VERSION 5.8 ;
BUSBITCHARS "[]" ;
DIVIDERCHAR "/" ;
UNITS
    DATABASE MICRONS 1000 ;
END UNITS

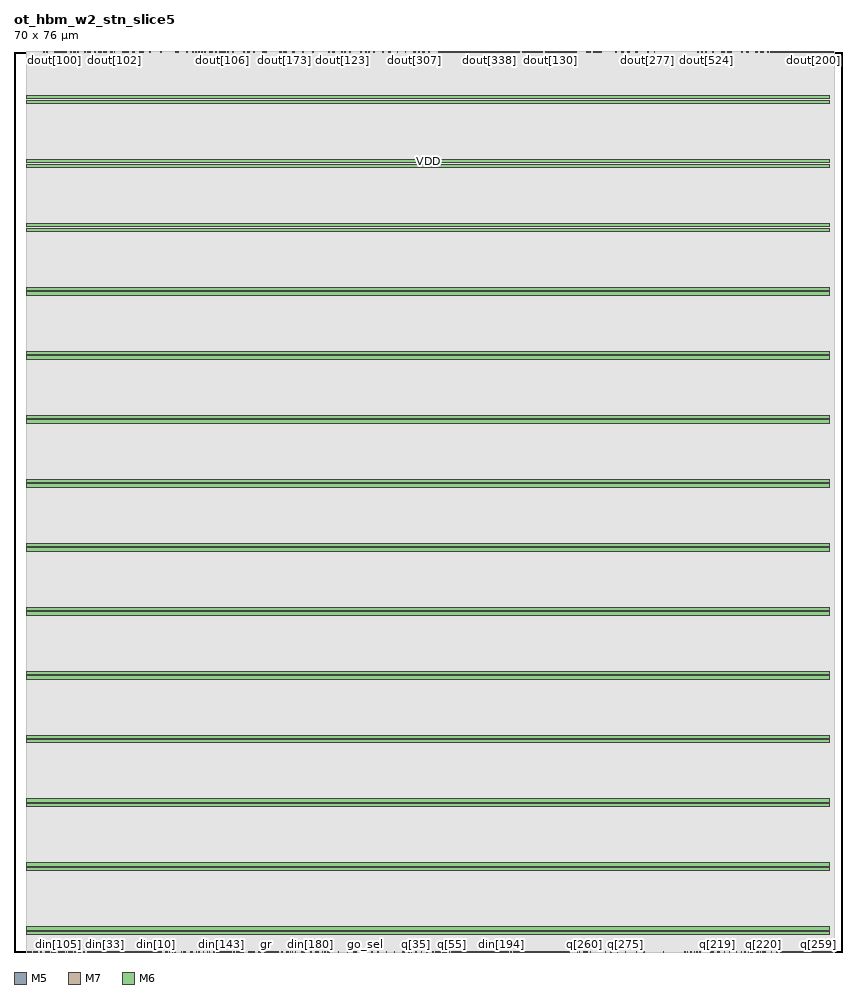
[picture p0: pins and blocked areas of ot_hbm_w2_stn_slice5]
MACRO ot_hbm_w2_stn_slice5
  FOREIGN ot_hbm_w2_stn_slice5 0 0 ;
  CLASS BLOCK ;
  SIZE 70 BY 76 ;
  PIN clk
    DIRECTION INPUT ;
    USE SIGNAL ;
    PORT
      LAYER M5 ;
        RECT  1.488 0 1.512 0.084 ;
    END
  END clk
  PIN din[0]
    DIRECTION INPUT ;
    USE SIGNAL ;
    PORT
      LAYER M7 ;
        RECT  11.52 0 11.552 0.069 ;
    END
  END din[0]
  PIN din[100]
    DIRECTION INPUT ;
    USE SIGNAL ;
    PORT
      LAYER M5 ;
        RECT  4.224 0 4.248 0.084 ;
    END
  END din[100]
  PIN din[101]
    DIRECTION INPUT ;
    USE SIGNAL ;
    PORT
      LAYER M5 ;
        RECT  4.272 0 4.296 0.084 ;
    END
  END din[101]
  PIN din[102]
    DIRECTION INPUT ;
    USE SIGNAL ;
    PORT
      LAYER M5 ;
        RECT  4.656 0 4.68 0.084 ;
    END
  END din[102]
  PIN din[103]
    DIRECTION INPUT ;
    USE SIGNAL ;
    PORT
      LAYER M5 ;
        RECT  4.704 0 4.728 0.084 ;
    END
  END din[103]
  PIN din[104]
    DIRECTION INPUT ;
    USE SIGNAL ;
    PORT
      LAYER M7 ;
        RECT  6.784 0 6.816 0.069 ;
    END
  END din[104]
  PIN din[105]
    DIRECTION INPUT ;
    USE SIGNAL ;
    PORT
      LAYER M5 ;
        RECT  3.744 0 3.768 0.084 ;
    END
  END din[105]
  PIN din[106]
    DIRECTION INPUT ;
    USE SIGNAL ;
    PORT
      LAYER M7 ;
        RECT  11.456 0 11.488 0.069 ;
    END
  END din[106]
  PIN din[107]
    DIRECTION INPUT ;
    USE SIGNAL ;
    PORT
      LAYER M7 ;
        RECT  7.808 0 7.84 0.069 ;
    END
  END din[107]
  PIN din[108]
    DIRECTION INPUT ;
    USE SIGNAL ;
    PORT
      LAYER M7 ;
        RECT  8.704 0 8.736 0.069 ;
    END
  END din[108]
  PIN din[109]
    DIRECTION INPUT ;
    USE SIGNAL ;
    PORT
      LAYER M7 ;
        RECT  9.28 0 9.312 0.069 ;
    END
  END din[109]
  PIN din[10]
    DIRECTION INPUT ;
    USE SIGNAL ;
    PORT
      LAYER M5 ;
        RECT  12 0 12.024 0.084 ;
    END
  END din[10]
  PIN din[110]
    DIRECTION INPUT ;
    USE SIGNAL ;
    PORT
      LAYER M7 ;
        RECT  6.272 0 6.304 0.069 ;
    END
  END din[110]
  PIN din[111]
    DIRECTION INPUT ;
    USE SIGNAL ;
    PORT
      LAYER M7 ;
        RECT  7.744 0 7.776 0.069 ;
    END
  END din[111]
  PIN din[112]
    DIRECTION INPUT ;
    USE SIGNAL ;
    PORT
      LAYER M7 ;
        RECT  9.728 0 9.76 0.069 ;
    END
  END din[112]
  PIN din[113]
    DIRECTION INPUT ;
    USE SIGNAL ;
    PORT
      LAYER M5 ;
        RECT  11.232 0 11.256 0.084 ;
    END
  END din[113]
  PIN din[114]
    DIRECTION INPUT ;
    USE SIGNAL ;
    PORT
      LAYER M7 ;
        RECT  10.944 0 10.976 0.069 ;
    END
  END din[114]
  PIN din[115]
    DIRECTION INPUT ;
    USE SIGNAL ;
    PORT
      LAYER M7 ;
        RECT  11.136 0 11.168 0.069 ;
    END
  END din[115]
  PIN din[116]
    DIRECTION INPUT ;
    USE SIGNAL ;
    PORT
      LAYER M5 ;
        RECT  11.568 0 11.592 0.084 ;
    END
  END din[116]
  PIN din[117]
    DIRECTION INPUT ;
    USE SIGNAL ;
    PORT
      LAYER M5 ;
        RECT  5.088 0 5.112 0.084 ;
    END
  END din[117]
  PIN din[118]
    DIRECTION INPUT ;
    USE SIGNAL ;
    PORT
      LAYER M5 ;
        RECT  13.104 0 13.128 0.084 ;
    END
  END din[118]
  PIN din[119]
    DIRECTION INPUT ;
    USE SIGNAL ;
    PORT
      LAYER M5 ;
        RECT  14.16 0 14.184 0.084 ;
    END
  END din[119]
  PIN din[11]
    DIRECTION INPUT ;
    USE SIGNAL ;
    PORT
      LAYER M7 ;
        RECT  9.536 0 9.568 0.069 ;
    END
  END din[11]
  PIN din[120]
    DIRECTION INPUT ;
    USE SIGNAL ;
    PORT
      LAYER M5 ;
        RECT  2.976 0 3 0.084 ;
    END
  END din[120]
  PIN din[121]
    DIRECTION INPUT ;
    USE SIGNAL ;
    PORT
      LAYER M5 ;
        RECT  14.976 0 15 0.084 ;
    END
  END din[121]
  PIN din[122]
    DIRECTION INPUT ;
    USE SIGNAL ;
    PORT
      LAYER M5 ;
        RECT  14.88 0 14.904 0.084 ;
    END
  END din[122]
  PIN din[123]
    DIRECTION INPUT ;
    USE SIGNAL ;
    PORT
      LAYER M5 ;
        RECT  14.928 0 14.952 0.084 ;
    END
  END din[123]
  PIN din[124]
    DIRECTION INPUT ;
    USE SIGNAL ;
    PORT
      LAYER M5 ;
        RECT  12.864 0 12.888 0.084 ;
    END
  END din[124]
  PIN din[125]
    DIRECTION INPUT ;
    USE SIGNAL ;
    PORT
      LAYER M5 ;
        RECT  14.352 0 14.376 0.084 ;
    END
  END din[125]
  PIN din[126]
    DIRECTION INPUT ;
    USE SIGNAL ;
    PORT
      LAYER M7 ;
        RECT  6.4 0 6.432 0.069 ;
    END
  END din[126]
  PIN din[127]
    DIRECTION INPUT ;
    USE SIGNAL ;
    PORT
      LAYER M5 ;
        RECT  4.8 0 4.824 0.084 ;
    END
  END din[127]
  PIN din[128]
    DIRECTION INPUT ;
    USE SIGNAL ;
    PORT
      LAYER M5 ;
        RECT  17.328 0 17.352 0.084 ;
    END
  END din[128]
  PIN din[129]
    DIRECTION INPUT ;
    USE SIGNAL ;
    PORT
      LAYER M7 ;
        RECT  21.696 0 21.728 0.069 ;
    END
  END din[129]
  PIN din[12]
    DIRECTION INPUT ;
    USE SIGNAL ;
    PORT
      LAYER M7 ;
        RECT  9.856 0 9.888 0.069 ;
    END
  END din[12]
  PIN din[130]
    DIRECTION INPUT ;
    USE SIGNAL ;
    PORT
      LAYER M7 ;
        RECT  17.856 0 17.888 0.069 ;
    END
  END din[130]
  PIN din[131]
    DIRECTION INPUT ;
    USE SIGNAL ;
    PORT
      LAYER M7 ;
        RECT  21.632 0 21.664 0.069 ;
    END
  END din[131]
  PIN din[132]
    DIRECTION INPUT ;
    USE SIGNAL ;
    PORT
      LAYER M7 ;
        RECT  19.072 0 19.104 0.069 ;
    END
  END din[132]
  PIN din[133]
    DIRECTION INPUT ;
    USE SIGNAL ;
    PORT
      LAYER M7 ;
        RECT  18.88 0 18.912 0.069 ;
    END
  END din[133]
  PIN din[134]
    DIRECTION INPUT ;
    USE SIGNAL ;
    PORT
      LAYER M7 ;
        RECT  19.264 0 19.296 0.069 ;
    END
  END din[134]
  PIN din[135]
    DIRECTION INPUT ;
    USE SIGNAL ;
    PORT
      LAYER M7 ;
        RECT  17.792 0 17.824 0.069 ;
    END
  END din[135]
  PIN din[136]
    DIRECTION INPUT ;
    USE SIGNAL ;
    PORT
      LAYER M7 ;
        RECT  18.304 0 18.336 0.069 ;
    END
  END din[136]
  PIN din[137]
    DIRECTION INPUT ;
    USE SIGNAL ;
    PORT
      LAYER M7 ;
        RECT  17.28 0 17.312 0.069 ;
    END
  END din[137]
  PIN din[138]
    DIRECTION INPUT ;
    USE SIGNAL ;
    PORT
      LAYER M7 ;
        RECT  17.408 0 17.44 0.069 ;
    END
  END din[138]
  PIN din[139]
    DIRECTION INPUT ;
    USE SIGNAL ;
    PORT
      LAYER M7 ;
        RECT  18.112 0 18.144 0.069 ;
    END
  END din[139]
  PIN din[13]
    DIRECTION INPUT ;
    USE SIGNAL ;
    PORT
      LAYER M5 ;
        RECT  11.904 0 11.928 0.084 ;
    END
  END din[13]
  PIN din[140]
    DIRECTION INPUT ;
    USE SIGNAL ;
    PORT
      LAYER M7 ;
        RECT  18.24 0 18.272 0.069 ;
    END
  END din[140]
  PIN din[141]
    DIRECTION INPUT ;
    USE SIGNAL ;
    PORT
      LAYER M7 ;
        RECT  17.728 0 17.76 0.069 ;
    END
  END din[141]
  PIN din[142]
    DIRECTION INPUT ;
    USE SIGNAL ;
    PORT
      LAYER M7 ;
        RECT  17.472 0 17.504 0.069 ;
    END
  END din[142]
  PIN din[143]
    DIRECTION INPUT ;
    USE SIGNAL ;
    PORT
      LAYER M5 ;
        RECT  17.472 0 17.496 0.084 ;
    END
  END din[143]
  PIN din[144]
    DIRECTION INPUT ;
    USE SIGNAL ;
    PORT
      LAYER M5 ;
        RECT  17.664 0 17.688 0.084 ;
    END
  END din[144]
  PIN din[145]
    DIRECTION INPUT ;
    USE SIGNAL ;
    PORT
      LAYER M5 ;
        RECT  17.376 0 17.4 0.084 ;
    END
  END din[145]
  PIN din[146]
    DIRECTION INPUT ;
    USE SIGNAL ;
    PORT
      LAYER M5 ;
        RECT  17.568 0 17.592 0.084 ;
    END
  END din[146]
  PIN din[147]
    DIRECTION INPUT ;
    USE SIGNAL ;
    PORT
      LAYER M5 ;
        RECT  17.52 0 17.544 0.084 ;
    END
  END din[147]
  PIN din[148]
    DIRECTION INPUT ;
    USE SIGNAL ;
    PORT
      LAYER M5 ;
        RECT  17.616 0 17.64 0.084 ;
    END
  END din[148]
  PIN din[149]
    DIRECTION INPUT ;
    USE SIGNAL ;
    PORT
      LAYER M5 ;
        RECT  17.424 0 17.448 0.084 ;
    END
  END din[149]
  PIN din[14]
    DIRECTION INPUT ;
    USE SIGNAL ;
    PORT
      LAYER M5 ;
        RECT  12.288 0 12.312 0.084 ;
    END
  END din[14]
  PIN din[150]
    DIRECTION INPUT ;
    USE SIGNAL ;
    PORT
      LAYER M7 ;
        RECT  17.92 0 17.952 0.069 ;
    END
  END din[150]
  PIN din[151]
    DIRECTION INPUT ;
    USE SIGNAL ;
    PORT
      LAYER M7 ;
        RECT  18.56 0 18.592 0.069 ;
    END
  END din[151]
  PIN din[152]
    DIRECTION INPUT ;
    USE SIGNAL ;
    PORT
      LAYER M7 ;
        RECT  18.176 0 18.208 0.069 ;
    END
  END din[152]
  PIN din[153]
    DIRECTION INPUT ;
    USE SIGNAL ;
    PORT
      LAYER M7 ;
        RECT  19.136 0 19.168 0.069 ;
    END
  END din[153]
  PIN din[154]
    DIRECTION INPUT ;
    USE SIGNAL ;
    PORT
      LAYER M7 ;
        RECT  19.008 0 19.04 0.069 ;
    END
  END din[154]
  PIN din[155]
    DIRECTION INPUT ;
    USE SIGNAL ;
    PORT
      LAYER M7 ;
        RECT  19.2 0 19.232 0.069 ;
    END
  END din[155]
  PIN din[156]
    DIRECTION INPUT ;
    USE SIGNAL ;
    PORT
      LAYER M7 ;
        RECT  17.344 0 17.376 0.069 ;
    END
  END din[156]
  PIN din[157]
    DIRECTION INPUT ;
    USE SIGNAL ;
    PORT
      LAYER M7 ;
        RECT  17.664 0 17.696 0.069 ;
    END
  END din[157]
  PIN din[158]
    DIRECTION INPUT ;
    USE SIGNAL ;
    PORT
      LAYER M7 ;
        RECT  18.048 0 18.08 0.069 ;
    END
  END din[158]
  PIN din[159]
    DIRECTION INPUT ;
    USE SIGNAL ;
    PORT
      LAYER M7 ;
        RECT  17.984 0 18.016 0.069 ;
    END
  END din[159]
  PIN din[15]
    DIRECTION INPUT ;
    USE SIGNAL ;
    PORT
      LAYER M7 ;
        RECT  9.664 0 9.696 0.069 ;
    END
  END din[15]
  PIN din[160]
    DIRECTION INPUT ;
    USE SIGNAL ;
    PORT
      LAYER M7 ;
        RECT  17.6 0 17.632 0.069 ;
    END
  END din[160]
  PIN din[161]
    DIRECTION INPUT ;
    USE SIGNAL ;
    PORT
      LAYER M7 ;
        RECT  21.248 0 21.28 0.069 ;
    END
  END din[161]
  PIN din[162]
    DIRECTION INPUT ;
    USE SIGNAL ;
    PORT
      LAYER M7 ;
        RECT  20.032 0 20.064 0.069 ;
    END
  END din[162]
  PIN din[163]
    DIRECTION INPUT ;
    USE SIGNAL ;
    PORT
      LAYER M7 ;
        RECT  18.624 0 18.656 0.069 ;
    END
  END din[163]
  PIN din[164]
    DIRECTION INPUT ;
    USE SIGNAL ;
    PORT
      LAYER M7 ;
        RECT  21.44 0 21.472 0.069 ;
    END
  END din[164]
  PIN din[165]
    DIRECTION INPUT ;
    USE SIGNAL ;
    PORT
      LAYER M5 ;
        RECT  23.328 0 23.352 0.084 ;
    END
  END din[165]
  PIN din[166]
    DIRECTION INPUT ;
    USE SIGNAL ;
    PORT
      LAYER M5 ;
        RECT  23.136 0 23.16 0.084 ;
    END
  END din[166]
  PIN din[167]
    DIRECTION INPUT ;
    USE SIGNAL ;
    PORT
      LAYER M7 ;
        RECT  21.12 0 21.152 0.069 ;
    END
  END din[167]
  PIN din[168]
    DIRECTION INPUT ;
    USE SIGNAL ;
    PORT
      LAYER M7 ;
        RECT  22.208 0 22.24 0.069 ;
    END
  END din[168]
  PIN din[169]
    DIRECTION INPUT ;
    USE SIGNAL ;
    PORT
      LAYER M7 ;
        RECT  21.888 0 21.92 0.069 ;
    END
  END din[169]
  PIN din[16]
    DIRECTION INPUT ;
    USE SIGNAL ;
    PORT
      LAYER M5 ;
        RECT  11.184 0 11.208 0.084 ;
    END
  END din[16]
  PIN din[170]
    DIRECTION INPUT ;
    USE SIGNAL ;
    PORT
      LAYER M7 ;
        RECT  19.904 0 19.936 0.069 ;
    END
  END din[170]
  PIN din[171]
    DIRECTION INPUT ;
    USE SIGNAL ;
    PORT
      LAYER M7 ;
        RECT  20.8 0 20.832 0.069 ;
    END
  END din[171]
  PIN din[172]
    DIRECTION INPUT ;
    USE SIGNAL ;
    PORT
      LAYER M7 ;
        RECT  21.504 0 21.536 0.069 ;
    END
  END din[172]
  PIN din[173]
    DIRECTION INPUT ;
    USE SIGNAL ;
    PORT
      LAYER M7 ;
        RECT  22.144 0 22.176 0.069 ;
    END
  END din[173]
  PIN din[174]
    DIRECTION INPUT ;
    USE SIGNAL ;
    PORT
      LAYER M7 ;
        RECT  22.336 0 22.368 0.069 ;
    END
  END din[174]
  PIN din[175]
    DIRECTION INPUT ;
    USE SIGNAL ;
    PORT
      LAYER M7 ;
        RECT  20.288 0 20.32 0.069 ;
    END
  END din[175]
  PIN din[176]
    DIRECTION INPUT ;
    USE SIGNAL ;
    PORT
      LAYER M7 ;
        RECT  21.76 0 21.792 0.069 ;
    END
  END din[176]
  PIN din[177]
    DIRECTION INPUT ;
    USE SIGNAL ;
    PORT
      LAYER M5 ;
        RECT  26.448 0 26.472 0.084 ;
    END
  END din[177]
  PIN din[178]
    DIRECTION INPUT ;
    USE SIGNAL ;
    PORT
      LAYER M7 ;
        RECT  20.672 0 20.704 0.069 ;
    END
  END din[178]
  PIN din[179]
    DIRECTION INPUT ;
    USE SIGNAL ;
    PORT
      LAYER M7 ;
        RECT  20.224 0 20.256 0.069 ;
    END
  END din[179]
  PIN din[17]
    DIRECTION INPUT ;
    USE SIGNAL ;
    PORT
      LAYER M5 ;
        RECT  12.144 0 12.168 0.084 ;
    END
  END din[17]
  PIN din[180]
    DIRECTION INPUT ;
    USE SIGNAL ;
    PORT
      LAYER M5 ;
        RECT  25.056 0 25.08 0.084 ;
    END
  END din[180]
  PIN din[181]
    DIRECTION INPUT ;
    USE SIGNAL ;
    PORT
      LAYER M5 ;
        RECT  26.256 0 26.28 0.084 ;
    END
  END din[181]
  PIN din[182]
    DIRECTION INPUT ;
    USE SIGNAL ;
    PORT
      LAYER M5 ;
        RECT  25.728 0 25.752 0.084 ;
    END
  END din[182]
  PIN din[183]
    DIRECTION INPUT ;
    USE SIGNAL ;
    PORT
      LAYER M7 ;
        RECT  21.312 0 21.344 0.069 ;
    END
  END din[183]
  PIN din[184]
    DIRECTION INPUT ;
    USE SIGNAL ;
    PORT
      LAYER M5 ;
        RECT  23.76 0 23.784 0.084 ;
    END
  END din[184]
  PIN din[185]
    DIRECTION INPUT ;
    USE SIGNAL ;
    PORT
      LAYER M5 ;
        RECT  25.536 0 25.56 0.084 ;
    END
  END din[185]
  PIN din[186]
    DIRECTION INPUT ;
    USE SIGNAL ;
    PORT
      LAYER M7 ;
        RECT  20.608 0 20.64 0.069 ;
    END
  END din[186]
  PIN din[187]
    DIRECTION INPUT ;
    USE SIGNAL ;
    PORT
      LAYER M5 ;
        RECT  24.288 0 24.312 0.084 ;
    END
  END din[187]
  PIN din[188]
    DIRECTION INPUT ;
    USE SIGNAL ;
    PORT
      LAYER M5 ;
        RECT  25.44 0 25.464 0.084 ;
    END
  END din[188]
  PIN din[189]
    DIRECTION INPUT ;
    USE SIGNAL ;
    PORT
      LAYER M7 ;
        RECT  19.84 0 19.872 0.069 ;
    END
  END din[189]
  PIN din[18]
    DIRECTION INPUT ;
    USE SIGNAL ;
    PORT
      LAYER M5 ;
        RECT  11.472 0 11.496 0.084 ;
    END
  END din[18]
  PIN din[190]
    DIRECTION INPUT ;
    USE SIGNAL ;
    PORT
      LAYER M7 ;
        RECT  20.736 0 20.768 0.069 ;
    END
  END din[190]
  PIN din[191]
    DIRECTION INPUT ;
    USE SIGNAL ;
    PORT
      LAYER M5 ;
        RECT  24.48 0 24.504 0.084 ;
    END
  END din[191]
  PIN din[192]
    DIRECTION INPUT ;
    USE SIGNAL ;
    PORT
      LAYER M5 ;
        RECT  41.184 0 41.208 0.084 ;
    END
  END din[192]
  PIN din[193]
    DIRECTION INPUT ;
    USE SIGNAL ;
    PORT
      LAYER M5 ;
        RECT  41.04 0 41.064 0.084 ;
    END
  END din[193]
  PIN din[194]
    DIRECTION INPUT ;
    USE SIGNAL ;
    PORT
      LAYER M5 ;
        RECT  41.136 0 41.16 0.084 ;
    END
  END din[194]
  PIN din[195]
    DIRECTION INPUT ;
    USE SIGNAL ;
    PORT
      LAYER M5 ;
        RECT  40.512 0 40.536 0.084 ;
    END
  END din[195]
  PIN din[196]
    DIRECTION INPUT ;
    USE SIGNAL ;
    PORT
      LAYER M5 ;
        RECT  39.216 0 39.24 0.084 ;
    END
  END din[196]
  PIN din[197]
    DIRECTION INPUT ;
    USE SIGNAL ;
    PORT
      LAYER M5 ;
        RECT  39.936 0 39.96 0.084 ;
    END
  END din[197]
  PIN din[198]
    DIRECTION INPUT ;
    USE SIGNAL ;
    PORT
      LAYER M5 ;
        RECT  40.08 0 40.104 0.084 ;
    END
  END din[198]
  PIN din[199]
    DIRECTION INPUT ;
    USE SIGNAL ;
    PORT
      LAYER M5 ;
        RECT  39.168 0 39.192 0.084 ;
    END
  END din[199]
  PIN din[19]
    DIRECTION INPUT ;
    USE SIGNAL ;
    PORT
      LAYER M7 ;
        RECT  11.264 0 11.296 0.069 ;
    END
  END din[19]
  PIN din[1]
    DIRECTION INPUT ;
    USE SIGNAL ;
    PORT
      LAYER M5 ;
        RECT  12.432 0 12.456 0.084 ;
    END
  END din[1]
  PIN din[200]
    DIRECTION INPUT ;
    USE SIGNAL ;
    PORT
      LAYER M5 ;
        RECT  40.176 0 40.2 0.084 ;
    END
  END din[200]
  PIN din[201]
    DIRECTION INPUT ;
    USE SIGNAL ;
    PORT
      LAYER M5 ;
        RECT  39.312 0 39.336 0.084 ;
    END
  END din[201]
  PIN din[202]
    DIRECTION INPUT ;
    USE SIGNAL ;
    PORT
      LAYER M5 ;
        RECT  39.552 0 39.576 0.084 ;
    END
  END din[202]
  PIN din[203]
    DIRECTION INPUT ;
    USE SIGNAL ;
    PORT
      LAYER M5 ;
        RECT  41.088 0 41.112 0.084 ;
    END
  END din[203]
  PIN din[204]
    DIRECTION INPUT ;
    USE SIGNAL ;
    PORT
      LAYER M5 ;
        RECT  40.56 0 40.584 0.084 ;
    END
  END din[204]
  PIN din[205]
    DIRECTION INPUT ;
    USE SIGNAL ;
    PORT
      LAYER M5 ;
        RECT  40.704 0 40.728 0.084 ;
    END
  END din[205]
  PIN din[206]
    DIRECTION INPUT ;
    USE SIGNAL ;
    PORT
      LAYER M7 ;
        RECT  45.504 0 45.536 0.069 ;
    END
  END din[206]
  PIN din[207]
    DIRECTION INPUT ;
    USE SIGNAL ;
    PORT
      LAYER M7 ;
        RECT  44.416 0 44.448 0.069 ;
    END
  END din[207]
  PIN din[208]
    DIRECTION INPUT ;
    USE SIGNAL ;
    PORT
      LAYER M5 ;
        RECT  39.024 0 39.048 0.084 ;
    END
  END din[208]
  PIN din[209]
    DIRECTION INPUT ;
    USE SIGNAL ;
    PORT
      LAYER M7 ;
        RECT  45.056 0 45.088 0.069 ;
    END
  END din[209]
  PIN din[20]
    DIRECTION INPUT ;
    USE SIGNAL ;
    PORT
      LAYER M5 ;
        RECT  11.328 0 11.352 0.084 ;
    END
  END din[20]
  PIN din[210]
    DIRECTION INPUT ;
    USE SIGNAL ;
    PORT
      LAYER M7 ;
        RECT  46.464 0 46.496 0.069 ;
    END
  END din[210]
  PIN din[211]
    DIRECTION INPUT ;
    USE SIGNAL ;
    PORT
      LAYER M5 ;
        RECT  40.416 0 40.44 0.084 ;
    END
  END din[211]
  PIN din[212]
    DIRECTION INPUT ;
    USE SIGNAL ;
    PORT
      LAYER M5 ;
        RECT  40.992 0 41.016 0.084 ;
    END
  END din[212]
  PIN din[213]
    DIRECTION INPUT ;
    USE SIGNAL ;
    PORT
      LAYER M7 ;
        RECT  46.72 0 46.752 0.069 ;
    END
  END din[213]
  PIN din[214]
    DIRECTION INPUT ;
    USE SIGNAL ;
    PORT
      LAYER M7 ;
        RECT  46.784 0 46.816 0.069 ;
    END
  END din[214]
  PIN din[215]
    DIRECTION INPUT ;
    USE SIGNAL ;
    PORT
      LAYER M5 ;
        RECT  41.76 0 41.784 0.084 ;
    END
  END din[215]
  PIN din[216]
    DIRECTION INPUT ;
    USE SIGNAL ;
    PORT
      LAYER M7 ;
        RECT  46.528 0 46.56 0.069 ;
    END
  END din[216]
  PIN din[217]
    DIRECTION INPUT ;
    USE SIGNAL ;
    PORT
      LAYER M5 ;
        RECT  41.472 0 41.496 0.084 ;
    END
  END din[217]
  PIN din[218]
    DIRECTION INPUT ;
    USE SIGNAL ;
    PORT
      LAYER M7 ;
        RECT  46.272 0 46.304 0.069 ;
    END
  END din[218]
  PIN din[219]
    DIRECTION INPUT ;
    USE SIGNAL ;
    PORT
      LAYER M7 ;
        RECT  46.144 0 46.176 0.069 ;
    END
  END din[219]
  PIN din[21]
    DIRECTION INPUT ;
    USE SIGNAL ;
    PORT
      LAYER M5 ;
        RECT  11.664 0 11.688 0.084 ;
    END
  END din[21]
  PIN din[220]
    DIRECTION INPUT ;
    USE SIGNAL ;
    PORT
      LAYER M5 ;
        RECT  40.128 0 40.152 0.084 ;
    END
  END din[220]
  PIN din[221]
    DIRECTION INPUT ;
    USE SIGNAL ;
    PORT
      LAYER M7 ;
        RECT  46.912 0 46.944 0.069 ;
    END
  END din[221]
  PIN din[222]
    DIRECTION INPUT ;
    USE SIGNAL ;
    PORT
      LAYER M5 ;
        RECT  43.008 0 43.032 0.084 ;
    END
  END din[222]
  PIN din[223]
    DIRECTION INPUT ;
    USE SIGNAL ;
    PORT
      LAYER M7 ;
        RECT  46.592 0 46.624 0.069 ;
    END
  END din[223]
  PIN din[224]
    DIRECTION INPUT ;
    USE SIGNAL ;
    PORT
      LAYER M7 ;
        RECT  46.656 0 46.688 0.069 ;
    END
  END din[224]
  PIN din[225]
    DIRECTION INPUT ;
    USE SIGNAL ;
    PORT
      LAYER M5 ;
        RECT  43.824 0 43.848 0.084 ;
    END
  END din[225]
  PIN din[226]
    DIRECTION INPUT ;
    USE SIGNAL ;
    PORT
      LAYER M5 ;
        RECT  40.224 0 40.248 0.084 ;
    END
  END din[226]
  PIN din[227]
    DIRECTION INPUT ;
    USE SIGNAL ;
    PORT
      LAYER M5 ;
        RECT  43.92 0 43.944 0.084 ;
    END
  END din[227]
  PIN din[228]
    DIRECTION INPUT ;
    USE SIGNAL ;
    PORT
      LAYER M5 ;
        RECT  39.648 0 39.672 0.084 ;
    END
  END din[228]
  PIN din[229]
    DIRECTION INPUT ;
    USE SIGNAL ;
    PORT
      LAYER M5 ;
        RECT  43.2 0 43.224 0.084 ;
    END
  END din[229]
  PIN din[22]
    DIRECTION INPUT ;
    USE SIGNAL ;
    PORT
      LAYER M7 ;
        RECT  10.304 0 10.336 0.069 ;
    END
  END din[22]
  PIN din[230]
    DIRECTION INPUT ;
    USE SIGNAL ;
    PORT
      LAYER M5 ;
        RECT  42.288 0 42.312 0.084 ;
    END
  END din[230]
  PIN din[231]
    DIRECTION INPUT ;
    USE SIGNAL ;
    PORT
      LAYER M5 ;
        RECT  39.888 0 39.912 0.084 ;
    END
  END din[231]
  PIN din[232]
    DIRECTION INPUT ;
    USE SIGNAL ;
    PORT
      LAYER M5 ;
        RECT  41.232 0 41.256 0.084 ;
    END
  END din[232]
  PIN din[233]
    DIRECTION INPUT ;
    USE SIGNAL ;
    PORT
      LAYER M5 ;
        RECT  43.056 0 43.08 0.084 ;
    END
  END din[233]
  PIN din[234]
    DIRECTION INPUT ;
    USE SIGNAL ;
    PORT
      LAYER M5 ;
        RECT  43.104 0 43.128 0.084 ;
    END
  END din[234]
  PIN din[235]
    DIRECTION INPUT ;
    USE SIGNAL ;
    PORT
      LAYER M5 ;
        RECT  39.84 0 39.864 0.084 ;
    END
  END din[235]
  PIN din[236]
    DIRECTION INPUT ;
    USE SIGNAL ;
    PORT
      LAYER M5 ;
        RECT  39.792 0 39.816 0.084 ;
    END
  END din[236]
  PIN din[237]
    DIRECTION INPUT ;
    USE SIGNAL ;
    PORT
      LAYER M5 ;
        RECT  42.192 0 42.216 0.084 ;
    END
  END din[237]
  PIN din[238]
    DIRECTION INPUT ;
    USE SIGNAL ;
    PORT
      LAYER M5 ;
        RECT  40.32 0 40.344 0.084 ;
    END
  END din[238]
  PIN din[239]
    DIRECTION INPUT ;
    USE SIGNAL ;
    PORT
      LAYER M5 ;
        RECT  39.6 0 39.624 0.084 ;
    END
  END din[239]
  PIN din[23]
    DIRECTION INPUT ;
    USE SIGNAL ;
    PORT
      LAYER M7 ;
        RECT  10.56 0 10.592 0.069 ;
    END
  END din[23]
  PIN din[240]
    DIRECTION INPUT ;
    USE SIGNAL ;
    PORT
      LAYER M5 ;
        RECT  40.8 0 40.824 0.084 ;
    END
  END din[240]
  PIN din[241]
    DIRECTION INPUT ;
    USE SIGNAL ;
    PORT
      LAYER M5 ;
        RECT  41.28 0 41.304 0.084 ;
    END
  END din[241]
  PIN din[242]
    DIRECTION INPUT ;
    USE SIGNAL ;
    PORT
      LAYER M5 ;
        RECT  42.336 0 42.36 0.084 ;
    END
  END din[242]
  PIN din[243]
    DIRECTION INPUT ;
    USE SIGNAL ;
    PORT
      LAYER M5 ;
        RECT  40.272 0 40.296 0.084 ;
    END
  END din[243]
  PIN din[244]
    DIRECTION INPUT ;
    USE SIGNAL ;
    PORT
      LAYER M5 ;
        RECT  41.376 0 41.4 0.084 ;
    END
  END din[244]
  PIN din[245]
    DIRECTION INPUT ;
    USE SIGNAL ;
    PORT
      LAYER M5 ;
        RECT  39.504 0 39.528 0.084 ;
    END
  END din[245]
  PIN din[246]
    DIRECTION INPUT ;
    USE SIGNAL ;
    PORT
      LAYER M5 ;
        RECT  38.832 0 38.856 0.084 ;
    END
  END din[246]
  PIN din[247]
    DIRECTION INPUT ;
    USE SIGNAL ;
    PORT
      LAYER M5 ;
        RECT  39.456 0 39.48 0.084 ;
    END
  END din[247]
  PIN din[248]
    DIRECTION INPUT ;
    USE SIGNAL ;
    PORT
      LAYER M5 ;
        RECT  37.584 0 37.608 0.084 ;
    END
  END din[248]
  PIN din[249]
    DIRECTION INPUT ;
    USE SIGNAL ;
    PORT
      LAYER M5 ;
        RECT  38.688 0 38.712 0.084 ;
    END
  END din[249]
  PIN din[24]
    DIRECTION INPUT ;
    USE SIGNAL ;
    PORT
      LAYER M7 ;
        RECT  10.368 0 10.4 0.069 ;
    END
  END din[24]
  PIN din[250]
    DIRECTION INPUT ;
    USE SIGNAL ;
    PORT
      LAYER M5 ;
        RECT  37.776 0 37.8 0.084 ;
    END
  END din[250]
  PIN din[251]
    DIRECTION INPUT ;
    USE SIGNAL ;
    PORT
      LAYER M5 ;
        RECT  38.784 0 38.808 0.084 ;
    END
  END din[251]
  PIN din[252]
    DIRECTION INPUT ;
    USE SIGNAL ;
    PORT
      LAYER M5 ;
        RECT  37.872 0 37.896 0.084 ;
    END
  END din[252]
  PIN din[253]
    DIRECTION INPUT ;
    USE SIGNAL ;
    PORT
      LAYER M5 ;
        RECT  38.4 0 38.424 0.084 ;
    END
  END din[253]
  PIN din[254]
    DIRECTION INPUT ;
    USE SIGNAL ;
    PORT
      LAYER M5 ;
        RECT  38.064 0 38.088 0.084 ;
    END
  END din[254]
  PIN din[255]
    DIRECTION INPUT ;
    USE SIGNAL ;
    PORT
      LAYER M5 ;
        RECT  38.352 0 38.376 0.084 ;
    END
  END din[255]
  PIN din[256]
    DIRECTION INPUT ;
    USE SIGNAL ;
    PORT
      LAYER M7 ;
        RECT  44.544 0 44.576 0.069 ;
    END
  END din[256]
  PIN din[257]
    DIRECTION INPUT ;
    USE SIGNAL ;
    PORT
      LAYER M5 ;
        RECT  44.208 0 44.232 0.084 ;
    END
  END din[257]
  PIN din[258]
    DIRECTION INPUT ;
    USE SIGNAL ;
    PORT
      LAYER M7 ;
        RECT  44.672 0 44.704 0.069 ;
    END
  END din[258]
  PIN din[259]
    DIRECTION INPUT ;
    USE SIGNAL ;
    PORT
      LAYER M7 ;
        RECT  44.992 0 45.024 0.069 ;
    END
  END din[259]
  PIN din[25]
    DIRECTION INPUT ;
    USE SIGNAL ;
    PORT
      LAYER M7 ;
        RECT  11.392 0 11.424 0.069 ;
    END
  END din[25]
  PIN din[260]
    DIRECTION INPUT ;
    USE SIGNAL ;
    PORT
      LAYER M7 ;
        RECT  44.48 0 44.512 0.069 ;
    END
  END din[260]
  PIN din[261]
    DIRECTION INPUT ;
    USE SIGNAL ;
    PORT
      LAYER M7 ;
        RECT  44.864 0 44.896 0.069 ;
    END
  END din[261]
  PIN din[262]
    DIRECTION INPUT ;
    USE SIGNAL ;
    PORT
      LAYER M5 ;
        RECT  44.784 0 44.808 0.084 ;
    END
  END din[262]
  PIN din[263]
    DIRECTION INPUT ;
    USE SIGNAL ;
    PORT
      LAYER M7 ;
        RECT  45.312 0 45.344 0.069 ;
    END
  END din[263]
  PIN din[264]
    DIRECTION INPUT ;
    USE SIGNAL ;
    PORT
      LAYER M7 ;
        RECT  45.184 0 45.216 0.069 ;
    END
  END din[264]
  PIN din[265]
    DIRECTION INPUT ;
    USE SIGNAL ;
    PORT
      LAYER M5 ;
        RECT  43.632 0 43.656 0.084 ;
    END
  END din[265]
  PIN din[266]
    DIRECTION INPUT ;
    USE SIGNAL ;
    PORT
      LAYER M5 ;
        RECT  44.256 0 44.28 0.084 ;
    END
  END din[266]
  PIN din[267]
    DIRECTION INPUT ;
    USE SIGNAL ;
    PORT
      LAYER M5 ;
        RECT  43.728 0 43.752 0.084 ;
    END
  END din[267]
  PIN din[268]
    DIRECTION INPUT ;
    USE SIGNAL ;
    PORT
      LAYER M7 ;
        RECT  44.8 0 44.832 0.069 ;
    END
  END din[268]
  PIN din[269]
    DIRECTION INPUT ;
    USE SIGNAL ;
    PORT
      LAYER M7 ;
        RECT  45.376 0 45.408 0.069 ;
    END
  END din[269]
  PIN din[26]
    DIRECTION INPUT ;
    USE SIGNAL ;
    PORT
      LAYER M7 ;
        RECT  9.984 0 10.016 0.069 ;
    END
  END din[26]
  PIN din[270]
    DIRECTION INPUT ;
    USE SIGNAL ;
    PORT
      LAYER M5 ;
        RECT  44.016 0 44.04 0.084 ;
    END
  END din[270]
  PIN din[271]
    DIRECTION INPUT ;
    USE SIGNAL ;
    PORT
      LAYER M5 ;
        RECT  43.488 0 43.512 0.084 ;
    END
  END din[271]
  PIN din[272]
    DIRECTION INPUT ;
    USE SIGNAL ;
    PORT
      LAYER M5 ;
        RECT  43.776 0 43.8 0.084 ;
    END
  END din[272]
  PIN din[273]
    DIRECTION INPUT ;
    USE SIGNAL ;
    PORT
      LAYER M5 ;
        RECT  44.352 0 44.376 0.084 ;
    END
  END din[273]
  PIN din[274]
    DIRECTION INPUT ;
    USE SIGNAL ;
    PORT
      LAYER M5 ;
        RECT  43.392 0 43.416 0.084 ;
    END
  END din[274]
  PIN din[275]
    DIRECTION INPUT ;
    USE SIGNAL ;
    PORT
      LAYER M5 ;
        RECT  43.584 0 43.608 0.084 ;
    END
  END din[275]
  PIN din[276]
    DIRECTION INPUT ;
    USE SIGNAL ;
    PORT
      LAYER M5 ;
        RECT  43.248 0 43.272 0.084 ;
    END
  END din[276]
  PIN din[277]
    DIRECTION INPUT ;
    USE SIGNAL ;
    PORT
      LAYER M5 ;
        RECT  43.536 0 43.56 0.084 ;
    END
  END din[277]
  PIN din[278]
    DIRECTION INPUT ;
    USE SIGNAL ;
    PORT
      LAYER M5 ;
        RECT  43.68 0 43.704 0.084 ;
    END
  END din[278]
  PIN din[279]
    DIRECTION INPUT ;
    USE SIGNAL ;
    PORT
      LAYER M5 ;
        RECT  43.44 0 43.464 0.084 ;
    END
  END din[279]
  PIN din[27]
    DIRECTION INPUT ;
    USE SIGNAL ;
    PORT
      LAYER M7 ;
        RECT  10.176 0 10.208 0.069 ;
    END
  END din[27]
  PIN din[28]
    DIRECTION INPUT ;
    USE SIGNAL ;
    PORT
      LAYER M7 ;
        RECT  9.6 0 9.632 0.069 ;
    END
  END din[28]
  PIN din[29]
    DIRECTION INPUT ;
    USE SIGNAL ;
    PORT
      LAYER M7 ;
        RECT  9.216 0 9.248 0.069 ;
    END
  END din[29]
  PIN din[2]
    DIRECTION INPUT ;
    USE SIGNAL ;
    PORT
      LAYER M5 ;
        RECT  11.376 0 11.4 0.084 ;
    END
  END din[2]
  PIN din[30]
    DIRECTION INPUT ;
    USE SIGNAL ;
    PORT
      LAYER M7 ;
        RECT  10.432 0 10.464 0.069 ;
    END
  END din[30]
  PIN din[31]
    DIRECTION INPUT ;
    USE SIGNAL ;
    PORT
      LAYER M7 ;
        RECT  9.472 0 9.504 0.069 ;
    END
  END din[31]
  PIN din[32]
    DIRECTION INPUT ;
    USE SIGNAL ;
    PORT
      LAYER M7 ;
        RECT  10.496 0 10.528 0.069 ;
    END
  END din[32]
  PIN din[33]
    DIRECTION INPUT ;
    USE SIGNAL ;
    PORT
      LAYER M7 ;
        RECT  7.68 0 7.712 0.069 ;
    END
  END din[33]
  PIN din[34]
    DIRECTION INPUT ;
    USE SIGNAL ;
    PORT
      LAYER M7 ;
        RECT  6.912 0 6.944 0.069 ;
    END
  END din[34]
  PIN din[35]
    DIRECTION INPUT ;
    USE SIGNAL ;
    PORT
      LAYER M7 ;
        RECT  8.96 0 8.992 0.069 ;
    END
  END din[35]
  PIN din[36]
    DIRECTION INPUT ;
    USE SIGNAL ;
    PORT
      LAYER M7 ;
        RECT  6.976 0 7.008 0.069 ;
    END
  END din[36]
  PIN din[37]
    DIRECTION INPUT ;
    USE SIGNAL ;
    PORT
      LAYER M7 ;
        RECT  7.424 0 7.456 0.069 ;
    END
  END din[37]
  PIN din[38]
    DIRECTION INPUT ;
    USE SIGNAL ;
    PORT
      LAYER M7 ;
        RECT  7.552 0 7.584 0.069 ;
    END
  END din[38]
  PIN din[39]
    DIRECTION INPUT ;
    USE SIGNAL ;
    PORT
      LAYER M7 ;
        RECT  8.512 0 8.544 0.069 ;
    END
  END din[39]
  PIN din[3]
    DIRECTION INPUT ;
    USE SIGNAL ;
    PORT
      LAYER M5 ;
        RECT  12.192 0 12.216 0.084 ;
    END
  END din[3]
  PIN din[40]
    DIRECTION INPUT ;
    USE SIGNAL ;
    PORT
      LAYER M7 ;
        RECT  9.024 0 9.056 0.069 ;
    END
  END din[40]
  PIN din[41]
    DIRECTION INPUT ;
    USE SIGNAL ;
    PORT
      LAYER M7 ;
        RECT  7.36 0 7.392 0.069 ;
    END
  END din[41]
  PIN din[42]
    DIRECTION INPUT ;
    USE SIGNAL ;
    PORT
      LAYER M7 ;
        RECT  7.616 0 7.648 0.069 ;
    END
  END din[42]
  PIN din[43]
    DIRECTION INPUT ;
    USE SIGNAL ;
    PORT
      LAYER M7 ;
        RECT  9.088 0 9.12 0.069 ;
    END
  END din[43]
  PIN din[44]
    DIRECTION INPUT ;
    USE SIGNAL ;
    PORT
      LAYER M7 ;
        RECT  9.152 0 9.184 0.069 ;
    END
  END din[44]
  PIN din[45]
    DIRECTION INPUT ;
    USE SIGNAL ;
    PORT
      LAYER M7 ;
        RECT  7.936 0 7.968 0.069 ;
    END
  END din[45]
  PIN din[46]
    DIRECTION INPUT ;
    USE SIGNAL ;
    PORT
      LAYER M7 ;
        RECT  7.488 0 7.52 0.069 ;
    END
  END din[46]
  PIN din[47]
    DIRECTION INPUT ;
    USE SIGNAL ;
    PORT
      LAYER M7 ;
        RECT  8.896 0 8.928 0.069 ;
    END
  END din[47]
  PIN din[48]
    DIRECTION INPUT ;
    USE SIGNAL ;
    PORT
      LAYER M7 ;
        RECT  8.256 0 8.288 0.069 ;
    END
  END din[48]
  PIN din[49]
    DIRECTION INPUT ;
    USE SIGNAL ;
    PORT
      LAYER M7 ;
        RECT  8.064 0 8.096 0.069 ;
    END
  END din[49]
  PIN din[4]
    DIRECTION INPUT ;
    USE SIGNAL ;
    PORT
      LAYER M7 ;
        RECT  10.88 0 10.912 0.069 ;
    END
  END din[4]
  PIN din[50]
    DIRECTION INPUT ;
    USE SIGNAL ;
    PORT
      LAYER M7 ;
        RECT  8.192 0 8.224 0.069 ;
    END
  END din[50]
  PIN din[51]
    DIRECTION INPUT ;
    USE SIGNAL ;
    PORT
      LAYER M7 ;
        RECT  9.408 0 9.44 0.069 ;
    END
  END din[51]
  PIN din[52]
    DIRECTION INPUT ;
    USE SIGNAL ;
    PORT
      LAYER M7 ;
        RECT  8.768 0 8.8 0.069 ;
    END
  END din[52]
  PIN din[53]
    DIRECTION INPUT ;
    USE SIGNAL ;
    PORT
      LAYER M7 ;
        RECT  8 0 8.032 0.069 ;
    END
  END din[53]
  PIN din[54]
    DIRECTION INPUT ;
    USE SIGNAL ;
    PORT
      LAYER M7 ;
        RECT  7.872 0 7.904 0.069 ;
    END
  END din[54]
  PIN din[55]
    DIRECTION INPUT ;
    USE SIGNAL ;
    PORT
      LAYER M7 ;
        RECT  8.832 0 8.864 0.069 ;
    END
  END din[55]
  PIN din[56]
    DIRECTION INPUT ;
    USE SIGNAL ;
    PORT
      LAYER M7 ;
        RECT  10.24 0 10.272 0.069 ;
    END
  END din[56]
  PIN din[57]
    DIRECTION INPUT ;
    USE SIGNAL ;
    PORT
      LAYER M5 ;
        RECT  12.336 0 12.36 0.084 ;
    END
  END din[57]
  PIN din[58]
    DIRECTION INPUT ;
    USE SIGNAL ;
    PORT
      LAYER M5 ;
        RECT  11.808 0 11.832 0.084 ;
    END
  END din[58]
  PIN din[59]
    DIRECTION INPUT ;
    USE SIGNAL ;
    PORT
      LAYER M5 ;
        RECT  12.384 0 12.408 0.084 ;
    END
  END din[59]
  PIN din[5]
    DIRECTION INPUT ;
    USE SIGNAL ;
    PORT
      LAYER M7 ;
        RECT  10.112 0 10.144 0.069 ;
    END
  END din[5]
  PIN din[60]
    DIRECTION INPUT ;
    USE SIGNAL ;
    PORT
      LAYER M7 ;
        RECT  11.072 0 11.104 0.069 ;
    END
  END din[60]
  PIN din[61]
    DIRECTION INPUT ;
    USE SIGNAL ;
    PORT
      LAYER M5 ;
        RECT  11.856 0 11.88 0.084 ;
    END
  END din[61]
  PIN din[62]
    DIRECTION INPUT ;
    USE SIGNAL ;
    PORT
      LAYER M7 ;
        RECT  10.816 0 10.848 0.069 ;
    END
  END din[62]
  PIN din[63]
    DIRECTION INPUT ;
    USE SIGNAL ;
    PORT
      LAYER M7 ;
        RECT  11.2 0 11.232 0.069 ;
    END
  END din[63]
  PIN din[64]
    DIRECTION INPUT ;
    USE SIGNAL ;
    PORT
      LAYER M5 ;
        RECT  12.24 0 12.264 0.084 ;
    END
  END din[64]
  PIN din[65]
    DIRECTION INPUT ;
    USE SIGNAL ;
    PORT
      LAYER M7 ;
        RECT  10.688 0 10.72 0.069 ;
    END
  END din[65]
  PIN din[66]
    DIRECTION INPUT ;
    USE SIGNAL ;
    PORT
      LAYER M7 ;
        RECT  7.296 0 7.328 0.069 ;
    END
  END din[66]
  PIN din[67]
    DIRECTION INPUT ;
    USE SIGNAL ;
    PORT
      LAYER M7 ;
        RECT  8.128 0 8.16 0.069 ;
    END
  END din[67]
  PIN din[68]
    DIRECTION INPUT ;
    USE SIGNAL ;
    PORT
      LAYER M5 ;
        RECT  6.336 0 6.36 0.084 ;
    END
  END din[68]
  PIN din[69]
    DIRECTION INPUT ;
    USE SIGNAL ;
    PORT
      LAYER M7 ;
        RECT  7.04 0 7.072 0.069 ;
    END
  END din[69]
  PIN din[6]
    DIRECTION INPUT ;
    USE SIGNAL ;
    PORT
      LAYER M7 ;
        RECT  10.752 0 10.784 0.069 ;
    END
  END din[6]
  PIN din[70]
    DIRECTION INPUT ;
    USE SIGNAL ;
    PORT
      LAYER M7 ;
        RECT  7.104 0 7.136 0.069 ;
    END
  END din[70]
  PIN din[71]
    DIRECTION INPUT ;
    USE SIGNAL ;
    PORT
      LAYER M5 ;
        RECT  6.24 0 6.264 0.084 ;
    END
  END din[71]
  PIN din[72]
    DIRECTION INPUT ;
    USE SIGNAL ;
    PORT
      LAYER M5 ;
        RECT  5.568 0 5.592 0.084 ;
    END
  END din[72]
  PIN din[73]
    DIRECTION INPUT ;
    USE SIGNAL ;
    PORT
      LAYER M5 ;
        RECT  5.856 0 5.88 0.084 ;
    END
  END din[73]
  PIN din[74]
    DIRECTION INPUT ;
    USE SIGNAL ;
    PORT
      LAYER M5 ;
        RECT  5.616 0 5.64 0.084 ;
    END
  END din[74]
  PIN din[75]
    DIRECTION INPUT ;
    USE SIGNAL ;
    PORT
      LAYER M5 ;
        RECT  4.944 0 4.968 0.084 ;
    END
  END din[75]
  PIN din[76]
    DIRECTION INPUT ;
    USE SIGNAL ;
    PORT
      LAYER M7 ;
        RECT  6.528 0 6.56 0.069 ;
    END
  END din[76]
  PIN din[77]
    DIRECTION INPUT ;
    USE SIGNAL ;
    PORT
      LAYER M5 ;
        RECT  3.504 0 3.528 0.084 ;
    END
  END din[77]
  PIN din[78]
    DIRECTION INPUT ;
    USE SIGNAL ;
    PORT
      LAYER M7 ;
        RECT  6.592 0 6.624 0.069 ;
    END
  END din[78]
  PIN din[79]
    DIRECTION INPUT ;
    USE SIGNAL ;
    PORT
      LAYER M7 ;
        RECT  11.328 0 11.36 0.069 ;
    END
  END din[79]
  PIN din[7]
    DIRECTION INPUT ;
    USE SIGNAL ;
    PORT
      LAYER M5 ;
        RECT  11.952 0 11.976 0.084 ;
    END
  END din[7]
  PIN din[80]
    DIRECTION INPUT ;
    USE SIGNAL ;
    PORT
      LAYER M5 ;
        RECT  3.168 0 3.192 0.084 ;
    END
  END din[80]
  PIN din[81]
    DIRECTION INPUT ;
    USE SIGNAL ;
    PORT
      LAYER M5 ;
        RECT  4.608 0 4.632 0.084 ;
    END
  END din[81]
  PIN din[82]
    DIRECTION INPUT ;
    USE SIGNAL ;
    PORT
      LAYER M5 ;
        RECT  2.304 0 2.328 0.084 ;
    END
  END din[82]
  PIN din[83]
    DIRECTION INPUT ;
    USE SIGNAL ;
    PORT
      LAYER M5 ;
        RECT  1.728 0 1.752 0.084 ;
    END
  END din[83]
  PIN din[84]
    DIRECTION INPUT ;
    USE SIGNAL ;
    PORT
      LAYER M5 ;
        RECT  1.68 0 1.704 0.084 ;
    END
  END din[84]
  PIN din[85]
    DIRECTION INPUT ;
    USE SIGNAL ;
    PORT
      LAYER M5 ;
        RECT  2.208 0 2.232 0.084 ;
    END
  END din[85]
  PIN din[86]
    DIRECTION INPUT ;
    USE SIGNAL ;
    PORT
      LAYER M5 ;
        RECT  1.152 0 1.176 0.084 ;
    END
  END din[86]
  PIN din[87]
    DIRECTION INPUT ;
    USE SIGNAL ;
    PORT
      LAYER M5 ;
        RECT  1.44 0 1.464 0.084 ;
    END
  END din[87]
  PIN din[88]
    DIRECTION INPUT ;
    USE SIGNAL ;
    PORT
      LAYER M5 ;
        RECT  1.248 0 1.272 0.084 ;
    END
  END din[88]
  PIN din[89]
    DIRECTION INPUT ;
    USE SIGNAL ;
    PORT
      LAYER M5 ;
        RECT  1.344 0 1.368 0.084 ;
    END
  END din[89]
  PIN din[8]
    DIRECTION INPUT ;
    USE SIGNAL ;
    PORT
      LAYER M5 ;
        RECT  12.096 0 12.12 0.084 ;
    END
  END din[8]
  PIN din[90]
    DIRECTION INPUT ;
    USE SIGNAL ;
    PORT
      LAYER M5 ;
        RECT  1.2 0 1.224 0.084 ;
    END
  END din[90]
  PIN din[91]
    DIRECTION INPUT ;
    USE SIGNAL ;
    PORT
      LAYER M5 ;
        RECT  1.296 0 1.32 0.084 ;
    END
  END din[91]
  PIN din[92]
    DIRECTION INPUT ;
    USE SIGNAL ;
    PORT
      LAYER M5 ;
        RECT  2.88 0 2.904 0.084 ;
    END
  END din[92]
  PIN din[93]
    DIRECTION INPUT ;
    USE SIGNAL ;
    PORT
      LAYER M5 ;
        RECT  2.256 0 2.28 0.084 ;
    END
  END din[93]
  PIN din[94]
    DIRECTION INPUT ;
    USE SIGNAL ;
    PORT
      LAYER M5 ;
        RECT  1.392 0 1.416 0.084 ;
    END
  END din[94]
  PIN din[95]
    DIRECTION INPUT ;
    USE SIGNAL ;
    PORT
      LAYER M5 ;
        RECT  1.872 0 1.896 0.084 ;
    END
  END din[95]
  PIN din[96]
    DIRECTION INPUT ;
    USE SIGNAL ;
    PORT
      LAYER M5 ;
        RECT  2.736 0 2.76 0.084 ;
    END
  END din[96]
  PIN din[97]
    DIRECTION INPUT ;
    USE SIGNAL ;
    PORT
      LAYER M5 ;
        RECT  4.752 0 4.776 0.084 ;
    END
  END din[97]
  PIN din[98]
    DIRECTION INPUT ;
    USE SIGNAL ;
    PORT
      LAYER M5 ;
        RECT  3.984 0 4.008 0.084 ;
    END
  END din[98]
  PIN din[99]
    DIRECTION INPUT ;
    USE SIGNAL ;
    PORT
      LAYER M5 ;
        RECT  3.84 0 3.864 0.084 ;
    END
  END din[99]
  PIN din[9]
    DIRECTION INPUT ;
    USE SIGNAL ;
    PORT
      LAYER M7 ;
        RECT  10.624 0 10.656 0.069 ;
    END
  END din[9]
  PIN dout[0]
    DIRECTION OUTPUT ;
    USE SIGNAL ;
    PORT
      LAYER M7 ;
        RECT  38.784 75.931 38.816 76 ;
    END
  END dout[0]
  PIN dout[100]
    DIRECTION OUTPUT ;
    USE SIGNAL ;
    PORT
      LAYER M7 ;
        RECT  3.392 75.931 3.424 76 ;
    END
  END dout[100]
  PIN dout[101]
    DIRECTION OUTPUT ;
    USE SIGNAL ;
    PORT
      LAYER M7 ;
        RECT  3.52 75.931 3.552 76 ;
    END
  END dout[101]
  PIN dout[102]
    DIRECTION OUTPUT ;
    USE SIGNAL ;
    PORT
      LAYER M5 ;
        RECT  8.496 75.916 8.52 76 ;
    END
  END dout[102]
  PIN dout[103]
    DIRECTION OUTPUT ;
    USE SIGNAL ;
    PORT
      LAYER M7 ;
        RECT  9.472 75.931 9.504 76 ;
    END
  END dout[103]
  PIN dout[104]
    DIRECTION OUTPUT ;
    USE SIGNAL ;
    PORT
      LAYER M5 ;
        RECT  8.256 75.916 8.28 76 ;
    END
  END dout[104]
  PIN dout[105]
    DIRECTION OUTPUT ;
    USE SIGNAL ;
    PORT
      LAYER M7 ;
        RECT  10.816 75.931 10.848 76 ;
    END
  END dout[105]
  PIN dout[106]
    DIRECTION OUTPUT ;
    USE SIGNAL ;
    PORT
      LAYER M5 ;
        RECT  17.568 75.916 17.592 76 ;
    END
  END dout[106]
  PIN dout[107]
    DIRECTION OUTPUT ;
    USE SIGNAL ;
    PORT
      LAYER M5 ;
        RECT  15.648 75.916 15.672 76 ;
    END
  END dout[107]
  PIN dout[108]
    DIRECTION OUTPUT ;
    USE SIGNAL ;
    PORT
      LAYER M7 ;
        RECT  2.496 75.931 2.528 76 ;
    END
  END dout[108]
  PIN dout[109]
    DIRECTION OUTPUT ;
    USE SIGNAL ;
    PORT
      LAYER M5 ;
        RECT  17.376 75.916 17.4 76 ;
    END
  END dout[109]
  PIN dout[10]
    DIRECTION OUTPUT ;
    USE SIGNAL ;
    PORT
      LAYER M5 ;
        RECT  41.856 75.916 41.88 76 ;
    END
  END dout[10]
  PIN dout[110]
    DIRECTION OUTPUT ;
    USE SIGNAL ;
    PORT
      LAYER M7 ;
        RECT  10.88 75.931 10.912 76 ;
    END
  END dout[110]
  PIN dout[111]
    DIRECTION OUTPUT ;
    USE SIGNAL ;
    PORT
      LAYER M5 ;
        RECT  14.592 75.916 14.616 76 ;
    END
  END dout[111]
  PIN dout[112]
    DIRECTION OUTPUT ;
    USE SIGNAL ;
    PORT
      LAYER M5 ;
        RECT  15.12 75.916 15.144 76 ;
    END
  END dout[112]
  PIN dout[113]
    DIRECTION OUTPUT ;
    USE SIGNAL ;
    PORT
      LAYER M5 ;
        RECT  16.128 75.916 16.152 76 ;
    END
  END dout[113]
  PIN dout[114]
    DIRECTION OUTPUT ;
    USE SIGNAL ;
    PORT
      LAYER M5 ;
        RECT  16.752 75.916 16.776 76 ;
    END
  END dout[114]
  PIN dout[115]
    DIRECTION OUTPUT ;
    USE SIGNAL ;
    PORT
      LAYER M5 ;
        RECT  20.256 75.916 20.28 76 ;
    END
  END dout[115]
  PIN dout[116]
    DIRECTION OUTPUT ;
    USE SIGNAL ;
    PORT
      LAYER M7 ;
        RECT  13.696 75.931 13.728 76 ;
    END
  END dout[116]
  PIN dout[117]
    DIRECTION OUTPUT ;
    USE SIGNAL ;
    PORT
      LAYER M5 ;
        RECT  19.392 75.916 19.416 76 ;
    END
  END dout[117]
  PIN dout[118]
    DIRECTION OUTPUT ;
    USE SIGNAL ;
    PORT
      LAYER M5 ;
        RECT  15.84 75.916 15.864 76 ;
    END
  END dout[118]
  PIN dout[119]
    DIRECTION OUTPUT ;
    USE SIGNAL ;
    PORT
      LAYER M5 ;
        RECT  34.464 75.916 34.488 76 ;
    END
  END dout[119]
  PIN dout[11]
    DIRECTION OUTPUT ;
    USE SIGNAL ;
    PORT
      LAYER M7 ;
        RECT  35.968 75.931 36 76 ;
    END
  END dout[11]
  PIN dout[120]
    DIRECTION OUTPUT ;
    USE SIGNAL ;
    PORT
      LAYER M7 ;
        RECT  23.552 75.931 23.584 76 ;
    END
  END dout[120]
  PIN dout[121]
    DIRECTION OUTPUT ;
    USE SIGNAL ;
    PORT
      LAYER M5 ;
        RECT  27.072 75.916 27.096 76 ;
    END
  END dout[121]
  PIN dout[122]
    DIRECTION OUTPUT ;
    USE SIGNAL ;
    PORT
      LAYER M7 ;
        RECT  24.448 75.931 24.48 76 ;
    END
  END dout[122]
  PIN dout[123]
    DIRECTION OUTPUT ;
    USE SIGNAL ;
    PORT
      LAYER M5 ;
        RECT  27.696 75.916 27.72 76 ;
    END
  END dout[123]
  PIN dout[124]
    DIRECTION OUTPUT ;
    USE SIGNAL ;
    PORT
      LAYER M5 ;
        RECT  31.68 75.916 31.704 76 ;
    END
  END dout[124]
  PIN dout[125]
    DIRECTION OUTPUT ;
    USE SIGNAL ;
    PORT
      LAYER M5 ;
        RECT  17.664 75.916 17.688 76 ;
    END
  END dout[125]
  PIN dout[126]
    DIRECTION OUTPUT ;
    USE SIGNAL ;
    PORT
      LAYER M5 ;
        RECT  30 75.916 30.024 76 ;
    END
  END dout[126]
  PIN dout[127]
    DIRECTION OUTPUT ;
    USE SIGNAL ;
    PORT
      LAYER M5 ;
        RECT  33.744 75.916 33.768 76 ;
    END
  END dout[127]
  PIN dout[128]
    DIRECTION OUTPUT ;
    USE SIGNAL ;
    PORT
      LAYER M5 ;
        RECT  47.472 75.916 47.496 76 ;
    END
  END dout[128]
  PIN dout[129]
    DIRECTION OUTPUT ;
    USE SIGNAL ;
    PORT
      LAYER M5 ;
        RECT  45.984 75.916 46.008 76 ;
    END
  END dout[129]
  PIN dout[12]
    DIRECTION OUTPUT ;
    USE SIGNAL ;
    PORT
      LAYER M7 ;
        RECT  42.304 75.931 42.336 76 ;
    END
  END dout[12]
  PIN dout[130]
    DIRECTION OUTPUT ;
    USE SIGNAL ;
    PORT
      LAYER M5 ;
        RECT  45.264 75.916 45.288 76 ;
    END
  END dout[130]
  PIN dout[131]
    DIRECTION OUTPUT ;
    USE SIGNAL ;
    PORT
      LAYER M5 ;
        RECT  46.176 75.916 46.2 76 ;
    END
  END dout[131]
  PIN dout[132]
    DIRECTION OUTPUT ;
    USE SIGNAL ;
    PORT
      LAYER M7 ;
        RECT  41.6 75.931 41.632 76 ;
    END
  END dout[132]
  PIN dout[133]
    DIRECTION OUTPUT ;
    USE SIGNAL ;
    PORT
      LAYER M5 ;
        RECT  43.68 75.916 43.704 76 ;
    END
  END dout[133]
  PIN dout[134]
    DIRECTION OUTPUT ;
    USE SIGNAL ;
    PORT
      LAYER M5 ;
        RECT  45.12 75.916 45.144 76 ;
    END
  END dout[134]
  PIN dout[135]
    DIRECTION OUTPUT ;
    USE SIGNAL ;
    PORT
      LAYER M5 ;
        RECT  43.392 75.916 43.416 76 ;
    END
  END dout[135]
  PIN dout[136]
    DIRECTION OUTPUT ;
    USE SIGNAL ;
    PORT
      LAYER M5 ;
        RECT  42.912 75.916 42.936 76 ;
    END
  END dout[136]
  PIN dout[137]
    DIRECTION OUTPUT ;
    USE SIGNAL ;
    PORT
      LAYER M5 ;
        RECT  43.872 75.916 43.896 76 ;
    END
  END dout[137]
  PIN dout[138]
    DIRECTION OUTPUT ;
    USE SIGNAL ;
    PORT
      LAYER M5 ;
        RECT  43.776 75.916 43.8 76 ;
    END
  END dout[138]
  PIN dout[139]
    DIRECTION OUTPUT ;
    USE SIGNAL ;
    PORT
      LAYER M7 ;
        RECT  40.896 75.931 40.928 76 ;
    END
  END dout[139]
  PIN dout[13]
    DIRECTION OUTPUT ;
    USE SIGNAL ;
    PORT
      LAYER M7 ;
        RECT  41.408 75.931 41.44 76 ;
    END
  END dout[13]
  PIN dout[140]
    DIRECTION OUTPUT ;
    USE SIGNAL ;
    PORT
      LAYER M5 ;
        RECT  43.248 75.916 43.272 76 ;
    END
  END dout[140]
  PIN dout[141]
    DIRECTION OUTPUT ;
    USE SIGNAL ;
    PORT
      LAYER M5 ;
        RECT  45.936 75.916 45.96 76 ;
    END
  END dout[141]
  PIN dout[142]
    DIRECTION OUTPUT ;
    USE SIGNAL ;
    PORT
      LAYER M5 ;
        RECT  41.52 75.916 41.544 76 ;
    END
  END dout[142]
  PIN dout[143]
    DIRECTION OUTPUT ;
    USE SIGNAL ;
    PORT
      LAYER M7 ;
        RECT  37.696 75.931 37.728 76 ;
    END
  END dout[143]
  PIN dout[144]
    DIRECTION OUTPUT ;
    USE SIGNAL ;
    PORT
      LAYER M5 ;
        RECT  43.008 75.916 43.032 76 ;
    END
  END dout[144]
  PIN dout[145]
    DIRECTION OUTPUT ;
    USE SIGNAL ;
    PORT
      LAYER M5 ;
        RECT  44.448 75.916 44.472 76 ;
    END
  END dout[145]
  PIN dout[146]
    DIRECTION OUTPUT ;
    USE SIGNAL ;
    PORT
      LAYER M5 ;
        RECT  43.296 75.916 43.32 76 ;
    END
  END dout[146]
  PIN dout[147]
    DIRECTION OUTPUT ;
    USE SIGNAL ;
    PORT
      LAYER M5 ;
        RECT  44.88 75.916 44.904 76 ;
    END
  END dout[147]
  PIN dout[148]
    DIRECTION OUTPUT ;
    USE SIGNAL ;
    PORT
      LAYER M5 ;
        RECT  46.56 75.916 46.584 76 ;
    END
  END dout[148]
  PIN dout[149]
    DIRECTION OUTPUT ;
    USE SIGNAL ;
    PORT
      LAYER M5 ;
        RECT  46.464 75.916 46.488 76 ;
    END
  END dout[149]
  PIN dout[14]
    DIRECTION OUTPUT ;
    USE SIGNAL ;
    PORT
      LAYER M7 ;
        RECT  38.72 75.931 38.752 76 ;
    END
  END dout[14]
  PIN dout[150]
    DIRECTION OUTPUT ;
    USE SIGNAL ;
    PORT
      LAYER M5 ;
        RECT  44.592 75.916 44.616 76 ;
    END
  END dout[150]
  PIN dout[151]
    DIRECTION OUTPUT ;
    USE SIGNAL ;
    PORT
      LAYER M5 ;
        RECT  47.184 75.916 47.208 76 ;
    END
  END dout[151]
  PIN dout[152]
    DIRECTION OUTPUT ;
    USE SIGNAL ;
    PORT
      LAYER M5 ;
        RECT  44.928 75.916 44.952 76 ;
    END
  END dout[152]
  PIN dout[153]
    DIRECTION OUTPUT ;
    USE SIGNAL ;
    PORT
      LAYER M5 ;
        RECT  45.696 75.916 45.72 76 ;
    END
  END dout[153]
  PIN dout[154]
    DIRECTION OUTPUT ;
    USE SIGNAL ;
    PORT
      LAYER M5 ;
        RECT  44.112 75.916 44.136 76 ;
    END
  END dout[154]
  PIN dout[155]
    DIRECTION OUTPUT ;
    USE SIGNAL ;
    PORT
      LAYER M5 ;
        RECT  41.616 75.916 41.64 76 ;
    END
  END dout[155]
  PIN dout[156]
    DIRECTION OUTPUT ;
    USE SIGNAL ;
    PORT
      LAYER M7 ;
        RECT  39.616 75.931 39.648 76 ;
    END
  END dout[156]
  PIN dout[157]
    DIRECTION OUTPUT ;
    USE SIGNAL ;
    PORT
      LAYER M5 ;
        RECT  45.408 75.916 45.432 76 ;
    END
  END dout[157]
  PIN dout[158]
    DIRECTION OUTPUT ;
    USE SIGNAL ;
    PORT
      LAYER M5 ;
        RECT  41.76 75.916 41.784 76 ;
    END
  END dout[158]
  PIN dout[159]
    DIRECTION OUTPUT ;
    USE SIGNAL ;
    PORT
      LAYER M5 ;
        RECT  31.776 75.916 31.8 76 ;
    END
  END dout[159]
  PIN dout[15]
    DIRECTION OUTPUT ;
    USE SIGNAL ;
    PORT
      LAYER M7 ;
        RECT  38.4 75.931 38.432 76 ;
    END
  END dout[15]
  PIN dout[160]
    DIRECTION OUTPUT ;
    USE SIGNAL ;
    PORT
      LAYER M7 ;
        RECT  36.736 75.931 36.768 76 ;
    END
  END dout[160]
  PIN dout[161]
    DIRECTION OUTPUT ;
    USE SIGNAL ;
    PORT
      LAYER M5 ;
        RECT  46.272 75.916 46.296 76 ;
    END
  END dout[161]
  PIN dout[162]
    DIRECTION OUTPUT ;
    USE SIGNAL ;
    PORT
      LAYER M5 ;
        RECT  44.016 75.916 44.04 76 ;
    END
  END dout[162]
  PIN dout[163]
    DIRECTION OUTPUT ;
    USE SIGNAL ;
    PORT
      LAYER M5 ;
        RECT  47.424 75.916 47.448 76 ;
    END
  END dout[163]
  PIN dout[164]
    DIRECTION OUTPUT ;
    USE SIGNAL ;
    PORT
      LAYER M5 ;
        RECT  44.208 75.916 44.232 76 ;
    END
  END dout[164]
  PIN dout[165]
    DIRECTION OUTPUT ;
    USE SIGNAL ;
    PORT
      LAYER M5 ;
        RECT  45.456 75.916 45.48 76 ;
    END
  END dout[165]
  PIN dout[166]
    DIRECTION OUTPUT ;
    USE SIGNAL ;
    PORT
      LAYER M7 ;
        RECT  37.888 75.931 37.92 76 ;
    END
  END dout[166]
  PIN dout[167]
    DIRECTION OUTPUT ;
    USE SIGNAL ;
    PORT
      LAYER M5 ;
        RECT  43.152 75.916 43.176 76 ;
    END
  END dout[167]
  PIN dout[168]
    DIRECTION OUTPUT ;
    USE SIGNAL ;
    PORT
      LAYER M7 ;
        RECT  40.768 75.931 40.8 76 ;
    END
  END dout[168]
  PIN dout[169]
    DIRECTION OUTPUT ;
    USE SIGNAL ;
    PORT
      LAYER M7 ;
        RECT  41.536 75.931 41.568 76 ;
    END
  END dout[169]
  PIN dout[16]
    DIRECTION OUTPUT ;
    USE SIGNAL ;
    PORT
      LAYER M5 ;
        RECT  35.808 75.916 35.832 76 ;
    END
  END dout[16]
  PIN dout[170]
    DIRECTION OUTPUT ;
    USE SIGNAL ;
    PORT
      LAYER M7 ;
        RECT  40.512 75.931 40.544 76 ;
    END
  END dout[170]
  PIN dout[171]
    DIRECTION OUTPUT ;
    USE SIGNAL ;
    PORT
      LAYER M5 ;
        RECT  45.216 75.916 45.24 76 ;
    END
  END dout[171]
  PIN dout[172]
    DIRECTION OUTPUT ;
    USE SIGNAL ;
    PORT
      LAYER M5 ;
        RECT  43.584 75.916 43.608 76 ;
    END
  END dout[172]
  PIN dout[173]
    DIRECTION OUTPUT ;
    USE SIGNAL ;
    PORT
      LAYER M7 ;
        RECT  22.784 75.931 22.816 76 ;
    END
  END dout[173]
  PIN dout[174]
    DIRECTION OUTPUT ;
    USE SIGNAL ;
    PORT
      LAYER M5 ;
        RECT  41.904 75.916 41.928 76 ;
    END
  END dout[174]
  PIN dout[175]
    DIRECTION OUTPUT ;
    USE SIGNAL ;
    PORT
      LAYER M7 ;
        RECT  36.096 75.931 36.128 76 ;
    END
  END dout[175]
  PIN dout[176]
    DIRECTION OUTPUT ;
    USE SIGNAL ;
    PORT
      LAYER M5 ;
        RECT  35.952 75.916 35.976 76 ;
    END
  END dout[176]
  PIN dout[177]
    DIRECTION OUTPUT ;
    USE SIGNAL ;
    PORT
      LAYER M5 ;
        RECT  47.232 75.916 47.256 76 ;
    END
  END dout[177]
  PIN dout[178]
    DIRECTION OUTPUT ;
    USE SIGNAL ;
    PORT
      LAYER M5 ;
        RECT  43.488 75.916 43.512 76 ;
    END
  END dout[178]
  PIN dout[179]
    DIRECTION OUTPUT ;
    USE SIGNAL ;
    PORT
      LAYER M7 ;
        RECT  41.856 75.931 41.888 76 ;
    END
  END dout[179]
  PIN dout[17]
    DIRECTION OUTPUT ;
    USE SIGNAL ;
    PORT
      LAYER M7 ;
        RECT  40.704 75.931 40.736 76 ;
    END
  END dout[17]
  PIN dout[180]
    DIRECTION OUTPUT ;
    USE SIGNAL ;
    PORT
      LAYER M7 ;
        RECT  37.248 75.931 37.28 76 ;
    END
  END dout[180]
  PIN dout[181]
    DIRECTION OUTPUT ;
    USE SIGNAL ;
    PORT
      LAYER M5 ;
        RECT  42.192 75.916 42.216 76 ;
    END
  END dout[181]
  PIN dout[182]
    DIRECTION OUTPUT ;
    USE SIGNAL ;
    PORT
      LAYER M7 ;
        RECT  41.344 75.931 41.376 76 ;
    END
  END dout[182]
  PIN dout[183]
    DIRECTION OUTPUT ;
    USE SIGNAL ;
    PORT
      LAYER M5 ;
        RECT  42.432 75.916 42.456 76 ;
    END
  END dout[183]
  PIN dout[184]
    DIRECTION OUTPUT ;
    USE SIGNAL ;
    PORT
      LAYER M7 ;
        RECT  38.144 75.931 38.176 76 ;
    END
  END dout[184]
  PIN dout[185]
    DIRECTION OUTPUT ;
    USE SIGNAL ;
    PORT
      LAYER M5 ;
        RECT  45.792 75.916 45.816 76 ;
    END
  END dout[185]
  PIN dout[186]
    DIRECTION OUTPUT ;
    USE SIGNAL ;
    PORT
      LAYER M5 ;
        RECT  46.8 75.916 46.824 76 ;
    END
  END dout[186]
  PIN dout[187]
    DIRECTION OUTPUT ;
    USE SIGNAL ;
    PORT
      LAYER M5 ;
        RECT  47.04 75.916 47.064 76 ;
    END
  END dout[187]
  PIN dout[188]
    DIRECTION OUTPUT ;
    USE SIGNAL ;
    PORT
      LAYER M5 ;
        RECT  46.704 75.916 46.728 76 ;
    END
  END dout[188]
  PIN dout[189]
    DIRECTION OUTPUT ;
    USE SIGNAL ;
    PORT
      LAYER M5 ;
        RECT  46.752 75.916 46.776 76 ;
    END
  END dout[189]
  PIN dout[18]
    DIRECTION OUTPUT ;
    USE SIGNAL ;
    PORT
      LAYER M5 ;
        RECT  32.352 75.916 32.376 76 ;
    END
  END dout[18]
  PIN dout[190]
    DIRECTION OUTPUT ;
    USE SIGNAL ;
    PORT
      LAYER M5 ;
        RECT  46.128 75.916 46.152 76 ;
    END
  END dout[190]
  PIN dout[191]
    DIRECTION OUTPUT ;
    USE SIGNAL ;
    PORT
      LAYER M5 ;
        RECT  45.6 75.916 45.624 76 ;
    END
  END dout[191]
  PIN dout[192]
    DIRECTION OUTPUT ;
    USE SIGNAL ;
    PORT
      LAYER M5 ;
        RECT  69.216 75.916 69.24 76 ;
    END
  END dout[192]
  PIN dout[193]
    DIRECTION OUTPUT ;
    USE SIGNAL ;
    PORT
      LAYER M5 ;
        RECT  64.464 75.916 64.488 76 ;
    END
  END dout[193]
  PIN dout[194]
    DIRECTION OUTPUT ;
    USE SIGNAL ;
    PORT
      LAYER M5 ;
        RECT  64.56 75.916 64.584 76 ;
    END
  END dout[194]
  PIN dout[195]
    DIRECTION OUTPUT ;
    USE SIGNAL ;
    PORT
      LAYER M5 ;
        RECT  64.704 75.916 64.728 76 ;
    END
  END dout[195]
  PIN dout[196]
    DIRECTION OUTPUT ;
    USE SIGNAL ;
    PORT
      LAYER M5 ;
        RECT  67.344 75.916 67.368 76 ;
    END
  END dout[196]
  PIN dout[197]
    DIRECTION OUTPUT ;
    USE SIGNAL ;
    PORT
      LAYER M5 ;
        RECT  68.592 75.916 68.616 76 ;
    END
  END dout[197]
  PIN dout[198]
    DIRECTION OUTPUT ;
    USE SIGNAL ;
    PORT
      LAYER M5 ;
        RECT  67.776 75.916 67.8 76 ;
    END
  END dout[198]
  PIN dout[199]
    DIRECTION OUTPUT ;
    USE SIGNAL ;
    PORT
      LAYER M5 ;
        RECT  68.64 75.916 68.664 76 ;
    END
  END dout[199]
  PIN dout[19]
    DIRECTION OUTPUT ;
    USE SIGNAL ;
    PORT
      LAYER M7 ;
        RECT  40.96 75.931 40.992 76 ;
    END
  END dout[19]
  PIN dout[1]
    DIRECTION OUTPUT ;
    USE SIGNAL ;
    PORT
      LAYER M5 ;
        RECT  25.248 75.916 25.272 76 ;
    END
  END dout[1]
  PIN dout[200]
    DIRECTION OUTPUT ;
    USE SIGNAL ;
    PORT
      LAYER M5 ;
        RECT  69.168 75.916 69.192 76 ;
    END
  END dout[200]
  PIN dout[201]
    DIRECTION OUTPUT ;
    USE SIGNAL ;
    PORT
      LAYER M5 ;
        RECT  68.544 75.916 68.568 76 ;
    END
  END dout[201]
  PIN dout[202]
    DIRECTION OUTPUT ;
    USE SIGNAL ;
    PORT
      LAYER M5 ;
        RECT  68.208 75.916 68.232 76 ;
    END
  END dout[202]
  PIN dout[203]
    DIRECTION OUTPUT ;
    USE SIGNAL ;
    PORT
      LAYER M5 ;
        RECT  68.688 75.916 68.712 76 ;
    END
  END dout[203]
  PIN dout[204]
    DIRECTION OUTPUT ;
    USE SIGNAL ;
    PORT
      LAYER M5 ;
        RECT  65.568 75.916 65.592 76 ;
    END
  END dout[204]
  PIN dout[205]
    DIRECTION OUTPUT ;
    USE SIGNAL ;
    PORT
      LAYER M5 ;
        RECT  65.136 75.916 65.16 76 ;
    END
  END dout[205]
  PIN dout[206]
    DIRECTION OUTPUT ;
    USE SIGNAL ;
    PORT
      LAYER M5 ;
        RECT  64.608 75.916 64.632 76 ;
    END
  END dout[206]
  PIN dout[207]
    DIRECTION OUTPUT ;
    USE SIGNAL ;
    PORT
      LAYER M5 ;
        RECT  66.192 75.916 66.216 76 ;
    END
  END dout[207]
  PIN dout[208]
    DIRECTION OUTPUT ;
    USE SIGNAL ;
    PORT
      LAYER M5 ;
        RECT  67.44 75.916 67.464 76 ;
    END
  END dout[208]
  PIN dout[209]
    DIRECTION OUTPUT ;
    USE SIGNAL ;
    PORT
      LAYER M5 ;
        RECT  66.24 75.916 66.264 76 ;
    END
  END dout[209]
  PIN dout[20]
    DIRECTION OUTPUT ;
    USE SIGNAL ;
    PORT
      LAYER M5 ;
        RECT  42.672 75.916 42.696 76 ;
    END
  END dout[20]
  PIN dout[210]
    DIRECTION OUTPUT ;
    USE SIGNAL ;
    PORT
      LAYER M5 ;
        RECT  65.52 75.916 65.544 76 ;
    END
  END dout[210]
  PIN dout[211]
    DIRECTION OUTPUT ;
    USE SIGNAL ;
    PORT
      LAYER M5 ;
        RECT  67.2 75.916 67.224 76 ;
    END
  END dout[211]
  PIN dout[212]
    DIRECTION OUTPUT ;
    USE SIGNAL ;
    PORT
      LAYER M5 ;
        RECT  67.584 75.916 67.608 76 ;
    END
  END dout[212]
  PIN dout[213]
    DIRECTION OUTPUT ;
    USE SIGNAL ;
    PORT
      LAYER M5 ;
        RECT  66.48 75.916 66.504 76 ;
    END
  END dout[213]
  PIN dout[214]
    DIRECTION OUTPUT ;
    USE SIGNAL ;
    PORT
      LAYER M5 ;
        RECT  65.328 75.916 65.352 76 ;
    END
  END dout[214]
  PIN dout[215]
    DIRECTION OUTPUT ;
    USE SIGNAL ;
    PORT
      LAYER M5 ;
        RECT  63.936 75.916 63.96 76 ;
    END
  END dout[215]
  PIN dout[216]
    DIRECTION OUTPUT ;
    USE SIGNAL ;
    PORT
      LAYER M5 ;
        RECT  67.008 75.916 67.032 76 ;
    END
  END dout[216]
  PIN dout[217]
    DIRECTION OUTPUT ;
    USE SIGNAL ;
    PORT
      LAYER M5 ;
        RECT  64.656 75.916 64.68 76 ;
    END
  END dout[217]
  PIN dout[218]
    DIRECTION OUTPUT ;
    USE SIGNAL ;
    PORT
      LAYER M5 ;
        RECT  66.288 75.916 66.312 76 ;
    END
  END dout[218]
  PIN dout[219]
    DIRECTION OUTPUT ;
    USE SIGNAL ;
    PORT
      LAYER M7 ;
        RECT  60.288 75.931 60.32 76 ;
    END
  END dout[219]
  PIN dout[21]
    DIRECTION OUTPUT ;
    USE SIGNAL ;
    PORT
      LAYER M7 ;
        RECT  36.288 75.931 36.32 76 ;
    END
  END dout[21]
  PIN dout[220]
    DIRECTION OUTPUT ;
    USE SIGNAL ;
    PORT
      LAYER M5 ;
        RECT  64.176 75.916 64.2 76 ;
    END
  END dout[220]
  PIN dout[221]
    DIRECTION OUTPUT ;
    USE SIGNAL ;
    PORT
      LAYER M7 ;
        RECT  58.944 75.931 58.976 76 ;
    END
  END dout[221]
  PIN dout[222]
    DIRECTION OUTPUT ;
    USE SIGNAL ;
    PORT
      LAYER M7 ;
        RECT  63.104 75.931 63.136 76 ;
    END
  END dout[222]
  PIN dout[223]
    DIRECTION OUTPUT ;
    USE SIGNAL ;
    PORT
      LAYER M5 ;
        RECT  66.96 75.916 66.984 76 ;
    END
  END dout[223]
  PIN dout[224]
    DIRECTION OUTPUT ;
    USE SIGNAL ;
    PORT
      LAYER M7 ;
        RECT  61.952 75.931 61.984 76 ;
    END
  END dout[224]
  PIN dout[225]
    DIRECTION OUTPUT ;
    USE SIGNAL ;
    PORT
      LAYER M5 ;
        RECT  64.224 75.916 64.248 76 ;
    END
  END dout[225]
  PIN dout[226]
    DIRECTION OUTPUT ;
    USE SIGNAL ;
    PORT
      LAYER M5 ;
        RECT  64.848 75.916 64.872 76 ;
    END
  END dout[226]
  PIN dout[227]
    DIRECTION OUTPUT ;
    USE SIGNAL ;
    PORT
      LAYER M5 ;
        RECT  65.088 75.916 65.112 76 ;
    END
  END dout[227]
  PIN dout[228]
    DIRECTION OUTPUT ;
    USE SIGNAL ;
    PORT
      LAYER M5 ;
        RECT  65.808 75.916 65.832 76 ;
    END
  END dout[228]
  PIN dout[229]
    DIRECTION OUTPUT ;
    USE SIGNAL ;
    PORT
      LAYER M5 ;
        RECT  65.952 75.916 65.976 76 ;
    END
  END dout[229]
  PIN dout[22]
    DIRECTION OUTPUT ;
    USE SIGNAL ;
    PORT
      LAYER M5 ;
        RECT  31.104 75.916 31.128 76 ;
    END
  END dout[22]
  PIN dout[230]
    DIRECTION OUTPUT ;
    USE SIGNAL ;
    PORT
      LAYER M5 ;
        RECT  65.76 75.916 65.784 76 ;
    END
  END dout[230]
  PIN dout[231]
    DIRECTION OUTPUT ;
    USE SIGNAL ;
    PORT
      LAYER M5 ;
        RECT  68.304 75.916 68.328 76 ;
    END
  END dout[231]
  PIN dout[232]
    DIRECTION OUTPUT ;
    USE SIGNAL ;
    PORT
      LAYER M5 ;
        RECT  65.28 75.916 65.304 76 ;
    END
  END dout[232]
  PIN dout[233]
    DIRECTION OUTPUT ;
    USE SIGNAL ;
    PORT
      LAYER M7 ;
        RECT  62.784 75.931 62.816 76 ;
    END
  END dout[233]
  PIN dout[234]
    DIRECTION OUTPUT ;
    USE SIGNAL ;
    PORT
      LAYER M7 ;
        RECT  63.296 75.931 63.328 76 ;
    END
  END dout[234]
  PIN dout[235]
    DIRECTION OUTPUT ;
    USE SIGNAL ;
    PORT
      LAYER M7 ;
        RECT  62.592 75.931 62.624 76 ;
    END
  END dout[235]
  PIN dout[236]
    DIRECTION OUTPUT ;
    USE SIGNAL ;
    PORT
      LAYER M5 ;
        RECT  64.896 75.916 64.92 76 ;
    END
  END dout[236]
  PIN dout[237]
    DIRECTION OUTPUT ;
    USE SIGNAL ;
    PORT
      LAYER M7 ;
        RECT  60.48 75.931 60.512 76 ;
    END
  END dout[237]
  PIN dout[238]
    DIRECTION OUTPUT ;
    USE SIGNAL ;
    PORT
      LAYER M7 ;
        RECT  59.712 75.931 59.744 76 ;
    END
  END dout[238]
  PIN dout[239]
    DIRECTION OUTPUT ;
    USE SIGNAL ;
    PORT
      LAYER M7 ;
        RECT  61.504 75.931 61.536 76 ;
    END
  END dout[239]
  PIN dout[23]
    DIRECTION OUTPUT ;
    USE SIGNAL ;
    PORT
      LAYER M5 ;
        RECT  30.384 75.916 30.408 76 ;
    END
  END dout[23]
  PIN dout[240]
    DIRECTION OUTPUT ;
    USE SIGNAL ;
    PORT
      LAYER M7 ;
        RECT  59.968 75.931 60 76 ;
    END
  END dout[240]
  PIN dout[241]
    DIRECTION OUTPUT ;
    USE SIGNAL ;
    PORT
      LAYER M5 ;
        RECT  64.992 75.916 65.016 76 ;
    END
  END dout[241]
  PIN dout[242]
    DIRECTION OUTPUT ;
    USE SIGNAL ;
    PORT
      LAYER M5 ;
        RECT  66.912 75.916 66.936 76 ;
    END
  END dout[242]
  PIN dout[243]
    DIRECTION OUTPUT ;
    USE SIGNAL ;
    PORT
      LAYER M5 ;
        RECT  58.08 75.916 58.104 76 ;
    END
  END dout[243]
  PIN dout[244]
    DIRECTION OUTPUT ;
    USE SIGNAL ;
    PORT
      LAYER M5 ;
        RECT  58.416 75.916 58.44 76 ;
    END
  END dout[244]
  PIN dout[245]
    DIRECTION OUTPUT ;
    USE SIGNAL ;
    PORT
      LAYER M5 ;
        RECT  64.416 75.916 64.44 76 ;
    END
  END dout[245]
  PIN dout[246]
    DIRECTION OUTPUT ;
    USE SIGNAL ;
    PORT
      LAYER M5 ;
        RECT  67.92 75.916 67.944 76 ;
    END
  END dout[246]
  PIN dout[247]
    DIRECTION OUTPUT ;
    USE SIGNAL ;
    PORT
      LAYER M5 ;
        RECT  68.16 75.916 68.184 76 ;
    END
  END dout[247]
  PIN dout[248]
    DIRECTION OUTPUT ;
    USE SIGNAL ;
    PORT
      LAYER M5 ;
        RECT  46.224 75.916 46.248 76 ;
    END
  END dout[248]
  PIN dout[249]
    DIRECTION OUTPUT ;
    USE SIGNAL ;
    PORT
      LAYER M5 ;
        RECT  67.296 75.916 67.32 76 ;
    END
  END dout[249]
  PIN dout[24]
    DIRECTION OUTPUT ;
    USE SIGNAL ;
    PORT
      LAYER M7 ;
        RECT  36.224 75.931 36.256 76 ;
    END
  END dout[24]
  PIN dout[250]
    DIRECTION OUTPUT ;
    USE SIGNAL ;
    PORT
      LAYER M5 ;
        RECT  68.016 75.916 68.04 76 ;
    END
  END dout[250]
  PIN dout[251]
    DIRECTION OUTPUT ;
    USE SIGNAL ;
    PORT
      LAYER M5 ;
        RECT  68.4 75.916 68.424 76 ;
    END
  END dout[251]
  PIN dout[252]
    DIRECTION OUTPUT ;
    USE SIGNAL ;
    PORT
      LAYER M5 ;
        RECT  65.184 75.916 65.208 76 ;
    END
  END dout[252]
  PIN dout[253]
    DIRECTION OUTPUT ;
    USE SIGNAL ;
    PORT
      LAYER M5 ;
        RECT  66.72 75.916 66.744 76 ;
    END
  END dout[253]
  PIN dout[254]
    DIRECTION OUTPUT ;
    USE SIGNAL ;
    PORT
      LAYER M5 ;
        RECT  67.536 75.916 67.56 76 ;
    END
  END dout[254]
  PIN dout[255]
    DIRECTION OUTPUT ;
    USE SIGNAL ;
    PORT
      LAYER M5 ;
        RECT  65.664 75.916 65.688 76 ;
    END
  END dout[255]
  PIN dout[256]
    DIRECTION OUTPUT ;
    USE SIGNAL ;
    PORT
      LAYER M5 ;
        RECT  64.8 75.916 64.824 76 ;
    END
  END dout[256]
  PIN dout[257]
    DIRECTION OUTPUT ;
    USE SIGNAL ;
    PORT
      LAYER M7 ;
        RECT  51.84 75.931 51.872 76 ;
    END
  END dout[257]
  PIN dout[258]
    DIRECTION OUTPUT ;
    USE SIGNAL ;
    PORT
      LAYER M5 ;
        RECT  54.096 75.916 54.12 76 ;
    END
  END dout[258]
  PIN dout[259]
    DIRECTION OUTPUT ;
    USE SIGNAL ;
    PORT
      LAYER M5 ;
        RECT  68.736 75.916 68.76 76 ;
    END
  END dout[259]
  PIN dout[25]
    DIRECTION OUTPUT ;
    USE SIGNAL ;
    PORT
      LAYER M7 ;
        RECT  22.4 75.931 22.432 76 ;
    END
  END dout[25]
  PIN dout[260]
    DIRECTION OUTPUT ;
    USE SIGNAL ;
    PORT
      LAYER M7 ;
        RECT  49.024 75.931 49.056 76 ;
    END
  END dout[260]
  PIN dout[261]
    DIRECTION OUTPUT ;
    USE SIGNAL ;
    PORT
      LAYER M7 ;
        RECT  51.264 75.931 51.296 76 ;
    END
  END dout[261]
  PIN dout[262]
    DIRECTION OUTPUT ;
    USE SIGNAL ;
    PORT
      LAYER M7 ;
        RECT  49.472 75.931 49.504 76 ;
    END
  END dout[262]
  PIN dout[263]
    DIRECTION OUTPUT ;
    USE SIGNAL ;
    PORT
      LAYER M7 ;
        RECT  48.448 75.931 48.48 76 ;
    END
  END dout[263]
  PIN dout[264]
    DIRECTION OUTPUT ;
    USE SIGNAL ;
    PORT
      LAYER M5 ;
        RECT  66.528 75.916 66.552 76 ;
    END
  END dout[264]
  PIN dout[265]
    DIRECTION OUTPUT ;
    USE SIGNAL ;
    PORT
      LAYER M7 ;
        RECT  50.88 75.931 50.912 76 ;
    END
  END dout[265]
  PIN dout[266]
    DIRECTION OUTPUT ;
    USE SIGNAL ;
    PORT
      LAYER M5 ;
        RECT  68.784 75.916 68.808 76 ;
    END
  END dout[266]
  PIN dout[267]
    DIRECTION OUTPUT ;
    USE SIGNAL ;
    PORT
      LAYER M5 ;
        RECT  57.792 75.916 57.816 76 ;
    END
  END dout[267]
  PIN dout[268]
    DIRECTION OUTPUT ;
    USE SIGNAL ;
    PORT
      LAYER M7 ;
        RECT  48.576 75.931 48.608 76 ;
    END
  END dout[268]
  PIN dout[269]
    DIRECTION OUTPUT ;
    USE SIGNAL ;
    PORT
      LAYER M7 ;
        RECT  48.896 75.931 48.928 76 ;
    END
  END dout[269]
  PIN dout[26]
    DIRECTION OUTPUT ;
    USE SIGNAL ;
    PORT
      LAYER M5 ;
        RECT  28.368 75.916 28.392 76 ;
    END
  END dout[26]
  PIN dout[270]
    DIRECTION OUTPUT ;
    USE SIGNAL ;
    PORT
      LAYER M5 ;
        RECT  47.376 75.916 47.4 76 ;
    END
  END dout[270]
  PIN dout[271]
    DIRECTION OUTPUT ;
    USE SIGNAL ;
    PORT
      LAYER M7 ;
        RECT  49.6 75.931 49.632 76 ;
    END
  END dout[271]
  PIN dout[272]
    DIRECTION OUTPUT ;
    USE SIGNAL ;
    PORT
      LAYER M7 ;
        RECT  51.392 75.931 51.424 76 ;
    END
  END dout[272]
  PIN dout[273]
    DIRECTION OUTPUT ;
    USE SIGNAL ;
    PORT
      LAYER M5 ;
        RECT  52.56 75.916 52.584 76 ;
    END
  END dout[273]
  PIN dout[274]
    DIRECTION OUTPUT ;
    USE SIGNAL ;
    PORT
      LAYER M7 ;
        RECT  49.344 75.931 49.376 76 ;
    END
  END dout[274]
  PIN dout[275]
    DIRECTION OUTPUT ;
    USE SIGNAL ;
    PORT
      LAYER M5 ;
        RECT  52.608 75.916 52.632 76 ;
    END
  END dout[275]
  PIN dout[276]
    DIRECTION OUTPUT ;
    USE SIGNAL ;
    PORT
      LAYER M7 ;
        RECT  49.216 75.931 49.248 76 ;
    END
  END dout[276]
  PIN dout[277]
    DIRECTION OUTPUT ;
    USE SIGNAL ;
    PORT
      LAYER M5 ;
        RECT  53.52 75.916 53.544 76 ;
    END
  END dout[277]
  PIN dout[278]
    DIRECTION OUTPUT ;
    USE SIGNAL ;
    PORT
      LAYER M5 ;
        RECT  63.648 75.916 63.672 76 ;
    END
  END dout[278]
  PIN dout[279]
    DIRECTION OUTPUT ;
    USE SIGNAL ;
    PORT
      LAYER M5 ;
        RECT  64.08 75.916 64.104 76 ;
    END
  END dout[279]
  PIN dout[27]
    DIRECTION OUTPUT ;
    USE SIGNAL ;
    PORT
      LAYER M5 ;
        RECT  33.888 75.916 33.912 76 ;
    END
  END dout[27]
  PIN dout[280]
    DIRECTION OUTPUT ;
    USE SIGNAL ;
    PORT
      LAYER M7 ;
        RECT  38.848 75.931 38.88 76 ;
    END
  END dout[280]
  PIN dout[281]
    DIRECTION OUTPUT ;
    USE SIGNAL ;
    PORT
      LAYER M5 ;
        RECT  25.296 75.916 25.32 76 ;
    END
  END dout[281]
  PIN dout[282]
    DIRECTION OUTPUT ;
    USE SIGNAL ;
    PORT
      LAYER M7 ;
        RECT  42.24 75.931 42.272 76 ;
    END
  END dout[282]
  PIN dout[283]
    DIRECTION OUTPUT ;
    USE SIGNAL ;
    PORT
      LAYER M7 ;
        RECT  38.976 75.931 39.008 76 ;
    END
  END dout[283]
  PIN dout[284]
    DIRECTION OUTPUT ;
    USE SIGNAL ;
    PORT
      LAYER M7 ;
        RECT  37.824 75.931 37.856 76 ;
    END
  END dout[284]
  PIN dout[285]
    DIRECTION OUTPUT ;
    USE SIGNAL ;
    PORT
      LAYER M7 ;
        RECT  36.544 75.931 36.576 76 ;
    END
  END dout[285]
  PIN dout[286]
    DIRECTION OUTPUT ;
    USE SIGNAL ;
    PORT
      LAYER M7 ;
        RECT  37.76 75.931 37.792 76 ;
    END
  END dout[286]
  PIN dout[287]
    DIRECTION OUTPUT ;
    USE SIGNAL ;
    PORT
      LAYER M5 ;
        RECT  41.424 75.916 41.448 76 ;
    END
  END dout[287]
  PIN dout[288]
    DIRECTION OUTPUT ;
    USE SIGNAL ;
    PORT
      LAYER M5 ;
        RECT  26.928 75.916 26.952 76 ;
    END
  END dout[288]
  PIN dout[289]
    DIRECTION OUTPUT ;
    USE SIGNAL ;
    PORT
      LAYER M5 ;
        RECT  8.112 75.916 8.136 76 ;
    END
  END dout[289]
  PIN dout[28]
    DIRECTION OUTPUT ;
    USE SIGNAL ;
    PORT
      LAYER M5 ;
        RECT  19.68 75.916 19.704 76 ;
    END
  END dout[28]
  PIN dout[290]
    DIRECTION OUTPUT ;
    USE SIGNAL ;
    PORT
      LAYER M5 ;
        RECT  41.712 75.916 41.736 76 ;
    END
  END dout[290]
  PIN dout[291]
    DIRECTION OUTPUT ;
    USE SIGNAL ;
    PORT
      LAYER M7 ;
        RECT  38.08 75.931 38.112 76 ;
    END
  END dout[291]
  PIN dout[292]
    DIRECTION OUTPUT ;
    USE SIGNAL ;
    PORT
      LAYER M7 ;
        RECT  41.664 75.931 41.696 76 ;
    END
  END dout[292]
  PIN dout[293]
    DIRECTION OUTPUT ;
    USE SIGNAL ;
    PORT
      LAYER M7 ;
        RECT  39.872 75.931 39.904 76 ;
    END
  END dout[293]
  PIN dout[294]
    DIRECTION OUTPUT ;
    USE SIGNAL ;
    PORT
      LAYER M7 ;
        RECT  38.208 75.931 38.24 76 ;
    END
  END dout[294]
  PIN dout[295]
    DIRECTION OUTPUT ;
    USE SIGNAL ;
    PORT
      LAYER M7 ;
        RECT  37.44 75.931 37.472 76 ;
    END
  END dout[295]
  PIN dout[296]
    DIRECTION OUTPUT ;
    USE SIGNAL ;
    PORT
      LAYER M5 ;
        RECT  35.856 75.916 35.88 76 ;
    END
  END dout[296]
  PIN dout[297]
    DIRECTION OUTPUT ;
    USE SIGNAL ;
    PORT
      LAYER M7 ;
        RECT  40.64 75.931 40.672 76 ;
    END
  END dout[297]
  PIN dout[298]
    DIRECTION OUTPUT ;
    USE SIGNAL ;
    PORT
      LAYER M5 ;
        RECT  32.4 75.916 32.424 76 ;
    END
  END dout[298]
  PIN dout[299]
    DIRECTION OUTPUT ;
    USE SIGNAL ;
    PORT
      LAYER M7 ;
        RECT  39.936 75.931 39.968 76 ;
    END
  END dout[299]
  PIN dout[29]
    DIRECTION OUTPUT ;
    USE SIGNAL ;
    PORT
      LAYER M7 ;
        RECT  21.056 75.931 21.088 76 ;
    END
  END dout[29]
  PIN dout[2]
    DIRECTION OUTPUT ;
    USE SIGNAL ;
    PORT
      LAYER M7 ;
        RECT  39.296 75.931 39.328 76 ;
    END
  END dout[2]
  PIN dout[300]
    DIRECTION OUTPUT ;
    USE SIGNAL ;
    PORT
      LAYER M5 ;
        RECT  42.624 75.916 42.648 76 ;
    END
  END dout[300]
  PIN dout[301]
    DIRECTION OUTPUT ;
    USE SIGNAL ;
    PORT
      LAYER M7 ;
        RECT  36.16 75.931 36.192 76 ;
    END
  END dout[301]
  PIN dout[302]
    DIRECTION OUTPUT ;
    USE SIGNAL ;
    PORT
      LAYER M5 ;
        RECT  31.152 75.916 31.176 76 ;
    END
  END dout[302]
  PIN dout[303]
    DIRECTION OUTPUT ;
    USE SIGNAL ;
    PORT
      LAYER M5 ;
        RECT  30.432 75.916 30.456 76 ;
    END
  END dout[303]
  PIN dout[304]
    DIRECTION OUTPUT ;
    USE SIGNAL ;
    PORT
      LAYER M7 ;
        RECT  36.352 75.931 36.384 76 ;
    END
  END dout[304]
  PIN dout[305]
    DIRECTION OUTPUT ;
    USE SIGNAL ;
    PORT
      LAYER M7 ;
        RECT  22.464 75.931 22.496 76 ;
    END
  END dout[305]
  PIN dout[306]
    DIRECTION OUTPUT ;
    USE SIGNAL ;
    PORT
      LAYER M5 ;
        RECT  28.32 75.916 28.344 76 ;
    END
  END dout[306]
  PIN dout[307]
    DIRECTION OUTPUT ;
    USE SIGNAL ;
    PORT
      LAYER M5 ;
        RECT  33.84 75.916 33.864 76 ;
    END
  END dout[307]
  PIN dout[308]
    DIRECTION OUTPUT ;
    USE SIGNAL ;
    PORT
      LAYER M5 ;
        RECT  19.728 75.916 19.752 76 ;
    END
  END dout[308]
  PIN dout[309]
    DIRECTION OUTPUT ;
    USE SIGNAL ;
    PORT
      LAYER M7 ;
        RECT  20.992 75.931 21.024 76 ;
    END
  END dout[309]
  PIN dout[30]
    DIRECTION OUTPUT ;
    USE SIGNAL ;
    PORT
      LAYER M7 ;
        RECT  22.976 75.931 23.008 76 ;
    END
  END dout[30]
  PIN dout[310]
    DIRECTION OUTPUT ;
    USE SIGNAL ;
    PORT
      LAYER M7 ;
        RECT  22.912 75.931 22.944 76 ;
    END
  END dout[310]
  PIN dout[311]
    DIRECTION OUTPUT ;
    USE SIGNAL ;
    PORT
      LAYER M5 ;
        RECT  18.432 75.916 18.456 76 ;
    END
  END dout[311]
  PIN dout[312]
    DIRECTION OUTPUT ;
    USE SIGNAL ;
    PORT
      LAYER M7 ;
        RECT  39.168 75.931 39.2 76 ;
    END
  END dout[312]
  PIN dout[313]
    DIRECTION OUTPUT ;
    USE SIGNAL ;
    PORT
      LAYER M7 ;
        RECT  39.04 75.931 39.072 76 ;
    END
  END dout[313]
  PIN dout[314]
    DIRECTION OUTPUT ;
    USE SIGNAL ;
    PORT
      LAYER M7 ;
        RECT  39.424 75.931 39.456 76 ;
    END
  END dout[314]
  PIN dout[315]
    DIRECTION OUTPUT ;
    USE SIGNAL ;
    PORT
      LAYER M5 ;
        RECT  35.04 75.916 35.064 76 ;
    END
  END dout[315]
  PIN dout[316]
    DIRECTION OUTPUT ;
    USE SIGNAL ;
    PORT
      LAYER M7 ;
        RECT  37.184 75.931 37.216 76 ;
    END
  END dout[316]
  PIN dout[317]
    DIRECTION OUTPUT ;
    USE SIGNAL ;
    PORT
      LAYER M5 ;
        RECT  19.824 75.916 19.848 76 ;
    END
  END dout[317]
  PIN dout[318]
    DIRECTION OUTPUT ;
    USE SIGNAL ;
    PORT
      LAYER M7 ;
        RECT  9.6 75.931 9.632 76 ;
    END
  END dout[318]
  PIN dout[319]
    DIRECTION OUTPUT ;
    USE SIGNAL ;
    PORT
      LAYER M7 ;
        RECT  13.76 75.931 13.792 76 ;
    END
  END dout[319]
  PIN dout[31]
    DIRECTION OUTPUT ;
    USE SIGNAL ;
    PORT
      LAYER M5 ;
        RECT  18.48 75.916 18.504 76 ;
    END
  END dout[31]
  PIN dout[320]
    DIRECTION OUTPUT ;
    USE SIGNAL ;
    PORT
      LAYER M7 ;
        RECT  36.672 75.931 36.704 76 ;
    END
  END dout[320]
  PIN dout[321]
    DIRECTION OUTPUT ;
    USE SIGNAL ;
    PORT
      LAYER M5 ;
        RECT  7.776 75.916 7.8 76 ;
    END
  END dout[321]
  PIN dout[322]
    DIRECTION OUTPUT ;
    USE SIGNAL ;
    PORT
      LAYER M7 ;
        RECT  38.528 75.931 38.56 76 ;
    END
  END dout[322]
  PIN dout[323]
    DIRECTION OUTPUT ;
    USE SIGNAL ;
    PORT
      LAYER M5 ;
        RECT  16.56 75.916 16.584 76 ;
    END
  END dout[323]
  PIN dout[324]
    DIRECTION OUTPUT ;
    USE SIGNAL ;
    PORT
      LAYER M7 ;
        RECT  9.152 75.931 9.184 76 ;
    END
  END dout[324]
  PIN dout[325]
    DIRECTION OUTPUT ;
    USE SIGNAL ;
    PORT
      LAYER M5 ;
        RECT  34.56 75.916 34.584 76 ;
    END
  END dout[325]
  PIN dout[326]
    DIRECTION OUTPUT ;
    USE SIGNAL ;
    PORT
      LAYER M5 ;
        RECT  34.224 75.916 34.248 76 ;
    END
  END dout[326]
  PIN dout[327]
    DIRECTION OUTPUT ;
    USE SIGNAL ;
    PORT
      LAYER M5 ;
        RECT  33.072 75.916 33.096 76 ;
    END
  END dout[327]
  PIN dout[328]
    DIRECTION OUTPUT ;
    USE SIGNAL ;
    PORT
      LAYER M5 ;
        RECT  18 75.916 18.024 76 ;
    END
  END dout[328]
  PIN dout[329]
    DIRECTION OUTPUT ;
    USE SIGNAL ;
    PORT
      LAYER M7 ;
        RECT  36.928 75.931 36.96 76 ;
    END
  END dout[329]
  PIN dout[32]
    DIRECTION OUTPUT ;
    USE SIGNAL ;
    PORT
      LAYER M7 ;
        RECT  39.232 75.931 39.264 76 ;
    END
  END dout[32]
  PIN dout[330]
    DIRECTION OUTPUT ;
    USE SIGNAL ;
    PORT
      LAYER M7 ;
        RECT  37.504 75.931 37.536 76 ;
    END
  END dout[330]
  PIN dout[331]
    DIRECTION OUTPUT ;
    USE SIGNAL ;
    PORT
      LAYER M7 ;
        RECT  41.984 75.931 42.016 76 ;
    END
  END dout[331]
  PIN dout[332]
    DIRECTION OUTPUT ;
    USE SIGNAL ;
    PORT
      LAYER M7 ;
        RECT  41.728 75.931 41.76 76 ;
    END
  END dout[332]
  PIN dout[333]
    DIRECTION OUTPUT ;
    USE SIGNAL ;
    PORT
      LAYER M7 ;
        RECT  39.808 75.931 39.84 76 ;
    END
  END dout[333]
  PIN dout[334]
    DIRECTION OUTPUT ;
    USE SIGNAL ;
    PORT
      LAYER M7 ;
        RECT  38.656 75.931 38.688 76 ;
    END
  END dout[334]
  PIN dout[335]
    DIRECTION OUTPUT ;
    USE SIGNAL ;
    PORT
      LAYER M7 ;
        RECT  38.016 75.931 38.048 76 ;
    END
  END dout[335]
  PIN dout[336]
    DIRECTION OUTPUT ;
    USE SIGNAL ;
    PORT
      LAYER M7 ;
        RECT  39.488 75.931 39.52 76 ;
    END
  END dout[336]
  PIN dout[337]
    DIRECTION OUTPUT ;
    USE SIGNAL ;
    PORT
      LAYER M7 ;
        RECT  39.36 75.931 39.392 76 ;
    END
  END dout[337]
  PIN dout[338]
    DIRECTION OUTPUT ;
    USE SIGNAL ;
    PORT
      LAYER M7 ;
        RECT  40.128 75.931 40.16 76 ;
    END
  END dout[338]
  PIN dout[339]
    DIRECTION OUTPUT ;
    USE SIGNAL ;
    PORT
      LAYER M7 ;
        RECT  37.056 75.931 37.088 76 ;
    END
  END dout[339]
  PIN dout[33]
    DIRECTION OUTPUT ;
    USE SIGNAL ;
    PORT
      LAYER M7 ;
        RECT  39.104 75.931 39.136 76 ;
    END
  END dout[33]
  PIN dout[340]
    DIRECTION OUTPUT ;
    USE SIGNAL ;
    PORT
      LAYER M7 ;
        RECT  40.832 75.931 40.864 76 ;
    END
  END dout[340]
  PIN dout[341]
    DIRECTION OUTPUT ;
    USE SIGNAL ;
    PORT
      LAYER M7 ;
        RECT  41.152 75.931 41.184 76 ;
    END
  END dout[341]
  PIN dout[342]
    DIRECTION OUTPUT ;
    USE SIGNAL ;
    PORT
      LAYER M7 ;
        RECT  40.32 75.931 40.352 76 ;
    END
  END dout[342]
  PIN dout[343]
    DIRECTION OUTPUT ;
    USE SIGNAL ;
    PORT
      LAYER M7 ;
        RECT  41.088 75.931 41.12 76 ;
    END
  END dout[343]
  PIN dout[344]
    DIRECTION OUTPUT ;
    USE SIGNAL ;
    PORT
      LAYER M7 ;
        RECT  21.184 75.931 21.216 76 ;
    END
  END dout[344]
  PIN dout[345]
    DIRECTION OUTPUT ;
    USE SIGNAL ;
    PORT
      LAYER M5 ;
        RECT  29.712 75.916 29.736 76 ;
    END
  END dout[345]
  PIN dout[346]
    DIRECTION OUTPUT ;
    USE SIGNAL ;
    PORT
      LAYER M5 ;
        RECT  17.808 75.916 17.832 76 ;
    END
  END dout[346]
  PIN dout[347]
    DIRECTION OUTPUT ;
    USE SIGNAL ;
    PORT
      LAYER M5 ;
        RECT  29.232 75.916 29.256 76 ;
    END
  END dout[347]
  PIN dout[348]
    DIRECTION OUTPUT ;
    USE SIGNAL ;
    PORT
      LAYER M7 ;
        RECT  9.984 75.931 10.016 76 ;
    END
  END dout[348]
  PIN dout[349]
    DIRECTION OUTPUT ;
    USE SIGNAL ;
    PORT
      LAYER M7 ;
        RECT  11.52 75.931 11.552 76 ;
    END
  END dout[349]
  PIN dout[34]
    DIRECTION OUTPUT ;
    USE SIGNAL ;
    PORT
      LAYER M7 ;
        RECT  42.048 75.931 42.08 76 ;
    END
  END dout[34]
  PIN dout[350]
    DIRECTION OUTPUT ;
    USE SIGNAL ;
    PORT
      LAYER M7 ;
        RECT  12.416 75.931 12.448 76 ;
    END
  END dout[350]
  PIN dout[351]
    DIRECTION OUTPUT ;
    USE SIGNAL ;
    PORT
      LAYER M7 ;
        RECT  9.216 75.931 9.248 76 ;
    END
  END dout[351]
  PIN dout[352]
    DIRECTION OUTPUT ;
    USE SIGNAL ;
    PORT
      LAYER M7 ;
        RECT  10.624 75.931 10.656 76 ;
    END
  END dout[352]
  PIN dout[353]
    DIRECTION OUTPUT ;
    USE SIGNAL ;
    PORT
      LAYER M7 ;
        RECT  10.112 75.931 10.144 76 ;
    END
  END dout[353]
  PIN dout[354]
    DIRECTION OUTPUT ;
    USE SIGNAL ;
    PORT
      LAYER M7 ;
        RECT  22.528 75.931 22.56 76 ;
    END
  END dout[354]
  PIN dout[355]
    DIRECTION OUTPUT ;
    USE SIGNAL ;
    PORT
      LAYER M5 ;
        RECT  16.992 75.916 17.016 76 ;
    END
  END dout[355]
  PIN dout[356]
    DIRECTION OUTPUT ;
    USE SIGNAL ;
    PORT
      LAYER M5 ;
        RECT  15.408 75.916 15.432 76 ;
    END
  END dout[356]
  PIN dout[357]
    DIRECTION OUTPUT ;
    USE SIGNAL ;
    PORT
      LAYER M5 ;
        RECT  7.2 75.916 7.224 76 ;
    END
  END dout[357]
  PIN dout[358]
    DIRECTION OUTPUT ;
    USE SIGNAL ;
    PORT
      LAYER M5 ;
        RECT  26.592 75.916 26.616 76 ;
    END
  END dout[358]
  PIN dout[359]
    DIRECTION OUTPUT ;
    USE SIGNAL ;
    PORT
      LAYER M5 ;
        RECT  27.936 75.916 27.96 76 ;
    END
  END dout[359]
  PIN dout[35]
    DIRECTION OUTPUT ;
    USE SIGNAL ;
    PORT
      LAYER M5 ;
        RECT  34.992 75.916 35.016 76 ;
    END
  END dout[35]
  PIN dout[360]
    DIRECTION OUTPUT ;
    USE SIGNAL ;
    PORT
      LAYER M5 ;
        RECT  6.816 75.916 6.84 76 ;
    END
  END dout[360]
  PIN dout[361]
    DIRECTION OUTPUT ;
    USE SIGNAL ;
    PORT
      LAYER M5 ;
        RECT  7.536 75.916 7.56 76 ;
    END
  END dout[361]
  PIN dout[362]
    DIRECTION OUTPUT ;
    USE SIGNAL ;
    PORT
      LAYER M7 ;
        RECT  3.968 75.931 4 76 ;
    END
  END dout[362]
  PIN dout[363]
    DIRECTION OUTPUT ;
    USE SIGNAL ;
    PORT
      LAYER M7 ;
        RECT  2.816 75.931 2.848 76 ;
    END
  END dout[363]
  PIN dout[364]
    DIRECTION OUTPUT ;
    USE SIGNAL ;
    PORT
      LAYER M5 ;
        RECT  5.184 75.916 5.208 76 ;
    END
  END dout[364]
  PIN dout[365]
    DIRECTION OUTPUT ;
    USE SIGNAL ;
    PORT
      LAYER M5 ;
        RECT  7.344 75.916 7.368 76 ;
    END
  END dout[365]
  PIN dout[366]
    DIRECTION OUTPUT ;
    USE SIGNAL ;
    PORT
      LAYER M5 ;
        RECT  6.24 75.916 6.264 76 ;
    END
  END dout[366]
  PIN dout[367]
    DIRECTION OUTPUT ;
    USE SIGNAL ;
    PORT
      LAYER M7 ;
        RECT  4.8 75.931 4.832 76 ;
    END
  END dout[367]
  PIN dout[368]
    DIRECTION OUTPUT ;
    USE SIGNAL ;
    PORT
      LAYER M7 ;
        RECT  3.904 75.931 3.936 76 ;
    END
  END dout[368]
  PIN dout[369]
    DIRECTION OUTPUT ;
    USE SIGNAL ;
    PORT
      LAYER M7 ;
        RECT  4.096 75.931 4.128 76 ;
    END
  END dout[369]
  PIN dout[36]
    DIRECTION OUTPUT ;
    USE SIGNAL ;
    PORT
      LAYER M7 ;
        RECT  37.12 75.931 37.152 76 ;
    END
  END dout[36]
  PIN dout[370]
    DIRECTION OUTPUT ;
    USE SIGNAL ;
    PORT
      LAYER M5 ;
        RECT  5.424 75.916 5.448 76 ;
    END
  END dout[370]
  PIN dout[371]
    DIRECTION OUTPUT ;
    USE SIGNAL ;
    PORT
      LAYER M7 ;
        RECT  4.416 75.931 4.448 76 ;
    END
  END dout[371]
  PIN dout[372]
    DIRECTION OUTPUT ;
    USE SIGNAL ;
    PORT
      LAYER M5 ;
        RECT  6 75.916 6.024 76 ;
    END
  END dout[372]
  PIN dout[373]
    DIRECTION OUTPUT ;
    USE SIGNAL ;
    PORT
      LAYER M5 ;
        RECT  6.432 75.916 6.456 76 ;
    END
  END dout[373]
  PIN dout[374]
    DIRECTION OUTPUT ;
    USE SIGNAL ;
    PORT
      LAYER M7 ;
        RECT  4.224 75.931 4.256 76 ;
    END
  END dout[374]
  PIN dout[375]
    DIRECTION OUTPUT ;
    USE SIGNAL ;
    PORT
      LAYER M5 ;
        RECT  5.04 75.916 5.064 76 ;
    END
  END dout[375]
  PIN dout[376]
    DIRECTION OUTPUT ;
    USE SIGNAL ;
    PORT
      LAYER M5 ;
        RECT  7.104 75.916 7.128 76 ;
    END
  END dout[376]
  PIN dout[377]
    DIRECTION OUTPUT ;
    USE SIGNAL ;
    PORT
      LAYER M5 ;
        RECT  7.728 75.916 7.752 76 ;
    END
  END dout[377]
  PIN dout[378]
    DIRECTION OUTPUT ;
    USE SIGNAL ;
    PORT
      LAYER M7 ;
        RECT  3.712 75.931 3.744 76 ;
    END
  END dout[378]
  PIN dout[379]
    DIRECTION OUTPUT ;
    USE SIGNAL ;
    PORT
      LAYER M5 ;
        RECT  6.336 75.916 6.36 76 ;
    END
  END dout[379]
  PIN dout[37]
    DIRECTION OUTPUT ;
    USE SIGNAL ;
    PORT
      LAYER M5 ;
        RECT  19.776 75.916 19.8 76 ;
    END
  END dout[37]
  PIN dout[380]
    DIRECTION OUTPUT ;
    USE SIGNAL ;
    PORT
      LAYER M7 ;
        RECT  3.456 75.931 3.488 76 ;
    END
  END dout[380]
  PIN dout[381]
    DIRECTION OUTPUT ;
    USE SIGNAL ;
    PORT
      LAYER M7 ;
        RECT  3.584 75.931 3.616 76 ;
    END
  END dout[381]
  PIN dout[382]
    DIRECTION OUTPUT ;
    USE SIGNAL ;
    PORT
      LAYER M5 ;
        RECT  8.448 75.916 8.472 76 ;
    END
  END dout[382]
  PIN dout[383]
    DIRECTION OUTPUT ;
    USE SIGNAL ;
    PORT
      LAYER M7 ;
        RECT  9.344 75.931 9.376 76 ;
    END
  END dout[383]
  PIN dout[384]
    DIRECTION OUTPUT ;
    USE SIGNAL ;
    PORT
      LAYER M5 ;
        RECT  8.208 75.916 8.232 76 ;
    END
  END dout[384]
  PIN dout[385]
    DIRECTION OUTPUT ;
    USE SIGNAL ;
    PORT
      LAYER M7 ;
        RECT  10.752 75.931 10.784 76 ;
    END
  END dout[385]
  PIN dout[386]
    DIRECTION OUTPUT ;
    USE SIGNAL ;
    PORT
      LAYER M5 ;
        RECT  17.52 75.916 17.544 76 ;
    END
  END dout[386]
  PIN dout[387]
    DIRECTION OUTPUT ;
    USE SIGNAL ;
    PORT
      LAYER M5 ;
        RECT  15.6 75.916 15.624 76 ;
    END
  END dout[387]
  PIN dout[388]
    DIRECTION OUTPUT ;
    USE SIGNAL ;
    PORT
      LAYER M7 ;
        RECT  2.56 75.931 2.592 76 ;
    END
  END dout[388]
  PIN dout[389]
    DIRECTION OUTPUT ;
    USE SIGNAL ;
    PORT
      LAYER M5 ;
        RECT  17.328 75.916 17.352 76 ;
    END
  END dout[389]
  PIN dout[38]
    DIRECTION OUTPUT ;
    USE SIGNAL ;
    PORT
      LAYER M7 ;
        RECT  9.536 75.931 9.568 76 ;
    END
  END dout[38]
  PIN dout[390]
    DIRECTION OUTPUT ;
    USE SIGNAL ;
    PORT
      LAYER M7 ;
        RECT  10.944 75.931 10.976 76 ;
    END
  END dout[390]
  PIN dout[391]
    DIRECTION OUTPUT ;
    USE SIGNAL ;
    PORT
      LAYER M5 ;
        RECT  14.544 75.916 14.568 76 ;
    END
  END dout[391]
  PIN dout[392]
    DIRECTION OUTPUT ;
    USE SIGNAL ;
    PORT
      LAYER M5 ;
        RECT  15.072 75.916 15.096 76 ;
    END
  END dout[392]
  PIN dout[393]
    DIRECTION OUTPUT ;
    USE SIGNAL ;
    PORT
      LAYER M5 ;
        RECT  16.176 75.916 16.2 76 ;
    END
  END dout[393]
  PIN dout[394]
    DIRECTION OUTPUT ;
    USE SIGNAL ;
    PORT
      LAYER M5 ;
        RECT  16.704 75.916 16.728 76 ;
    END
  END dout[394]
  PIN dout[395]
    DIRECTION OUTPUT ;
    USE SIGNAL ;
    PORT
      LAYER M5 ;
        RECT  20.304 75.916 20.328 76 ;
    END
  END dout[395]
  PIN dout[396]
    DIRECTION OUTPUT ;
    USE SIGNAL ;
    PORT
      LAYER M7 ;
        RECT  13.632 75.931 13.664 76 ;
    END
  END dout[396]
  PIN dout[397]
    DIRECTION OUTPUT ;
    USE SIGNAL ;
    PORT
      LAYER M5 ;
        RECT  19.44 75.916 19.464 76 ;
    END
  END dout[397]
  PIN dout[398]
    DIRECTION OUTPUT ;
    USE SIGNAL ;
    PORT
      LAYER M5 ;
        RECT  15.888 75.916 15.912 76 ;
    END
  END dout[398]
  PIN dout[399]
    DIRECTION OUTPUT ;
    USE SIGNAL ;
    PORT
      LAYER M5 ;
        RECT  34.512 75.916 34.536 76 ;
    END
  END dout[399]
  PIN dout[39]
    DIRECTION OUTPUT ;
    USE SIGNAL ;
    PORT
      LAYER M7 ;
        RECT  13.824 75.931 13.856 76 ;
    END
  END dout[39]
  PIN dout[3]
    DIRECTION OUTPUT ;
    USE SIGNAL ;
    PORT
      LAYER M7 ;
        RECT  38.912 75.931 38.944 76 ;
    END
  END dout[3]
  PIN dout[400]
    DIRECTION OUTPUT ;
    USE SIGNAL ;
    PORT
      LAYER M7 ;
        RECT  23.616 75.931 23.648 76 ;
    END
  END dout[400]
  PIN dout[401]
    DIRECTION OUTPUT ;
    USE SIGNAL ;
    PORT
      LAYER M5 ;
        RECT  27.024 75.916 27.048 76 ;
    END
  END dout[401]
  PIN dout[402]
    DIRECTION OUTPUT ;
    USE SIGNAL ;
    PORT
      LAYER M7 ;
        RECT  24.384 75.931 24.416 76 ;
    END
  END dout[402]
  PIN dout[403]
    DIRECTION OUTPUT ;
    USE SIGNAL ;
    PORT
      LAYER M5 ;
        RECT  27.648 75.916 27.672 76 ;
    END
  END dout[403]
  PIN dout[404]
    DIRECTION OUTPUT ;
    USE SIGNAL ;
    PORT
      LAYER M5 ;
        RECT  31.632 75.916 31.656 76 ;
    END
  END dout[404]
  PIN dout[405]
    DIRECTION OUTPUT ;
    USE SIGNAL ;
    PORT
      LAYER M5 ;
        RECT  17.712 75.916 17.736 76 ;
    END
  END dout[405]
  PIN dout[406]
    DIRECTION OUTPUT ;
    USE SIGNAL ;
    PORT
      LAYER M5 ;
        RECT  29.952 75.916 29.976 76 ;
    END
  END dout[406]
  PIN dout[407]
    DIRECTION OUTPUT ;
    USE SIGNAL ;
    PORT
      LAYER M5 ;
        RECT  33.792 75.916 33.816 76 ;
    END
  END dout[407]
  PIN dout[408]
    DIRECTION OUTPUT ;
    USE SIGNAL ;
    PORT
      LAYER M5 ;
        RECT  47.136 75.916 47.16 76 ;
    END
  END dout[408]
  PIN dout[409]
    DIRECTION OUTPUT ;
    USE SIGNAL ;
    PORT
      LAYER M5 ;
        RECT  46.08 75.916 46.104 76 ;
    END
  END dout[409]
  PIN dout[40]
    DIRECTION OUTPUT ;
    USE SIGNAL ;
    PORT
      LAYER M7 ;
        RECT  36.992 75.931 37.024 76 ;
    END
  END dout[40]
  PIN dout[410]
    DIRECTION OUTPUT ;
    USE SIGNAL ;
    PORT
      LAYER M5 ;
        RECT  45.312 75.916 45.336 76 ;
    END
  END dout[410]
  PIN dout[411]
    DIRECTION OUTPUT ;
    USE SIGNAL ;
    PORT
      LAYER M5 ;
        RECT  46.416 75.916 46.44 76 ;
    END
  END dout[411]
  PIN dout[412]
    DIRECTION OUTPUT ;
    USE SIGNAL ;
    PORT
      LAYER M7 ;
        RECT  40 75.931 40.032 76 ;
    END
  END dout[412]
  PIN dout[413]
    DIRECTION OUTPUT ;
    USE SIGNAL ;
    PORT
      LAYER M5 ;
        RECT  43.92 75.916 43.944 76 ;
    END
  END dout[413]
  PIN dout[414]
    DIRECTION OUTPUT ;
    USE SIGNAL ;
    PORT
      LAYER M5 ;
        RECT  45.072 75.916 45.096 76 ;
    END
  END dout[414]
  PIN dout[415]
    DIRECTION OUTPUT ;
    USE SIGNAL ;
    PORT
      LAYER M5 ;
        RECT  43.44 75.916 43.464 76 ;
    END
  END dout[415]
  PIN dout[416]
    DIRECTION OUTPUT ;
    USE SIGNAL ;
    PORT
      LAYER M5 ;
        RECT  42.96 75.916 42.984 76 ;
    END
  END dout[416]
  PIN dout[417]
    DIRECTION OUTPUT ;
    USE SIGNAL ;
    PORT
      LAYER M5 ;
        RECT  43.728 75.916 43.752 76 ;
    END
  END dout[417]
  PIN dout[418]
    DIRECTION OUTPUT ;
    USE SIGNAL ;
    PORT
      LAYER M5 ;
        RECT  43.824 75.916 43.848 76 ;
    END
  END dout[418]
  PIN dout[419]
    DIRECTION OUTPUT ;
    USE SIGNAL ;
    PORT
      LAYER M7 ;
        RECT  40.576 75.931 40.608 76 ;
    END
  END dout[419]
  PIN dout[41]
    DIRECTION OUTPUT ;
    USE SIGNAL ;
    PORT
      LAYER M5 ;
        RECT  7.68 75.916 7.704 76 ;
    END
  END dout[41]
  PIN dout[420]
    DIRECTION OUTPUT ;
    USE SIGNAL ;
    PORT
      LAYER M5 ;
        RECT  43.2 75.916 43.224 76 ;
    END
  END dout[420]
  PIN dout[421]
    DIRECTION OUTPUT ;
    USE SIGNAL ;
    PORT
      LAYER M5 ;
        RECT  45.888 75.916 45.912 76 ;
    END
  END dout[421]
  PIN dout[422]
    DIRECTION OUTPUT ;
    USE SIGNAL ;
    PORT
      LAYER M5 ;
        RECT  41.568 75.916 41.592 76 ;
    END
  END dout[422]
  PIN dout[423]
    DIRECTION OUTPUT ;
    USE SIGNAL ;
    PORT
      LAYER M7 ;
        RECT  37.568 75.931 37.6 76 ;
    END
  END dout[423]
  PIN dout[424]
    DIRECTION OUTPUT ;
    USE SIGNAL ;
    PORT
      LAYER M5 ;
        RECT  43.056 75.916 43.08 76 ;
    END
  END dout[424]
  PIN dout[425]
    DIRECTION OUTPUT ;
    USE SIGNAL ;
    PORT
      LAYER M5 ;
        RECT  44.4 75.916 44.424 76 ;
    END
  END dout[425]
  PIN dout[426]
    DIRECTION OUTPUT ;
    USE SIGNAL ;
    PORT
      LAYER M5 ;
        RECT  43.344 75.916 43.368 76 ;
    END
  END dout[426]
  PIN dout[427]
    DIRECTION OUTPUT ;
    USE SIGNAL ;
    PORT
      LAYER M5 ;
        RECT  45.024 75.916 45.048 76 ;
    END
  END dout[427]
  PIN dout[428]
    DIRECTION OUTPUT ;
    USE SIGNAL ;
    PORT
      LAYER M5 ;
        RECT  46.656 75.916 46.68 76 ;
    END
  END dout[428]
  PIN dout[429]
    DIRECTION OUTPUT ;
    USE SIGNAL ;
    PORT
      LAYER M5 ;
        RECT  46.512 75.916 46.536 76 ;
    END
  END dout[429]
  PIN dout[42]
    DIRECTION OUTPUT ;
    USE SIGNAL ;
    PORT
      LAYER M7 ;
        RECT  38.592 75.931 38.624 76 ;
    END
  END dout[42]
  PIN dout[430]
    DIRECTION OUTPUT ;
    USE SIGNAL ;
    PORT
      LAYER M5 ;
        RECT  44.544 75.916 44.568 76 ;
    END
  END dout[430]
  PIN dout[431]
    DIRECTION OUTPUT ;
    USE SIGNAL ;
    PORT
      LAYER M5 ;
        RECT  46.896 75.916 46.92 76 ;
    END
  END dout[431]
  PIN dout[432]
    DIRECTION OUTPUT ;
    USE SIGNAL ;
    PORT
      LAYER M5 ;
        RECT  44.976 75.916 45 76 ;
    END
  END dout[432]
  PIN dout[433]
    DIRECTION OUTPUT ;
    USE SIGNAL ;
    PORT
      LAYER M5 ;
        RECT  45.744 75.916 45.768 76 ;
    END
  END dout[433]
  PIN dout[434]
    DIRECTION OUTPUT ;
    USE SIGNAL ;
    PORT
      LAYER M5 ;
        RECT  43.968 75.916 43.992 76 ;
    END
  END dout[434]
  PIN dout[435]
    DIRECTION OUTPUT ;
    USE SIGNAL ;
    PORT
      LAYER M5 ;
        RECT  41.664 75.916 41.688 76 ;
    END
  END dout[435]
  PIN dout[436]
    DIRECTION OUTPUT ;
    USE SIGNAL ;
    PORT
      LAYER M7 ;
        RECT  39.68 75.931 39.712 76 ;
    END
  END dout[436]
  PIN dout[437]
    DIRECTION OUTPUT ;
    USE SIGNAL ;
    PORT
      LAYER M5 ;
        RECT  45.504 75.916 45.528 76 ;
    END
  END dout[437]
  PIN dout[438]
    DIRECTION OUTPUT ;
    USE SIGNAL ;
    PORT
      LAYER M5 ;
        RECT  41.808 75.916 41.832 76 ;
    END
  END dout[438]
  PIN dout[439]
    DIRECTION OUTPUT ;
    USE SIGNAL ;
    PORT
      LAYER M5 ;
        RECT  31.728 75.916 31.752 76 ;
    END
  END dout[439]
  PIN dout[43]
    DIRECTION OUTPUT ;
    USE SIGNAL ;
    PORT
      LAYER M5 ;
        RECT  16.512 75.916 16.536 76 ;
    END
  END dout[43]
  PIN dout[440]
    DIRECTION OUTPUT ;
    USE SIGNAL ;
    PORT
      LAYER M7 ;
        RECT  38.272 75.931 38.304 76 ;
    END
  END dout[440]
  PIN dout[441]
    DIRECTION OUTPUT ;
    USE SIGNAL ;
    PORT
      LAYER M5 ;
        RECT  46.32 75.916 46.344 76 ;
    END
  END dout[441]
  PIN dout[442]
    DIRECTION OUTPUT ;
    USE SIGNAL ;
    PORT
      LAYER M5 ;
        RECT  44.064 75.916 44.088 76 ;
    END
  END dout[442]
  PIN dout[443]
    DIRECTION OUTPUT ;
    USE SIGNAL ;
    PORT
      LAYER M5 ;
        RECT  47.28 75.916 47.304 76 ;
    END
  END dout[443]
  PIN dout[444]
    DIRECTION OUTPUT ;
    USE SIGNAL ;
    PORT
      LAYER M5 ;
        RECT  44.256 75.916 44.28 76 ;
    END
  END dout[444]
  PIN dout[445]
    DIRECTION OUTPUT ;
    USE SIGNAL ;
    PORT
      LAYER M5 ;
        RECT  45.552 75.916 45.576 76 ;
    END
  END dout[445]
  PIN dout[446]
    DIRECTION OUTPUT ;
    USE SIGNAL ;
    PORT
      LAYER M7 ;
        RECT  38.464 75.931 38.496 76 ;
    END
  END dout[446]
  PIN dout[447]
    DIRECTION OUTPUT ;
    USE SIGNAL ;
    PORT
      LAYER M5 ;
        RECT  43.104 75.916 43.128 76 ;
    END
  END dout[447]
  PIN dout[448]
    DIRECTION OUTPUT ;
    USE SIGNAL ;
    PORT
      LAYER M7 ;
        RECT  40.256 75.931 40.288 76 ;
    END
  END dout[448]
  PIN dout[449]
    DIRECTION OUTPUT ;
    USE SIGNAL ;
    PORT
      LAYER M7 ;
        RECT  39.744 75.931 39.776 76 ;
    END
  END dout[449]
  PIN dout[44]
    DIRECTION OUTPUT ;
    USE SIGNAL ;
    PORT
      LAYER M7 ;
        RECT  9.408 75.931 9.44 76 ;
    END
  END dout[44]
  PIN dout[450]
    DIRECTION OUTPUT ;
    USE SIGNAL ;
    PORT
      LAYER M7 ;
        RECT  40.448 75.931 40.48 76 ;
    END
  END dout[450]
  PIN dout[451]
    DIRECTION OUTPUT ;
    USE SIGNAL ;
    PORT
      LAYER M5 ;
        RECT  45.168 75.916 45.192 76 ;
    END
  END dout[451]
  PIN dout[452]
    DIRECTION OUTPUT ;
    USE SIGNAL ;
    PORT
      LAYER M5 ;
        RECT  43.536 75.916 43.56 76 ;
    END
  END dout[452]
  PIN dout[453]
    DIRECTION OUTPUT ;
    USE SIGNAL ;
    PORT
      LAYER M7 ;
        RECT  22.848 75.931 22.88 76 ;
    END
  END dout[453]
  PIN dout[454]
    DIRECTION OUTPUT ;
    USE SIGNAL ;
    PORT
      LAYER M5 ;
        RECT  41.952 75.916 41.976 76 ;
    END
  END dout[454]
  PIN dout[455]
    DIRECTION OUTPUT ;
    USE SIGNAL ;
    PORT
      LAYER M7 ;
        RECT  36.8 75.931 36.832 76 ;
    END
  END dout[455]
  PIN dout[456]
    DIRECTION OUTPUT ;
    USE SIGNAL ;
    PORT
      LAYER M5 ;
        RECT  35.904 75.916 35.928 76 ;
    END
  END dout[456]
  PIN dout[457]
    DIRECTION OUTPUT ;
    USE SIGNAL ;
    PORT
      LAYER M5 ;
        RECT  46.608 75.916 46.632 76 ;
    END
  END dout[457]
  PIN dout[458]
    DIRECTION OUTPUT ;
    USE SIGNAL ;
    PORT
      LAYER M5 ;
        RECT  43.632 75.916 43.656 76 ;
    END
  END dout[458]
  PIN dout[459]
    DIRECTION OUTPUT ;
    USE SIGNAL ;
    PORT
      LAYER M7 ;
        RECT  41.92 75.931 41.952 76 ;
    END
  END dout[459]
  PIN dout[45]
    DIRECTION OUTPUT ;
    USE SIGNAL ;
    PORT
      LAYER M5 ;
        RECT  34.608 75.916 34.632 76 ;
    END
  END dout[45]
  PIN dout[460]
    DIRECTION OUTPUT ;
    USE SIGNAL ;
    PORT
      LAYER M7 ;
        RECT  37.376 75.931 37.408 76 ;
    END
  END dout[460]
  PIN dout[461]
    DIRECTION OUTPUT ;
    USE SIGNAL ;
    PORT
      LAYER M5 ;
        RECT  42.24 75.916 42.264 76 ;
    END
  END dout[461]
  PIN dout[462]
    DIRECTION OUTPUT ;
    USE SIGNAL ;
    PORT
      LAYER M7 ;
        RECT  41.216 75.931 41.248 76 ;
    END
  END dout[462]
  PIN dout[463]
    DIRECTION OUTPUT ;
    USE SIGNAL ;
    PORT
      LAYER M5 ;
        RECT  42.48 75.916 42.504 76 ;
    END
  END dout[463]
  PIN dout[464]
    DIRECTION OUTPUT ;
    USE SIGNAL ;
    PORT
      LAYER M7 ;
        RECT  36.032 75.931 36.064 76 ;
    END
  END dout[464]
  PIN dout[465]
    DIRECTION OUTPUT ;
    USE SIGNAL ;
    PORT
      LAYER M5 ;
        RECT  45.84 75.916 45.864 76 ;
    END
  END dout[465]
  PIN dout[466]
    DIRECTION OUTPUT ;
    USE SIGNAL ;
    PORT
      LAYER M5 ;
        RECT  46.848 75.916 46.872 76 ;
    END
  END dout[466]
  PIN dout[467]
    DIRECTION OUTPUT ;
    USE SIGNAL ;
    PORT
      LAYER M5 ;
        RECT  46.992 75.916 47.016 76 ;
    END
  END dout[467]
  PIN dout[468]
    DIRECTION OUTPUT ;
    USE SIGNAL ;
    PORT
      LAYER M5 ;
        RECT  46.944 75.916 46.968 76 ;
    END
  END dout[468]
  PIN dout[469]
    DIRECTION OUTPUT ;
    USE SIGNAL ;
    PORT
      LAYER M5 ;
        RECT  47.088 75.916 47.112 76 ;
    END
  END dout[469]
  PIN dout[46]
    DIRECTION OUTPUT ;
    USE SIGNAL ;
    PORT
      LAYER M5 ;
        RECT  34.176 75.916 34.2 76 ;
    END
  END dout[46]
  PIN dout[470]
    DIRECTION OUTPUT ;
    USE SIGNAL ;
    PORT
      LAYER M5 ;
        RECT  46.368 75.916 46.392 76 ;
    END
  END dout[470]
  PIN dout[471]
    DIRECTION OUTPUT ;
    USE SIGNAL ;
    PORT
      LAYER M5 ;
        RECT  45.648 75.916 45.672 76 ;
    END
  END dout[471]
  PIN dout[472]
    DIRECTION OUTPUT ;
    USE SIGNAL ;
    PORT
      LAYER M5 ;
        RECT  68.832 75.916 68.856 76 ;
    END
  END dout[472]
  PIN dout[473]
    DIRECTION OUTPUT ;
    USE SIGNAL ;
    PORT
      LAYER M5 ;
        RECT  68.112 75.916 68.136 76 ;
    END
  END dout[473]
  PIN dout[474]
    DIRECTION OUTPUT ;
    USE SIGNAL ;
    PORT
      LAYER M5 ;
        RECT  67.728 75.916 67.752 76 ;
    END
  END dout[474]
  PIN dout[475]
    DIRECTION OUTPUT ;
    USE SIGNAL ;
    PORT
      LAYER M5 ;
        RECT  66.624 75.916 66.648 76 ;
    END
  END dout[475]
  PIN dout[476]
    DIRECTION OUTPUT ;
    USE SIGNAL ;
    PORT
      LAYER M5 ;
        RECT  67.152 75.916 67.176 76 ;
    END
  END dout[476]
  PIN dout[477]
    DIRECTION OUTPUT ;
    USE SIGNAL ;
    PORT
      LAYER M5 ;
        RECT  68.88 75.916 68.904 76 ;
    END
  END dout[477]
  PIN dout[478]
    DIRECTION OUTPUT ;
    USE SIGNAL ;
    PORT
      LAYER M5 ;
        RECT  68.064 75.916 68.088 76 ;
    END
  END dout[478]
  PIN dout[479]
    DIRECTION OUTPUT ;
    USE SIGNAL ;
    PORT
      LAYER M5 ;
        RECT  68.928 75.916 68.952 76 ;
    END
  END dout[479]
  PIN dout[47]
    DIRECTION OUTPUT ;
    USE SIGNAL ;
    PORT
      LAYER M5 ;
        RECT  33.024 75.916 33.048 76 ;
    END
  END dout[47]
  PIN dout[480]
    DIRECTION OUTPUT ;
    USE SIGNAL ;
    PORT
      LAYER M5 ;
        RECT  68.976 75.916 69 76 ;
    END
  END dout[480]
  PIN dout[481]
    DIRECTION OUTPUT ;
    USE SIGNAL ;
    PORT
      LAYER M5 ;
        RECT  68.496 75.916 68.52 76 ;
    END
  END dout[481]
  PIN dout[482]
    DIRECTION OUTPUT ;
    USE SIGNAL ;
    PORT
      LAYER M5 ;
        RECT  68.256 75.916 68.28 76 ;
    END
  END dout[482]
  PIN dout[483]
    DIRECTION OUTPUT ;
    USE SIGNAL ;
    PORT
      LAYER M5 ;
        RECT  69.024 75.916 69.048 76 ;
    END
  END dout[483]
  PIN dout[484]
    DIRECTION OUTPUT ;
    USE SIGNAL ;
    PORT
      LAYER M5 ;
        RECT  66.576 75.916 66.6 76 ;
    END
  END dout[484]
  PIN dout[485]
    DIRECTION OUTPUT ;
    USE SIGNAL ;
    PORT
      LAYER M5 ;
        RECT  65.232 75.916 65.256 76 ;
    END
  END dout[485]
  PIN dout[486]
    DIRECTION OUTPUT ;
    USE SIGNAL ;
    PORT
      LAYER M5 ;
        RECT  67.872 75.916 67.896 76 ;
    END
  END dout[486]
  PIN dout[487]
    DIRECTION OUTPUT ;
    USE SIGNAL ;
    PORT
      LAYER M5 ;
        RECT  66.864 75.916 66.888 76 ;
    END
  END dout[487]
  PIN dout[488]
    DIRECTION OUTPUT ;
    USE SIGNAL ;
    PORT
      LAYER M5 ;
        RECT  67.248 75.916 67.272 76 ;
    END
  END dout[488]
  PIN dout[489]
    DIRECTION OUTPUT ;
    USE SIGNAL ;
    PORT
      LAYER M5 ;
        RECT  67.104 75.916 67.128 76 ;
    END
  END dout[489]
  PIN dout[48]
    DIRECTION OUTPUT ;
    USE SIGNAL ;
    PORT
      LAYER M5 ;
        RECT  18.048 75.916 18.072 76 ;
    END
  END dout[48]
  PIN dout[490]
    DIRECTION OUTPUT ;
    USE SIGNAL ;
    PORT
      LAYER M5 ;
        RECT  65.472 75.916 65.496 76 ;
    END
  END dout[490]
  PIN dout[491]
    DIRECTION OUTPUT ;
    USE SIGNAL ;
    PORT
      LAYER M5 ;
        RECT  66.384 75.916 66.408 76 ;
    END
  END dout[491]
  PIN dout[492]
    DIRECTION OUTPUT ;
    USE SIGNAL ;
    PORT
      LAYER M5 ;
        RECT  66.816 75.916 66.84 76 ;
    END
  END dout[492]
  PIN dout[493]
    DIRECTION OUTPUT ;
    USE SIGNAL ;
    PORT
      LAYER M5 ;
        RECT  65.376 75.916 65.4 76 ;
    END
  END dout[493]
  PIN dout[494]
    DIRECTION OUTPUT ;
    USE SIGNAL ;
    PORT
      LAYER M5 ;
        RECT  65.04 75.916 65.064 76 ;
    END
  END dout[494]
  PIN dout[495]
    DIRECTION OUTPUT ;
    USE SIGNAL ;
    PORT
      LAYER M5 ;
        RECT  63.888 75.916 63.912 76 ;
    END
  END dout[495]
  PIN dout[496]
    DIRECTION OUTPUT ;
    USE SIGNAL ;
    PORT
      LAYER M5 ;
        RECT  67.056 75.916 67.08 76 ;
    END
  END dout[496]
  PIN dout[497]
    DIRECTION OUTPUT ;
    USE SIGNAL ;
    PORT
      LAYER M5 ;
        RECT  66.672 75.916 66.696 76 ;
    END
  END dout[497]
  PIN dout[498]
    DIRECTION OUTPUT ;
    USE SIGNAL ;
    PORT
      LAYER M5 ;
        RECT  66.336 75.916 66.36 76 ;
    END
  END dout[498]
  PIN dout[499]
    DIRECTION OUTPUT ;
    USE SIGNAL ;
    PORT
      LAYER M7 ;
        RECT  60.352 75.931 60.384 76 ;
    END
  END dout[499]
  PIN dout[49]
    DIRECTION OUTPUT ;
    USE SIGNAL ;
    PORT
      LAYER M7 ;
        RECT  37.312 75.931 37.344 76 ;
    END
  END dout[49]
  PIN dout[4]
    DIRECTION OUTPUT ;
    USE SIGNAL ;
    PORT
      LAYER M7 ;
        RECT  38.336 75.931 38.368 76 ;
    END
  END dout[4]
  PIN dout[500]
    DIRECTION OUTPUT ;
    USE SIGNAL ;
    PORT
      LAYER M5 ;
        RECT  64.32 75.916 64.344 76 ;
    END
  END dout[500]
  PIN dout[501]
    DIRECTION OUTPUT ;
    USE SIGNAL ;
    PORT
      LAYER M7 ;
        RECT  59.008 75.931 59.04 76 ;
    END
  END dout[501]
  PIN dout[502]
    DIRECTION OUTPUT ;
    USE SIGNAL ;
    PORT
      LAYER M7 ;
        RECT  63.04 75.931 63.072 76 ;
    END
  END dout[502]
  PIN dout[503]
    DIRECTION OUTPUT ;
    USE SIGNAL ;
    PORT
      LAYER M5 ;
        RECT  66 75.916 66.024 76 ;
    END
  END dout[503]
  PIN dout[504]
    DIRECTION OUTPUT ;
    USE SIGNAL ;
    PORT
      LAYER M7 ;
        RECT  61.888 75.931 61.92 76 ;
    END
  END dout[504]
  PIN dout[505]
    DIRECTION OUTPUT ;
    USE SIGNAL ;
    PORT
      LAYER M5 ;
        RECT  64.368 75.916 64.392 76 ;
    END
  END dout[505]
  PIN dout[506]
    DIRECTION OUTPUT ;
    USE SIGNAL ;
    PORT
      LAYER M5 ;
        RECT  64.512 75.916 64.536 76 ;
    END
  END dout[506]
  PIN dout[507]
    DIRECTION OUTPUT ;
    USE SIGNAL ;
    PORT
      LAYER M5 ;
        RECT  64.752 75.916 64.776 76 ;
    END
  END dout[507]
  PIN dout[508]
    DIRECTION OUTPUT ;
    USE SIGNAL ;
    PORT
      LAYER M5 ;
        RECT  65.712 75.916 65.736 76 ;
    END
  END dout[508]
  PIN dout[509]
    DIRECTION OUTPUT ;
    USE SIGNAL ;
    PORT
      LAYER M5 ;
        RECT  67.392 75.916 67.416 76 ;
    END
  END dout[509]
  PIN dout[50]
    DIRECTION OUTPUT ;
    USE SIGNAL ;
    PORT
      LAYER M7 ;
        RECT  36.864 75.931 36.896 76 ;
    END
  END dout[50]
  PIN dout[510]
    DIRECTION OUTPUT ;
    USE SIGNAL ;
    PORT
      LAYER M5 ;
        RECT  65.856 75.916 65.88 76 ;
    END
  END dout[510]
  PIN dout[511]
    DIRECTION OUTPUT ;
    USE SIGNAL ;
    PORT
      LAYER M5 ;
        RECT  68.352 75.916 68.376 76 ;
    END
  END dout[511]
  PIN dout[512]
    DIRECTION OUTPUT ;
    USE SIGNAL ;
    PORT
      LAYER M5 ;
        RECT  66.048 75.916 66.072 76 ;
    END
  END dout[512]
  PIN dout[513]
    DIRECTION OUTPUT ;
    USE SIGNAL ;
    PORT
      LAYER M7 ;
        RECT  62.72 75.931 62.752 76 ;
    END
  END dout[513]
  PIN dout[514]
    DIRECTION OUTPUT ;
    USE SIGNAL ;
    PORT
      LAYER M7 ;
        RECT  63.232 75.931 63.264 76 ;
    END
  END dout[514]
  PIN dout[515]
    DIRECTION OUTPUT ;
    USE SIGNAL ;
    PORT
      LAYER M7 ;
        RECT  62.656 75.931 62.688 76 ;
    END
  END dout[515]
  PIN dout[516]
    DIRECTION OUTPUT ;
    USE SIGNAL ;
    PORT
      LAYER M5 ;
        RECT  64.944 75.916 64.968 76 ;
    END
  END dout[516]
  PIN dout[517]
    DIRECTION OUTPUT ;
    USE SIGNAL ;
    PORT
      LAYER M7 ;
        RECT  60.544 75.931 60.576 76 ;
    END
  END dout[517]
  PIN dout[518]
    DIRECTION OUTPUT ;
    USE SIGNAL ;
    PORT
      LAYER M7 ;
        RECT  59.776 75.931 59.808 76 ;
    END
  END dout[518]
  PIN dout[519]
    DIRECTION OUTPUT ;
    USE SIGNAL ;
    PORT
      LAYER M7 ;
        RECT  61.44 75.931 61.472 76 ;
    END
  END dout[519]
  PIN dout[51]
    DIRECTION OUTPUT ;
    USE SIGNAL ;
    PORT
      LAYER M7 ;
        RECT  39.552 75.931 39.584 76 ;
    END
  END dout[51]
  PIN dout[520]
    DIRECTION OUTPUT ;
    USE SIGNAL ;
    PORT
      LAYER M7 ;
        RECT  59.904 75.931 59.936 76 ;
    END
  END dout[520]
  PIN dout[521]
    DIRECTION OUTPUT ;
    USE SIGNAL ;
    PORT
      LAYER M5 ;
        RECT  66.096 75.916 66.12 76 ;
    END
  END dout[521]
  PIN dout[522]
    DIRECTION OUTPUT ;
    USE SIGNAL ;
    PORT
      LAYER M5 ;
        RECT  66.768 75.916 66.792 76 ;
    END
  END dout[522]
  PIN dout[523]
    DIRECTION OUTPUT ;
    USE SIGNAL ;
    PORT
      LAYER M5 ;
        RECT  58.032 75.916 58.056 76 ;
    END
  END dout[523]
  PIN dout[524]
    DIRECTION OUTPUT ;
    USE SIGNAL ;
    PORT
      LAYER M5 ;
        RECT  58.464 75.916 58.488 76 ;
    END
  END dout[524]
  PIN dout[525]
    DIRECTION OUTPUT ;
    USE SIGNAL ;
    PORT
      LAYER M5 ;
        RECT  64.272 75.916 64.296 76 ;
    END
  END dout[525]
  PIN dout[526]
    DIRECTION OUTPUT ;
    USE SIGNAL ;
    PORT
      LAYER M5 ;
        RECT  67.968 75.916 67.992 76 ;
    END
  END dout[526]
  PIN dout[527]
    DIRECTION OUTPUT ;
    USE SIGNAL ;
    PORT
      LAYER M5 ;
        RECT  67.632 75.916 67.656 76 ;
    END
  END dout[527]
  PIN dout[528]
    DIRECTION OUTPUT ;
    USE SIGNAL ;
    PORT
      LAYER M5 ;
        RECT  46.032 75.916 46.056 76 ;
    END
  END dout[528]
  PIN dout[529]
    DIRECTION OUTPUT ;
    USE SIGNAL ;
    PORT
      LAYER M5 ;
        RECT  67.488 75.916 67.512 76 ;
    END
  END dout[529]
  PIN dout[52]
    DIRECTION OUTPUT ;
    USE SIGNAL ;
    PORT
      LAYER M7 ;
        RECT  41.792 75.931 41.824 76 ;
    END
  END dout[52]
  PIN dout[530]
    DIRECTION OUTPUT ;
    USE SIGNAL ;
    PORT
      LAYER M5 ;
        RECT  67.824 75.916 67.848 76 ;
    END
  END dout[530]
  PIN dout[531]
    DIRECTION OUTPUT ;
    USE SIGNAL ;
    PORT
      LAYER M5 ;
        RECT  68.448 75.916 68.472 76 ;
    END
  END dout[531]
  PIN dout[532]
    DIRECTION OUTPUT ;
    USE SIGNAL ;
    PORT
      LAYER M5 ;
        RECT  65.616 75.916 65.64 76 ;
    END
  END dout[532]
  PIN dout[533]
    DIRECTION OUTPUT ;
    USE SIGNAL ;
    PORT
      LAYER M5 ;
        RECT  66.432 75.916 66.456 76 ;
    END
  END dout[533]
  PIN dout[534]
    DIRECTION OUTPUT ;
    USE SIGNAL ;
    PORT
      LAYER M5 ;
        RECT  65.424 75.916 65.448 76 ;
    END
  END dout[534]
  PIN dout[535]
    DIRECTION OUTPUT ;
    USE SIGNAL ;
    PORT
      LAYER M5 ;
        RECT  65.904 75.916 65.928 76 ;
    END
  END dout[535]
  PIN dout[536]
    DIRECTION OUTPUT ;
    USE SIGNAL ;
    PORT
      LAYER M5 ;
        RECT  66.144 75.916 66.168 76 ;
    END
  END dout[536]
  PIN dout[537]
    DIRECTION OUTPUT ;
    USE SIGNAL ;
    PORT
      LAYER M7 ;
        RECT  51.904 75.931 51.936 76 ;
    END
  END dout[537]
  PIN dout[538]
    DIRECTION OUTPUT ;
    USE SIGNAL ;
    PORT
      LAYER M5 ;
        RECT  54.048 75.916 54.072 76 ;
    END
  END dout[538]
  PIN dout[539]
    DIRECTION OUTPUT ;
    USE SIGNAL ;
    PORT
      LAYER M5 ;
        RECT  69.072 75.916 69.096 76 ;
    END
  END dout[539]
  PIN dout[53]
    DIRECTION OUTPUT ;
    USE SIGNAL ;
    PORT
      LAYER M7 ;
        RECT  41.472 75.931 41.504 76 ;
    END
  END dout[53]
  PIN dout[540]
    DIRECTION OUTPUT ;
    USE SIGNAL ;
    PORT
      LAYER M7 ;
        RECT  49.088 75.931 49.12 76 ;
    END
  END dout[540]
  PIN dout[541]
    DIRECTION OUTPUT ;
    USE SIGNAL ;
    PORT
      LAYER M7 ;
        RECT  51.328 75.931 51.36 76 ;
    END
  END dout[541]
  PIN dout[542]
    DIRECTION OUTPUT ;
    USE SIGNAL ;
    PORT
      LAYER M7 ;
        RECT  49.408 75.931 49.44 76 ;
    END
  END dout[542]
  PIN dout[543]
    DIRECTION OUTPUT ;
    USE SIGNAL ;
    PORT
      LAYER M7 ;
        RECT  48.384 75.931 48.416 76 ;
    END
  END dout[543]
  PIN dout[544]
    DIRECTION OUTPUT ;
    USE SIGNAL ;
    PORT
      LAYER M5 ;
        RECT  67.68 75.916 67.704 76 ;
    END
  END dout[544]
  PIN dout[545]
    DIRECTION OUTPUT ;
    USE SIGNAL ;
    PORT
      LAYER M7 ;
        RECT  50.816 75.931 50.848 76 ;
    END
  END dout[545]
  PIN dout[546]
    DIRECTION OUTPUT ;
    USE SIGNAL ;
    PORT
      LAYER M5 ;
        RECT  69.12 75.916 69.144 76 ;
    END
  END dout[546]
  PIN dout[547]
    DIRECTION OUTPUT ;
    USE SIGNAL ;
    PORT
      LAYER M5 ;
        RECT  57.744 75.916 57.768 76 ;
    END
  END dout[547]
  PIN dout[548]
    DIRECTION OUTPUT ;
    USE SIGNAL ;
    PORT
      LAYER M7 ;
        RECT  48.64 75.931 48.672 76 ;
    END
  END dout[548]
  PIN dout[549]
    DIRECTION OUTPUT ;
    USE SIGNAL ;
    PORT
      LAYER M7 ;
        RECT  48.96 75.931 48.992 76 ;
    END
  END dout[549]
  PIN dout[54]
    DIRECTION OUTPUT ;
    USE SIGNAL ;
    PORT
      LAYER M7 ;
        RECT  37.952 75.931 37.984 76 ;
    END
  END dout[54]
  PIN dout[550]
    DIRECTION OUTPUT ;
    USE SIGNAL ;
    PORT
      LAYER M5 ;
        RECT  47.328 75.916 47.352 76 ;
    END
  END dout[550]
  PIN dout[551]
    DIRECTION OUTPUT ;
    USE SIGNAL ;
    PORT
      LAYER M7 ;
        RECT  49.536 75.931 49.568 76 ;
    END
  END dout[551]
  PIN dout[552]
    DIRECTION OUTPUT ;
    USE SIGNAL ;
    PORT
      LAYER M7 ;
        RECT  51.456 75.931 51.488 76 ;
    END
  END dout[552]
  PIN dout[553]
    DIRECTION OUTPUT ;
    USE SIGNAL ;
    PORT
      LAYER M5 ;
        RECT  52.512 75.916 52.536 76 ;
    END
  END dout[553]
  PIN dout[554]
    DIRECTION OUTPUT ;
    USE SIGNAL ;
    PORT
      LAYER M7 ;
        RECT  49.28 75.931 49.312 76 ;
    END
  END dout[554]
  PIN dout[555]
    DIRECTION OUTPUT ;
    USE SIGNAL ;
    PORT
      LAYER M5 ;
        RECT  52.656 75.916 52.68 76 ;
    END
  END dout[555]
  PIN dout[556]
    DIRECTION OUTPUT ;
    USE SIGNAL ;
    PORT
      LAYER M7 ;
        RECT  49.152 75.931 49.184 76 ;
    END
  END dout[556]
  PIN dout[557]
    DIRECTION OUTPUT ;
    USE SIGNAL ;
    PORT
      LAYER M5 ;
        RECT  53.568 75.916 53.592 76 ;
    END
  END dout[557]
  PIN dout[558]
    DIRECTION OUTPUT ;
    USE SIGNAL ;
    PORT
      LAYER M5 ;
        RECT  63.696 75.916 63.72 76 ;
    END
  END dout[558]
  PIN dout[559]
    DIRECTION OUTPUT ;
    USE SIGNAL ;
    PORT
      LAYER M5 ;
        RECT  64.128 75.916 64.152 76 ;
    END
  END dout[559]
  PIN dout[55]
    DIRECTION OUTPUT ;
    USE SIGNAL ;
    PORT
      LAYER M7 ;
        RECT  37.632 75.931 37.664 76 ;
    END
  END dout[55]
  PIN dout[56]
    DIRECTION OUTPUT ;
    USE SIGNAL ;
    PORT
      LAYER M7 ;
        RECT  42.112 75.931 42.144 76 ;
    END
  END dout[56]
  PIN dout[57]
    DIRECTION OUTPUT ;
    USE SIGNAL ;
    PORT
      LAYER M7 ;
        RECT  42.176 75.931 42.208 76 ;
    END
  END dout[57]
  PIN dout[58]
    DIRECTION OUTPUT ;
    USE SIGNAL ;
    PORT
      LAYER M7 ;
        RECT  40.064 75.931 40.096 76 ;
    END
  END dout[58]
  PIN dout[59]
    DIRECTION OUTPUT ;
    USE SIGNAL ;
    PORT
      LAYER M7 ;
        RECT  36.48 75.931 36.512 76 ;
    END
  END dout[59]
  PIN dout[5]
    DIRECTION OUTPUT ;
    USE SIGNAL ;
    PORT
      LAYER M7 ;
        RECT  36.608 75.931 36.64 76 ;
    END
  END dout[5]
  PIN dout[60]
    DIRECTION OUTPUT ;
    USE SIGNAL ;
    PORT
      LAYER M7 ;
        RECT  40.192 75.931 40.224 76 ;
    END
  END dout[60]
  PIN dout[61]
    DIRECTION OUTPUT ;
    USE SIGNAL ;
    PORT
      LAYER M7 ;
        RECT  41.28 75.931 41.312 76 ;
    END
  END dout[61]
  PIN dout[62]
    DIRECTION OUTPUT ;
    USE SIGNAL ;
    PORT
      LAYER M7 ;
        RECT  40.384 75.931 40.416 76 ;
    END
  END dout[62]
  PIN dout[63]
    DIRECTION OUTPUT ;
    USE SIGNAL ;
    PORT
      LAYER M7 ;
        RECT  41.024 75.931 41.056 76 ;
    END
  END dout[63]
  PIN dout[64]
    DIRECTION OUTPUT ;
    USE SIGNAL ;
    PORT
      LAYER M7 ;
        RECT  21.248 75.931 21.28 76 ;
    END
  END dout[64]
  PIN dout[65]
    DIRECTION OUTPUT ;
    USE SIGNAL ;
    PORT
      LAYER M5 ;
        RECT  29.664 75.916 29.688 76 ;
    END
  END dout[65]
  PIN dout[66]
    DIRECTION OUTPUT ;
    USE SIGNAL ;
    PORT
      LAYER M5 ;
        RECT  17.76 75.916 17.784 76 ;
    END
  END dout[66]
  PIN dout[67]
    DIRECTION OUTPUT ;
    USE SIGNAL ;
    PORT
      LAYER M5 ;
        RECT  29.28 75.916 29.304 76 ;
    END
  END dout[67]
  PIN dout[68]
    DIRECTION OUTPUT ;
    USE SIGNAL ;
    PORT
      LAYER M7 ;
        RECT  10.048 75.931 10.08 76 ;
    END
  END dout[68]
  PIN dout[69]
    DIRECTION OUTPUT ;
    USE SIGNAL ;
    PORT
      LAYER M7 ;
        RECT  11.456 75.931 11.488 76 ;
    END
  END dout[69]
  PIN dout[6]
    DIRECTION OUTPUT ;
    USE SIGNAL ;
    PORT
      LAYER M7 ;
        RECT  36.416 75.931 36.448 76 ;
    END
  END dout[6]
  PIN dout[70]
    DIRECTION OUTPUT ;
    USE SIGNAL ;
    PORT
      LAYER M7 ;
        RECT  12.352 75.931 12.384 76 ;
    END
  END dout[70]
  PIN dout[71]
    DIRECTION OUTPUT ;
    USE SIGNAL ;
    PORT
      LAYER M7 ;
        RECT  9.28 75.931 9.312 76 ;
    END
  END dout[71]
  PIN dout[72]
    DIRECTION OUTPUT ;
    USE SIGNAL ;
    PORT
      LAYER M7 ;
        RECT  10.688 75.931 10.72 76 ;
    END
  END dout[72]
  PIN dout[73]
    DIRECTION OUTPUT ;
    USE SIGNAL ;
    PORT
      LAYER M7 ;
        RECT  10.176 75.931 10.208 76 ;
    END
  END dout[73]
  PIN dout[74]
    DIRECTION OUTPUT ;
    USE SIGNAL ;
    PORT
      LAYER M7 ;
        RECT  22.592 75.931 22.624 76 ;
    END
  END dout[74]
  PIN dout[75]
    DIRECTION OUTPUT ;
    USE SIGNAL ;
    PORT
      LAYER M5 ;
        RECT  17.04 75.916 17.064 76 ;
    END
  END dout[75]
  PIN dout[76]
    DIRECTION OUTPUT ;
    USE SIGNAL ;
    PORT
      LAYER M5 ;
        RECT  15.36 75.916 15.384 76 ;
    END
  END dout[76]
  PIN dout[77]
    DIRECTION OUTPUT ;
    USE SIGNAL ;
    PORT
      LAYER M5 ;
        RECT  7.248 75.916 7.272 76 ;
    END
  END dout[77]
  PIN dout[78]
    DIRECTION OUTPUT ;
    USE SIGNAL ;
    PORT
      LAYER M5 ;
        RECT  26.544 75.916 26.568 76 ;
    END
  END dout[78]
  PIN dout[79]
    DIRECTION OUTPUT ;
    USE SIGNAL ;
    PORT
      LAYER M5 ;
        RECT  27.984 75.916 28.008 76 ;
    END
  END dout[79]
  PIN dout[7]
    DIRECTION OUTPUT ;
    USE SIGNAL ;
    PORT
      LAYER M5 ;
        RECT  41.376 75.916 41.4 76 ;
    END
  END dout[7]
  PIN dout[80]
    DIRECTION OUTPUT ;
    USE SIGNAL ;
    PORT
      LAYER M5 ;
        RECT  6.768 75.916 6.792 76 ;
    END
  END dout[80]
  PIN dout[81]
    DIRECTION OUTPUT ;
    USE SIGNAL ;
    PORT
      LAYER M5 ;
        RECT  7.584 75.916 7.608 76 ;
    END
  END dout[81]
  PIN dout[82]
    DIRECTION OUTPUT ;
    USE SIGNAL ;
    PORT
      LAYER M7 ;
        RECT  3.84 75.931 3.872 76 ;
    END
  END dout[82]
  PIN dout[83]
    DIRECTION OUTPUT ;
    USE SIGNAL ;
    PORT
      LAYER M7 ;
        RECT  2.752 75.931 2.784 76 ;
    END
  END dout[83]
  PIN dout[84]
    DIRECTION OUTPUT ;
    USE SIGNAL ;
    PORT
      LAYER M5 ;
        RECT  5.136 75.916 5.16 76 ;
    END
  END dout[84]
  PIN dout[85]
    DIRECTION OUTPUT ;
    USE SIGNAL ;
    PORT
      LAYER M5 ;
        RECT  7.296 75.916 7.32 76 ;
    END
  END dout[85]
  PIN dout[86]
    DIRECTION OUTPUT ;
    USE SIGNAL ;
    PORT
      LAYER M5 ;
        RECT  6.192 75.916 6.216 76 ;
    END
  END dout[86]
  PIN dout[87]
    DIRECTION OUTPUT ;
    USE SIGNAL ;
    PORT
      LAYER M7 ;
        RECT  4.864 75.931 4.896 76 ;
    END
  END dout[87]
  PIN dout[88]
    DIRECTION OUTPUT ;
    USE SIGNAL ;
    PORT
      LAYER M7 ;
        RECT  3.776 75.931 3.808 76 ;
    END
  END dout[88]
  PIN dout[89]
    DIRECTION OUTPUT ;
    USE SIGNAL ;
    PORT
      LAYER M7 ;
        RECT  4.16 75.931 4.192 76 ;
    END
  END dout[89]
  PIN dout[8]
    DIRECTION OUTPUT ;
    USE SIGNAL ;
    PORT
      LAYER M5 ;
        RECT  26.976 75.916 27 76 ;
    END
  END dout[8]
  PIN dout[90]
    DIRECTION OUTPUT ;
    USE SIGNAL ;
    PORT
      LAYER M5 ;
        RECT  5.376 75.916 5.4 76 ;
    END
  END dout[90]
  PIN dout[91]
    DIRECTION OUTPUT ;
    USE SIGNAL ;
    PORT
      LAYER M7 ;
        RECT  4.352 75.931 4.384 76 ;
    END
  END dout[91]
  PIN dout[92]
    DIRECTION OUTPUT ;
    USE SIGNAL ;
    PORT
      LAYER M5 ;
        RECT  5.952 75.916 5.976 76 ;
    END
  END dout[92]
  PIN dout[93]
    DIRECTION OUTPUT ;
    USE SIGNAL ;
    PORT
      LAYER M5 ;
        RECT  6.384 75.916 6.408 76 ;
    END
  END dout[93]
  PIN dout[94]
    DIRECTION OUTPUT ;
    USE SIGNAL ;
    PORT
      LAYER M7 ;
        RECT  4.288 75.931 4.32 76 ;
    END
  END dout[94]
  PIN dout[95]
    DIRECTION OUTPUT ;
    USE SIGNAL ;
    PORT
      LAYER M5 ;
        RECT  5.088 75.916 5.112 76 ;
    END
  END dout[95]
  PIN dout[96]
    DIRECTION OUTPUT ;
    USE SIGNAL ;
    PORT
      LAYER M5 ;
        RECT  7.152 75.916 7.176 76 ;
    END
  END dout[96]
  PIN dout[97]
    DIRECTION OUTPUT ;
    USE SIGNAL ;
    PORT
      LAYER M5 ;
        RECT  7.632 75.916 7.656 76 ;
    END
  END dout[97]
  PIN dout[98]
    DIRECTION OUTPUT ;
    USE SIGNAL ;
    PORT
      LAYER M7 ;
        RECT  3.648 75.931 3.68 76 ;
    END
  END dout[98]
  PIN dout[99]
    DIRECTION OUTPUT ;
    USE SIGNAL ;
    PORT
      LAYER M5 ;
        RECT  6.288 75.916 6.312 76 ;
    END
  END dout[99]
  PIN dout[9]
    DIRECTION OUTPUT ;
    USE SIGNAL ;
    PORT
      LAYER M5 ;
        RECT  8.16 75.916 8.184 76 ;
    END
  END dout[9]
  PIN go_check
    DIRECTION INPUT ;
    USE SIGNAL ;
    PORT
      LAYER M5 ;
        RECT  29.52 0 29.544 0.084 ;
    END
  END go_check
  PIN go_commit
    DIRECTION INPUT ;
    USE SIGNAL ;
    PORT
      LAYER M5 ;
        RECT  29.568 0 29.592 0.084 ;
    END
  END go_commit
  PIN go_repair
    DIRECTION INPUT ;
    USE SIGNAL ;
    PORT
      LAYER M5 ;
        RECT  29.616 0 29.64 0.084 ;
    END
  END go_repair
  PIN go_sel
    DIRECTION INPUT ;
    USE SIGNAL ;
    PORT
      LAYER M5 ;
        RECT  29.664 0 29.688 0.084 ;
    END
  END go_sel
  PIN gr
    DIRECTION INPUT ;
    USE SIGNAL ;
    PORT
      LAYER M5 ;
        RECT  21.312 0 21.336 0.084 ;
    END
  END gr
  PIN grc_o[0]
    DIRECTION OUTPUT ;
    USE SIGNAL ;
    PORT
      LAYER M5 ;
        RECT  13.344 0 13.368 0.084 ;
    END
  END grc_o[0]
  PIN grc_o[1]
    DIRECTION OUTPUT ;
    USE SIGNAL ;
    PORT
      LAYER M5 ;
        RECT  10.32 0 10.344 0.084 ;
    END
  END grc_o[1]
  PIN grc_o[2]
    DIRECTION OUTPUT ;
    USE SIGNAL ;
    PORT
      LAYER M5 ;
        RECT  23.04 0 23.064 0.084 ;
    END
  END grc_o[2]
  PIN grc_o[3]
    DIRECTION OUTPUT ;
    USE SIGNAL ;
    PORT
      LAYER M5 ;
        RECT  41.616 0 41.64 0.084 ;
    END
  END grc_o[3]
  PIN grc_o[4]
    DIRECTION OUTPUT ;
    USE SIGNAL ;
    PORT
      LAYER M5 ;
        RECT  42.864 0 42.888 0.084 ;
    END
  END grc_o[4]
  PIN ph4[0]
    DIRECTION INPUT ;
    USE SIGNAL ;
    PORT
      LAYER M5 ;
        RECT  36.384 0 36.408 0.084 ;
    END
  END ph4[0]
  PIN ph4[1]
    DIRECTION INPUT ;
    USE SIGNAL ;
    PORT
      LAYER M5 ;
        RECT  29.712 0 29.736 0.084 ;
    END
  END ph4[1]
  PIN ph4[2]
    DIRECTION INPUT ;
    USE SIGNAL ;
    PORT
      LAYER M5 ;
        RECT  36.48 0 36.504 0.084 ;
    END
  END ph4[2]
  PIN ph4[3]
    DIRECTION INPUT ;
    USE SIGNAL ;
    PORT
      LAYER M5 ;
        RECT  29.76 0 29.784 0.084 ;
    END
  END ph4[3]
  PIN q[0]
    DIRECTION OUTPUT ;
    USE SIGNAL ;
    PORT
      LAYER M5 ;
        RECT  37.824 0 37.848 0.084 ;
    END
  END q[0]
  PIN q[100]
    DIRECTION OUTPUT ;
    USE SIGNAL ;
    PORT
      LAYER M5 ;
        RECT  2.64 0 2.664 0.084 ;
    END
  END q[100]
  PIN q[101]
    DIRECTION OUTPUT ;
    USE SIGNAL ;
    PORT
      LAYER M5 ;
        RECT  2.688 0 2.712 0.084 ;
    END
  END q[101]
  PIN q[102]
    DIRECTION OUTPUT ;
    USE SIGNAL ;
    PORT
      LAYER M7 ;
        RECT  6.848 0 6.88 0.069 ;
    END
  END q[102]
  PIN q[103]
    DIRECTION OUTPUT ;
    USE SIGNAL ;
    PORT
      LAYER M7 ;
        RECT  8.384 0 8.416 0.069 ;
    END
  END q[103]
  PIN q[104]
    DIRECTION OUTPUT ;
    USE SIGNAL ;
    PORT
      LAYER M7 ;
        RECT  7.232 0 7.264 0.069 ;
    END
  END q[104]
  PIN q[105]
    DIRECTION OUTPUT ;
    USE SIGNAL ;
    PORT
      LAYER M7 ;
        RECT  9.92 0 9.952 0.069 ;
    END
  END q[105]
  PIN q[106]
    DIRECTION OUTPUT ;
    USE SIGNAL ;
    PORT
      LAYER M5 ;
        RECT  16.512 0 16.536 0.084 ;
    END
  END q[106]
  PIN q[107]
    DIRECTION OUTPUT ;
    USE SIGNAL ;
    PORT
      LAYER M5 ;
        RECT  14.496 0 14.52 0.084 ;
    END
  END q[107]
  PIN q[108]
    DIRECTION OUTPUT ;
    USE SIGNAL ;
    PORT
      LAYER M5 ;
        RECT  1.776 0 1.8 0.084 ;
    END
  END q[108]
  PIN q[109]
    DIRECTION OUTPUT ;
    USE SIGNAL ;
    PORT
      LAYER M5 ;
        RECT  16.32 0 16.344 0.084 ;
    END
  END q[109]
  PIN q[10]
    DIRECTION OUTPUT ;
    USE SIGNAL ;
    PORT
      LAYER M5 ;
        RECT  40.896 0 40.92 0.084 ;
    END
  END q[10]
  PIN q[110]
    DIRECTION OUTPUT ;
    USE SIGNAL ;
    PORT
      LAYER M7 ;
        RECT  10.048 0 10.08 0.069 ;
    END
  END q[110]
  PIN q[111]
    DIRECTION OUTPUT ;
    USE SIGNAL ;
    PORT
      LAYER M5 ;
        RECT  13.584 0 13.608 0.084 ;
    END
  END q[111]
  PIN q[112]
    DIRECTION OUTPUT ;
    USE SIGNAL ;
    PORT
      LAYER M5 ;
        RECT  14.112 0 14.136 0.084 ;
    END
  END q[112]
  PIN q[113]
    DIRECTION OUTPUT ;
    USE SIGNAL ;
    PORT
      LAYER M5 ;
        RECT  15.072 0 15.096 0.084 ;
    END
  END q[113]
  PIN q[114]
    DIRECTION OUTPUT ;
    USE SIGNAL ;
    PORT
      LAYER M5 ;
        RECT  15.408 0 15.432 0.084 ;
    END
  END q[114]
  PIN q[115]
    DIRECTION OUTPUT ;
    USE SIGNAL ;
    PORT
      LAYER M7 ;
        RECT  19.328 0 19.36 0.069 ;
    END
  END q[115]
  PIN q[116]
    DIRECTION OUTPUT ;
    USE SIGNAL ;
    PORT
      LAYER M5 ;
        RECT  12.816 0 12.84 0.084 ;
    END
  END q[116]
  PIN q[117]
    DIRECTION OUTPUT ;
    USE SIGNAL ;
    PORT
      LAYER M7 ;
        RECT  18.496 0 18.528 0.069 ;
    END
  END q[117]
  PIN q[118]
    DIRECTION OUTPUT ;
    USE SIGNAL ;
    PORT
      LAYER M5 ;
        RECT  15.024 0 15.048 0.084 ;
    END
  END q[118]
  PIN q[119]
    DIRECTION OUTPUT ;
    USE SIGNAL ;
    PORT
      LAYER M7 ;
        RECT  33.344 0 33.376 0.069 ;
    END
  END q[119]
  PIN q[11]
    DIRECTION OUTPUT ;
    USE SIGNAL ;
    PORT
      LAYER M5 ;
        RECT  36.912 0 36.936 0.084 ;
    END
  END q[11]
  PIN q[120]
    DIRECTION OUTPUT ;
    USE SIGNAL ;
    PORT
      LAYER M5 ;
        RECT  22.608 0 22.632 0.084 ;
    END
  END q[120]
  PIN q[121]
    DIRECTION OUTPUT ;
    USE SIGNAL ;
    PORT
      LAYER M5 ;
        RECT  26.016 0 26.04 0.084 ;
    END
  END q[121]
  PIN q[122]
    DIRECTION OUTPUT ;
    USE SIGNAL ;
    PORT
      LAYER M5 ;
        RECT  23.52 0 23.544 0.084 ;
    END
  END q[122]
  PIN q[123]
    DIRECTION OUTPUT ;
    USE SIGNAL ;
    PORT
      LAYER M5 ;
        RECT  26.592 0 26.616 0.084 ;
    END
  END q[123]
  PIN q[124]
    DIRECTION OUTPUT ;
    USE SIGNAL ;
    PORT
      LAYER M7 ;
        RECT  30.656 0 30.688 0.069 ;
    END
  END q[124]
  PIN q[125]
    DIRECTION OUTPUT ;
    USE SIGNAL ;
    PORT
      LAYER M5 ;
        RECT  16.848 0 16.872 0.084 ;
    END
  END q[125]
  PIN q[126]
    DIRECTION OUTPUT ;
    USE SIGNAL ;
    PORT
      LAYER M7 ;
        RECT  28.864 0 28.896 0.069 ;
    END
  END q[126]
  PIN q[127]
    DIRECTION OUTPUT ;
    USE SIGNAL ;
    PORT
      LAYER M7 ;
        RECT  32.768 0 32.8 0.069 ;
    END
  END q[127]
  PIN q[128]
    DIRECTION OUTPUT ;
    USE SIGNAL ;
    PORT
      LAYER M7 ;
        RECT  45.76 0 45.792 0.069 ;
    END
  END q[128]
  PIN q[129]
    DIRECTION OUTPUT ;
    USE SIGNAL ;
    PORT
      LAYER M7 ;
        RECT  45.248 0 45.28 0.069 ;
    END
  END q[129]
  PIN q[12]
    DIRECTION OUTPUT ;
    USE SIGNAL ;
    PORT
      LAYER M5 ;
        RECT  37.968 0 37.992 0.084 ;
    END
  END q[12]
  PIN q[130]
    DIRECTION OUTPUT ;
    USE SIGNAL ;
    PORT
      LAYER M5 ;
        RECT  44.4 0 44.424 0.084 ;
    END
  END q[130]
  PIN q[131]
    DIRECTION OUTPUT ;
    USE SIGNAL ;
    PORT
      LAYER M7 ;
        RECT  45.568 0 45.6 0.069 ;
    END
  END q[131]
  PIN q[132]
    DIRECTION OUTPUT ;
    USE SIGNAL ;
    PORT
      LAYER M5 ;
        RECT  39.12 0 39.144 0.084 ;
    END
  END q[132]
  PIN q[133]
    DIRECTION OUTPUT ;
    USE SIGNAL ;
    PORT
      LAYER M5 ;
        RECT  42.432 0 42.456 0.084 ;
    END
  END q[133]
  PIN q[134]
    DIRECTION OUTPUT ;
    USE SIGNAL ;
    PORT
      LAYER M5 ;
        RECT  44.112 0 44.136 0.084 ;
    END
  END q[134]
  PIN q[135]
    DIRECTION OUTPUT ;
    USE SIGNAL ;
    PORT
      LAYER M5 ;
        RECT  42.528 0 42.552 0.084 ;
    END
  END q[135]
  PIN q[136]
    DIRECTION OUTPUT ;
    USE SIGNAL ;
    PORT
      LAYER M5 ;
        RECT  42 0 42.024 0.084 ;
    END
  END q[136]
  PIN q[137]
    DIRECTION OUTPUT ;
    USE SIGNAL ;
    PORT
      LAYER M5 ;
        RECT  42.576 0 42.6 0.084 ;
    END
  END q[137]
  PIN q[138]
    DIRECTION OUTPUT ;
    USE SIGNAL ;
    PORT
      LAYER M5 ;
        RECT  42.624 0 42.648 0.084 ;
    END
  END q[138]
  PIN q[139]
    DIRECTION OUTPUT ;
    USE SIGNAL ;
    PORT
      LAYER M5 ;
        RECT  39.744 0 39.768 0.084 ;
    END
  END q[139]
  PIN q[13]
    DIRECTION OUTPUT ;
    USE SIGNAL ;
    PORT
      LAYER M5 ;
        RECT  38.928 0 38.952 0.084 ;
    END
  END q[13]
  PIN q[140]
    DIRECTION OUTPUT ;
    USE SIGNAL ;
    PORT
      LAYER M5 ;
        RECT  42.24 0 42.264 0.084 ;
    END
  END q[140]
  PIN q[141]
    DIRECTION OUTPUT ;
    USE SIGNAL ;
    PORT
      LAYER M7 ;
        RECT  44.928 0 44.96 0.069 ;
    END
  END q[141]
  PIN q[142]
    DIRECTION OUTPUT ;
    USE SIGNAL ;
    PORT
      LAYER M5 ;
        RECT  40.656 0 40.68 0.084 ;
    END
  END q[142]
  PIN q[143]
    DIRECTION OUTPUT ;
    USE SIGNAL ;
    PORT
      LAYER M5 ;
        RECT  36.768 0 36.792 0.084 ;
    END
  END q[143]
  PIN q[144]
    DIRECTION OUTPUT ;
    USE SIGNAL ;
    PORT
      LAYER M5 ;
        RECT  41.904 0 41.928 0.084 ;
    END
  END q[144]
  PIN q[145]
    DIRECTION OUTPUT ;
    USE SIGNAL ;
    PORT
      LAYER M5 ;
        RECT  43.344 0 43.368 0.084 ;
    END
  END q[145]
  PIN q[146]
    DIRECTION OUTPUT ;
    USE SIGNAL ;
    PORT
      LAYER M5 ;
        RECT  42.384 0 42.408 0.084 ;
    END
  END q[146]
  PIN q[147]
    DIRECTION OUTPUT ;
    USE SIGNAL ;
    PORT
      LAYER M5 ;
        RECT  44.064 0 44.088 0.084 ;
    END
  END q[147]
  PIN q[148]
    DIRECTION OUTPUT ;
    USE SIGNAL ;
    PORT
      LAYER M7 ;
        RECT  45.696 0 45.728 0.069 ;
    END
  END q[148]
  PIN q[149]
    DIRECTION OUTPUT ;
    USE SIGNAL ;
    PORT
      LAYER M7 ;
        RECT  45.632 0 45.664 0.069 ;
    END
  END q[149]
  PIN q[14]
    DIRECTION OUTPUT ;
    USE SIGNAL ;
    PORT
      LAYER M5 ;
        RECT  37.632 0 37.656 0.084 ;
    END
  END q[14]
  PIN q[150]
    DIRECTION OUTPUT ;
    USE SIGNAL ;
    PORT
      LAYER M5 ;
        RECT  43.296 0 43.32 0.084 ;
    END
  END q[150]
  PIN q[151]
    DIRECTION OUTPUT ;
    USE SIGNAL ;
    PORT
      LAYER M7 ;
        RECT  45.952 0 45.984 0.069 ;
    END
  END q[151]
  PIN q[152]
    DIRECTION OUTPUT ;
    USE SIGNAL ;
    PORT
      LAYER M5 ;
        RECT  43.968 0 43.992 0.084 ;
    END
  END q[152]
  PIN q[153]
    DIRECTION OUTPUT ;
    USE SIGNAL ;
    PORT
      LAYER M5 ;
        RECT  44.832 0 44.856 0.084 ;
    END
  END q[153]
  PIN q[154]
    DIRECTION OUTPUT ;
    USE SIGNAL ;
    PORT
      LAYER M5 ;
        RECT  42.912 0 42.936 0.084 ;
    END
  END q[154]
  PIN q[155]
    DIRECTION OUTPUT ;
    USE SIGNAL ;
    PORT
      LAYER M5 ;
        RECT  40.752 0 40.776 0.084 ;
    END
  END q[155]
  PIN q[156]
    DIRECTION OUTPUT ;
    USE SIGNAL ;
    PORT
      LAYER M5 ;
        RECT  38.544 0 38.568 0.084 ;
    END
  END q[156]
  PIN q[157]
    DIRECTION OUTPUT ;
    USE SIGNAL ;
    PORT
      LAYER M5 ;
        RECT  44.304 0 44.328 0.084 ;
    END
  END q[157]
  PIN q[158]
    DIRECTION OUTPUT ;
    USE SIGNAL ;
    PORT
      LAYER M5 ;
        RECT  40.848 0 40.872 0.084 ;
    END
  END q[158]
  PIN q[159]
    DIRECTION OUTPUT ;
    USE SIGNAL ;
    PORT
      LAYER M7 ;
        RECT  30.784 0 30.816 0.069 ;
    END
  END q[159]
  PIN q[15]
    DIRECTION OUTPUT ;
    USE SIGNAL ;
    PORT
      LAYER M5 ;
        RECT  37.296 0 37.32 0.084 ;
    END
  END q[15]
  PIN q[160]
    DIRECTION OUTPUT ;
    USE SIGNAL ;
    PORT
      LAYER M5 ;
        RECT  37.392 0 37.416 0.084 ;
    END
  END q[160]
  PIN q[161]
    DIRECTION OUTPUT ;
    USE SIGNAL ;
    PORT
      LAYER M7 ;
        RECT  45.12 0 45.152 0.069 ;
    END
  END q[161]
  PIN q[162]
    DIRECTION OUTPUT ;
    USE SIGNAL ;
    PORT
      LAYER M5 ;
        RECT  42.96 0 42.984 0.084 ;
    END
  END q[162]
  PIN q[163]
    DIRECTION OUTPUT ;
    USE SIGNAL ;
    PORT
      LAYER M7 ;
        RECT  46.336 0 46.368 0.069 ;
    END
  END q[163]
  PIN q[164]
    DIRECTION OUTPUT ;
    USE SIGNAL ;
    PORT
      LAYER M5 ;
        RECT  43.152 0 43.176 0.084 ;
    END
  END q[164]
  PIN q[165]
    DIRECTION OUTPUT ;
    USE SIGNAL ;
    PORT
      LAYER M5 ;
        RECT  44.448 0 44.472 0.084 ;
    END
  END q[165]
  PIN q[166]
    DIRECTION OUTPUT ;
    USE SIGNAL ;
    PORT
      LAYER M5 ;
        RECT  37.488 0 37.512 0.084 ;
    END
  END q[166]
  PIN q[167]
    DIRECTION OUTPUT ;
    USE SIGNAL ;
    PORT
      LAYER M5 ;
        RECT  41.952 0 41.976 0.084 ;
    END
  END q[167]
  PIN q[168]
    DIRECTION OUTPUT ;
    USE SIGNAL ;
    PORT
      LAYER M5 ;
        RECT  39.984 0 40.008 0.084 ;
    END
  END q[168]
  PIN q[169]
    DIRECTION OUTPUT ;
    USE SIGNAL ;
    PORT
      LAYER M5 ;
        RECT  38.736 0 38.76 0.084 ;
    END
  END q[169]
  PIN q[16]
    DIRECTION OUTPUT ;
    USE SIGNAL ;
    PORT
      LAYER M5 ;
        RECT  34.8 0 34.824 0.084 ;
    END
  END q[16]
  PIN q[170]
    DIRECTION OUTPUT ;
    USE SIGNAL ;
    PORT
      LAYER M5 ;
        RECT  39.264 0 39.288 0.084 ;
    END
  END q[170]
  PIN q[171]
    DIRECTION OUTPUT ;
    USE SIGNAL ;
    PORT
      LAYER M5 ;
        RECT  44.16 0 44.184 0.084 ;
    END
  END q[171]
  PIN q[172]
    DIRECTION OUTPUT ;
    USE SIGNAL ;
    PORT
      LAYER M5 ;
        RECT  42.672 0 42.696 0.084 ;
    END
  END q[172]
  PIN q[173]
    DIRECTION OUTPUT ;
    USE SIGNAL ;
    PORT
      LAYER M7 ;
        RECT  22.016 0 22.048 0.069 ;
    END
  END q[173]
  PIN q[174]
    DIRECTION OUTPUT ;
    USE SIGNAL ;
    PORT
      LAYER M5 ;
        RECT  40.944 0 40.968 0.084 ;
    END
  END q[174]
  PIN q[175]
    DIRECTION OUTPUT ;
    USE SIGNAL ;
    PORT
      LAYER M5 ;
        RECT  35.952 0 35.976 0.084 ;
    END
  END q[175]
  PIN q[176]
    DIRECTION OUTPUT ;
    USE SIGNAL ;
    PORT
      LAYER M5 ;
        RECT  34.896 0 34.92 0.084 ;
    END
  END q[176]
  PIN q[177]
    DIRECTION OUTPUT ;
    USE SIGNAL ;
    PORT
      LAYER M7 ;
        RECT  46.208 0 46.24 0.069 ;
    END
  END q[177]
  PIN q[178]
    DIRECTION OUTPUT ;
    USE SIGNAL ;
    PORT
      LAYER M5 ;
        RECT  42.72 0 42.744 0.084 ;
    END
  END q[178]
  PIN q[179]
    DIRECTION OUTPUT ;
    USE SIGNAL ;
    PORT
      LAYER M5 ;
        RECT  38.448 0 38.472 0.084 ;
    END
  END q[179]
  PIN q[17]
    DIRECTION OUTPUT ;
    USE SIGNAL ;
    PORT
      LAYER M5 ;
        RECT  39.696 0 39.72 0.084 ;
    END
  END q[17]
  PIN q[180]
    DIRECTION OUTPUT ;
    USE SIGNAL ;
    PORT
      LAYER M5 ;
        RECT  36.528 0 36.552 0.084 ;
    END
  END q[180]
  PIN q[181]
    DIRECTION OUTPUT ;
    USE SIGNAL ;
    PORT
      LAYER M5 ;
        RECT  41.328 0 41.352 0.084 ;
    END
  END q[181]
  PIN q[182]
    DIRECTION OUTPUT ;
    USE SIGNAL ;
    PORT
      LAYER M5 ;
        RECT  40.608 0 40.632 0.084 ;
    END
  END q[182]
  PIN q[183]
    DIRECTION OUTPUT ;
    USE SIGNAL ;
    PORT
      LAYER M5 ;
        RECT  41.424 0 41.448 0.084 ;
    END
  END q[183]
  PIN q[184]
    DIRECTION OUTPUT ;
    USE SIGNAL ;
    PORT
      LAYER M5 ;
        RECT  37.248 0 37.272 0.084 ;
    END
  END q[184]
  PIN q[185]
    DIRECTION OUTPUT ;
    USE SIGNAL ;
    PORT
      LAYER M7 ;
        RECT  44.736 0 44.768 0.069 ;
    END
  END q[185]
  PIN q[186]
    DIRECTION OUTPUT ;
    USE SIGNAL ;
    PORT
      LAYER M7 ;
        RECT  45.888 0 45.92 0.069 ;
    END
  END q[186]
  PIN q[187]
    DIRECTION OUTPUT ;
    USE SIGNAL ;
    PORT
      LAYER M7 ;
        RECT  46.08 0 46.112 0.069 ;
    END
  END q[187]
  PIN q[188]
    DIRECTION OUTPUT ;
    USE SIGNAL ;
    PORT
      LAYER M7 ;
        RECT  46.016 0 46.048 0.069 ;
    END
  END q[188]
  PIN q[189]
    DIRECTION OUTPUT ;
    USE SIGNAL ;
    PORT
      LAYER M7 ;
        RECT  45.824 0 45.856 0.069 ;
    END
  END q[189]
  PIN q[18]
    DIRECTION OUTPUT ;
    USE SIGNAL ;
    PORT
      LAYER M7 ;
        RECT  31.424 0 31.456 0.069 ;
    END
  END q[18]
  PIN q[190]
    DIRECTION OUTPUT ;
    USE SIGNAL ;
    PORT
      LAYER M7 ;
        RECT  45.44 0 45.472 0.069 ;
    END
  END q[190]
  PIN q[191]
    DIRECTION OUTPUT ;
    USE SIGNAL ;
    PORT
      LAYER M5 ;
        RECT  44.736 0 44.76 0.084 ;
    END
  END q[191]
  PIN q[192]
    DIRECTION OUTPUT ;
    USE SIGNAL ;
    PORT
      LAYER M7 ;
        RECT  67.968 0 68 0.069 ;
    END
  END q[192]
  PIN q[193]
    DIRECTION OUTPUT ;
    USE SIGNAL ;
    PORT
      LAYER M7 ;
        RECT  67.264 0 67.296 0.069 ;
    END
  END q[193]
  PIN q[194]
    DIRECTION OUTPUT ;
    USE SIGNAL ;
    PORT
      LAYER M7 ;
        RECT  66.88 0 66.912 0.069 ;
    END
  END q[194]
  PIN q[195]
    DIRECTION OUTPUT ;
    USE SIGNAL ;
    PORT
      LAYER M7 ;
        RECT  65.344 0 65.376 0.069 ;
    END
  END q[195]
  PIN q[196]
    DIRECTION OUTPUT ;
    USE SIGNAL ;
    PORT
      LAYER M7 ;
        RECT  66.24 0 66.272 0.069 ;
    END
  END q[196]
  PIN q[197]
    DIRECTION OUTPUT ;
    USE SIGNAL ;
    PORT
      LAYER M7 ;
        RECT  67.904 0 67.936 0.069 ;
    END
  END q[197]
  PIN q[198]
    DIRECTION OUTPUT ;
    USE SIGNAL ;
    PORT
      LAYER M7 ;
        RECT  67.2 0 67.232 0.069 ;
    END
  END q[198]
  PIN q[199]
    DIRECTION OUTPUT ;
    USE SIGNAL ;
    PORT
      LAYER M7 ;
        RECT  67.776 0 67.808 0.069 ;
    END
  END q[199]
  PIN q[19]
    DIRECTION OUTPUT ;
    USE SIGNAL ;
    PORT
      LAYER M5 ;
        RECT  38.976 0 39 0.084 ;
    END
  END q[19]
  PIN q[1]
    DIRECTION OUTPUT ;
    USE SIGNAL ;
    PORT
      LAYER M5 ;
        RECT  24.336 0 24.36 0.084 ;
    END
  END q[1]
  PIN q[200]
    DIRECTION OUTPUT ;
    USE SIGNAL ;
    PORT
      LAYER M7 ;
        RECT  67.712 0 67.744 0.069 ;
    END
  END q[200]
  PIN q[201]
    DIRECTION OUTPUT ;
    USE SIGNAL ;
    PORT
      LAYER M7 ;
        RECT  67.648 0 67.68 0.069 ;
    END
  END q[201]
  PIN q[202]
    DIRECTION OUTPUT ;
    USE SIGNAL ;
    PORT
      LAYER M7 ;
        RECT  67.392 0 67.424 0.069 ;
    END
  END q[202]
  PIN q[203]
    DIRECTION OUTPUT ;
    USE SIGNAL ;
    PORT
      LAYER M7 ;
        RECT  67.84 0 67.872 0.069 ;
    END
  END q[203]
  PIN q[204]
    DIRECTION OUTPUT ;
    USE SIGNAL ;
    PORT
      LAYER M7 ;
        RECT  66.688 0 66.72 0.069 ;
    END
  END q[204]
  PIN q[205]
    DIRECTION OUTPUT ;
    USE SIGNAL ;
    PORT
      LAYER M7 ;
        RECT  65.152 0 65.184 0.069 ;
    END
  END q[205]
  PIN q[206]
    DIRECTION OUTPUT ;
    USE SIGNAL ;
    PORT
      LAYER M7 ;
        RECT  67.072 0 67.104 0.069 ;
    END
  END q[206]
  PIN q[207]
    DIRECTION OUTPUT ;
    USE SIGNAL ;
    PORT
      LAYER M7 ;
        RECT  66.368 0 66.4 0.069 ;
    END
  END q[207]
  PIN q[208]
    DIRECTION OUTPUT ;
    USE SIGNAL ;
    PORT
      LAYER M7 ;
        RECT  66.56 0 66.592 0.069 ;
    END
  END q[208]
  PIN q[209]
    DIRECTION OUTPUT ;
    USE SIGNAL ;
    PORT
      LAYER M7 ;
        RECT  66.048 0 66.08 0.069 ;
    END
  END q[209]
  PIN q[20]
    DIRECTION OUTPUT ;
    USE SIGNAL ;
    PORT
      LAYER M5 ;
        RECT  41.664 0 41.688 0.084 ;
    END
  END q[20]
  PIN q[210]
    DIRECTION OUTPUT ;
    USE SIGNAL ;
    PORT
      LAYER M7 ;
        RECT  65.088 0 65.12 0.069 ;
    END
  END q[210]
  PIN q[211]
    DIRECTION OUTPUT ;
    USE SIGNAL ;
    PORT
      LAYER M7 ;
        RECT  66.112 0 66.144 0.069 ;
    END
  END q[211]
  PIN q[212]
    DIRECTION OUTPUT ;
    USE SIGNAL ;
    PORT
      LAYER M7 ;
        RECT  66.944 0 66.976 0.069 ;
    END
  END q[212]
  PIN q[213]
    DIRECTION OUTPUT ;
    USE SIGNAL ;
    PORT
      LAYER M7 ;
        RECT  65.472 0 65.504 0.069 ;
    END
  END q[213]
  PIN q[214]
    DIRECTION OUTPUT ;
    USE SIGNAL ;
    PORT
      LAYER M7 ;
        RECT  65.408 0 65.44 0.069 ;
    END
  END q[214]
  PIN q[215]
    DIRECTION OUTPUT ;
    USE SIGNAL ;
    PORT
      LAYER M5 ;
        RECT  62.88 0 62.904 0.084 ;
    END
  END q[215]
  PIN q[216]
    DIRECTION OUTPUT ;
    USE SIGNAL ;
    PORT
      LAYER M7 ;
        RECT  66.176 0 66.208 0.069 ;
    END
  END q[216]
  PIN q[217]
    DIRECTION OUTPUT ;
    USE SIGNAL ;
    PORT
      LAYER M7 ;
        RECT  65.728 0 65.76 0.069 ;
    END
  END q[217]
  PIN q[218]
    DIRECTION OUTPUT ;
    USE SIGNAL ;
    PORT
      LAYER M7 ;
        RECT  65.28 0 65.312 0.069 ;
    END
  END q[218]
  PIN q[219]
    DIRECTION OUTPUT ;
    USE SIGNAL ;
    PORT
      LAYER M7 ;
        RECT  59.392 0 59.424 0.069 ;
    END
  END q[219]
  PIN q[21]
    DIRECTION OUTPUT ;
    USE SIGNAL ;
    PORT
      LAYER M5 ;
        RECT  35.808 0 35.832 0.084 ;
    END
  END q[21]
  PIN q[220]
    DIRECTION OUTPUT ;
    USE SIGNAL ;
    PORT
      LAYER M5 ;
        RECT  63.264 0 63.288 0.084 ;
    END
  END q[220]
  PIN q[221]
    DIRECTION OUTPUT ;
    USE SIGNAL ;
    PORT
      LAYER M7 ;
        RECT  57.92 0 57.952 0.069 ;
    END
  END q[221]
  PIN q[222]
    DIRECTION OUTPUT ;
    USE SIGNAL ;
    PORT
      LAYER M5 ;
        RECT  62.016 0 62.04 0.084 ;
    END
  END q[222]
  PIN q[223]
    DIRECTION OUTPUT ;
    USE SIGNAL ;
    PORT
      LAYER M7 ;
        RECT  65.92 0 65.952 0.069 ;
    END
  END q[223]
  PIN q[224]
    DIRECTION OUTPUT ;
    USE SIGNAL ;
    PORT
      LAYER M5 ;
        RECT  61.008 0 61.032 0.084 ;
    END
  END q[224]
  PIN q[225]
    DIRECTION OUTPUT ;
    USE SIGNAL ;
    PORT
      LAYER M5 ;
        RECT  63.408 0 63.432 0.084 ;
    END
  END q[225]
  PIN q[226]
    DIRECTION OUTPUT ;
    USE SIGNAL ;
    PORT
      LAYER M7 ;
        RECT  64.96 0 64.992 0.069 ;
    END
  END q[226]
  PIN q[227]
    DIRECTION OUTPUT ;
    USE SIGNAL ;
    PORT
      LAYER M5 ;
        RECT  64.416 0 64.44 0.084 ;
    END
  END q[227]
  PIN q[228]
    DIRECTION OUTPUT ;
    USE SIGNAL ;
    PORT
      LAYER M5 ;
        RECT  64.896 0 64.92 0.084 ;
    END
  END q[228]
  PIN q[229]
    DIRECTION OUTPUT ;
    USE SIGNAL ;
    PORT
      LAYER M7 ;
        RECT  66.816 0 66.848 0.069 ;
    END
  END q[229]
  PIN q[22]
    DIRECTION OUTPUT ;
    USE SIGNAL ;
    PORT
      LAYER M7 ;
        RECT  30.208 0 30.24 0.069 ;
    END
  END q[22]
  PIN q[230]
    DIRECTION OUTPUT ;
    USE SIGNAL ;
    PORT
      LAYER M5 ;
        RECT  64.752 0 64.776 0.084 ;
    END
  END q[230]
  PIN q[231]
    DIRECTION OUTPUT ;
    USE SIGNAL ;
    PORT
      LAYER M7 ;
        RECT  67.52 0 67.552 0.069 ;
    END
  END q[231]
  PIN q[232]
    DIRECTION OUTPUT ;
    USE SIGNAL ;
    PORT
      LAYER M7 ;
        RECT  65.216 0 65.248 0.069 ;
    END
  END q[232]
  PIN q[233]
    DIRECTION OUTPUT ;
    USE SIGNAL ;
    PORT
      LAYER M5 ;
        RECT  61.68 0 61.704 0.084 ;
    END
  END q[233]
  PIN q[234]
    DIRECTION OUTPUT ;
    USE SIGNAL ;
    PORT
      LAYER M5 ;
        RECT  62.304 0 62.328 0.084 ;
    END
  END q[234]
  PIN q[235]
    DIRECTION OUTPUT ;
    USE SIGNAL ;
    PORT
      LAYER M5 ;
        RECT  61.728 0 61.752 0.084 ;
    END
  END q[235]
  PIN q[236]
    DIRECTION OUTPUT ;
    USE SIGNAL ;
    PORT
      LAYER M5 ;
        RECT  63.984 0 64.008 0.084 ;
    END
  END q[236]
  PIN q[237]
    DIRECTION OUTPUT ;
    USE SIGNAL ;
    PORT
      LAYER M7 ;
        RECT  59.52 0 59.552 0.069 ;
    END
  END q[237]
  PIN q[238]
    DIRECTION OUTPUT ;
    USE SIGNAL ;
    PORT
      LAYER M7 ;
        RECT  58.88 0 58.912 0.069 ;
    END
  END q[238]
  PIN q[239]
    DIRECTION OUTPUT ;
    USE SIGNAL ;
    PORT
      LAYER M7 ;
        RECT  60.416 0 60.448 0.069 ;
    END
  END q[239]
  PIN q[23]
    DIRECTION OUTPUT ;
    USE SIGNAL ;
    PORT
      LAYER M7 ;
        RECT  29.376 0 29.408 0.069 ;
    END
  END q[23]
  PIN q[240]
    DIRECTION OUTPUT ;
    USE SIGNAL ;
    PORT
      LAYER M7 ;
        RECT  58.944 0 58.976 0.069 ;
    END
  END q[240]
  PIN q[241]
    DIRECTION OUTPUT ;
    USE SIGNAL ;
    PORT
      LAYER M7 ;
        RECT  65.792 0 65.824 0.069 ;
    END
  END q[241]
  PIN q[242]
    DIRECTION OUTPUT ;
    USE SIGNAL ;
    PORT
      LAYER M7 ;
        RECT  65.536 0 65.568 0.069 ;
    END
  END q[242]
  PIN q[243]
    DIRECTION OUTPUT ;
    USE SIGNAL ;
    PORT
      LAYER M7 ;
        RECT  57.152 0 57.184 0.069 ;
    END
  END q[243]
  PIN q[244]
    DIRECTION OUTPUT ;
    USE SIGNAL ;
    PORT
      LAYER M7 ;
        RECT  57.472 0 57.504 0.069 ;
    END
  END q[244]
  PIN q[245]
    DIRECTION OUTPUT ;
    USE SIGNAL ;
    PORT
      LAYER M5 ;
        RECT  63.312 0 63.336 0.084 ;
    END
  END q[245]
  PIN q[246]
    DIRECTION OUTPUT ;
    USE SIGNAL ;
    PORT
      LAYER M7 ;
        RECT  67.136 0 67.168 0.069 ;
    END
  END q[246]
  PIN q[247]
    DIRECTION OUTPUT ;
    USE SIGNAL ;
    PORT
      LAYER M7 ;
        RECT  67.328 0 67.36 0.069 ;
    END
  END q[247]
  PIN q[248]
    DIRECTION OUTPUT ;
    USE SIGNAL ;
    PORT
      LAYER M7 ;
        RECT  44.608 0 44.64 0.069 ;
    END
  END q[248]
  PIN q[249]
    DIRECTION OUTPUT ;
    USE SIGNAL ;
    PORT
      LAYER M7 ;
        RECT  66.624 0 66.656 0.069 ;
    END
  END q[249]
  PIN q[24]
    DIRECTION OUTPUT ;
    USE SIGNAL ;
    PORT
      LAYER M5 ;
        RECT  35.376 0 35.4 0.084 ;
    END
  END q[24]
  PIN q[250]
    DIRECTION OUTPUT ;
    USE SIGNAL ;
    PORT
      LAYER M7 ;
        RECT  67.456 0 67.488 0.069 ;
    END
  END q[250]
  PIN q[251]
    DIRECTION OUTPUT ;
    USE SIGNAL ;
    PORT
      LAYER M7 ;
        RECT  67.584 0 67.616 0.069 ;
    END
  END q[251]
  PIN q[252]
    DIRECTION OUTPUT ;
    USE SIGNAL ;
    PORT
      LAYER M5 ;
        RECT  64.704 0 64.728 0.084 ;
    END
  END q[252]
  PIN q[253]
    DIRECTION OUTPUT ;
    USE SIGNAL ;
    PORT
      LAYER M7 ;
        RECT  66.304 0 66.336 0.069 ;
    END
  END q[253]
  PIN q[254]
    DIRECTION OUTPUT ;
    USE SIGNAL ;
    PORT
      LAYER M7 ;
        RECT  66.432 0 66.464 0.069 ;
    END
  END q[254]
  PIN q[255]
    DIRECTION OUTPUT ;
    USE SIGNAL ;
    PORT
      LAYER M7 ;
        RECT  65.984 0 66.016 0.069 ;
    END
  END q[255]
  PIN q[256]
    DIRECTION OUTPUT ;
    USE SIGNAL ;
    PORT
      LAYER M7 ;
        RECT  65.024 0 65.056 0.069 ;
    END
  END q[256]
  PIN q[257]
    DIRECTION OUTPUT ;
    USE SIGNAL ;
    PORT
      LAYER M5 ;
        RECT  50.928 0 50.952 0.084 ;
    END
  END q[257]
  PIN q[258]
    DIRECTION OUTPUT ;
    USE SIGNAL ;
    PORT
      LAYER M5 ;
        RECT  53.184 0 53.208 0.084 ;
    END
  END q[258]
  PIN q[259]
    DIRECTION OUTPUT ;
    USE SIGNAL ;
    PORT
      LAYER M5 ;
        RECT  67.92 0 67.944 0.084 ;
    END
  END q[259]
  PIN q[25]
    DIRECTION OUTPUT ;
    USE SIGNAL ;
    PORT
      LAYER M7 ;
        RECT  21.568 0 21.6 0.069 ;
    END
  END q[25]
  PIN q[260]
    DIRECTION OUTPUT ;
    USE SIGNAL ;
    PORT
      LAYER M7 ;
        RECT  48.192 0 48.224 0.069 ;
    END
  END q[260]
  PIN q[261]
    DIRECTION OUTPUT ;
    USE SIGNAL ;
    PORT
      LAYER M5 ;
        RECT  50.352 0 50.376 0.084 ;
    END
  END q[261]
  PIN q[262]
    DIRECTION OUTPUT ;
    USE SIGNAL ;
    PORT
      LAYER M7 ;
        RECT  48.384 0 48.416 0.069 ;
    END
  END q[262]
  PIN q[263]
    DIRECTION OUTPUT ;
    USE SIGNAL ;
    PORT
      LAYER M7 ;
        RECT  47.552 0 47.584 0.069 ;
    END
  END q[263]
  PIN q[264]
    DIRECTION OUTPUT ;
    USE SIGNAL ;
    PORT
      LAYER M7 ;
        RECT  67.008 0 67.04 0.069 ;
    END
  END q[264]
  PIN q[265]
    DIRECTION OUTPUT ;
    USE SIGNAL ;
    PORT
      LAYER M5 ;
        RECT  49.92 0 49.944 0.084 ;
    END
  END q[265]
  PIN q[266]
    DIRECTION OUTPUT ;
    USE SIGNAL ;
    PORT
      LAYER M5 ;
        RECT  67.968 0 67.992 0.084 ;
    END
  END q[266]
  PIN q[267]
    DIRECTION OUTPUT ;
    USE SIGNAL ;
    PORT
      LAYER M7 ;
        RECT  56.832 0 56.864 0.069 ;
    END
  END q[267]
  PIN q[268]
    DIRECTION OUTPUT ;
    USE SIGNAL ;
    PORT
      LAYER M7 ;
        RECT  47.744 0 47.776 0.069 ;
    END
  END q[268]
  PIN q[269]
    DIRECTION OUTPUT ;
    USE SIGNAL ;
    PORT
      LAYER M7 ;
        RECT  48.128 0 48.16 0.069 ;
    END
  END q[269]
  PIN q[26]
    DIRECTION OUTPUT ;
    USE SIGNAL ;
    PORT
      LAYER M5 ;
        RECT  27.408 0 27.432 0.084 ;
    END
  END q[26]
  PIN q[270]
    DIRECTION OUTPUT ;
    USE SIGNAL ;
    PORT
      LAYER M7 ;
        RECT  46.4 0 46.432 0.069 ;
    END
  END q[270]
  PIN q[271]
    DIRECTION OUTPUT ;
    USE SIGNAL ;
    PORT
      LAYER M7 ;
        RECT  48.64 0 48.672 0.069 ;
    END
  END q[271]
  PIN q[272]
    DIRECTION OUTPUT ;
    USE SIGNAL ;
    PORT
      LAYER M5 ;
        RECT  50.448 0 50.472 0.084 ;
    END
  END q[272]
  PIN q[273]
    DIRECTION OUTPUT ;
    USE SIGNAL ;
    PORT
      LAYER M5 ;
        RECT  51.6 0 51.624 0.084 ;
    END
  END q[273]
  PIN q[274]
    DIRECTION OUTPUT ;
    USE SIGNAL ;
    PORT
      LAYER M7 ;
        RECT  48.32 0 48.352 0.069 ;
    END
  END q[274]
  PIN q[275]
    DIRECTION OUTPUT ;
    USE SIGNAL ;
    PORT
      LAYER M5 ;
        RECT  51.648 0 51.672 0.084 ;
    END
  END q[275]
  PIN q[276]
    DIRECTION OUTPUT ;
    USE SIGNAL ;
    PORT
      LAYER M7 ;
        RECT  48.256 0 48.288 0.069 ;
    END
  END q[276]
  PIN q[277]
    DIRECTION OUTPUT ;
    USE SIGNAL ;
    PORT
      LAYER M5 ;
        RECT  52.56 0 52.584 0.084 ;
    END
  END q[277]
  PIN q[278]
    DIRECTION OUTPUT ;
    USE SIGNAL ;
    PORT
      LAYER M5 ;
        RECT  62.736 0 62.76 0.084 ;
    END
  END q[278]
  PIN q[279]
    DIRECTION OUTPUT ;
    USE SIGNAL ;
    PORT
      LAYER M5 ;
        RECT  63.168 0 63.192 0.084 ;
    END
  END q[279]
  PIN q[27]
    DIRECTION OUTPUT ;
    USE SIGNAL ;
    PORT
      LAYER M7 ;
        RECT  32.896 0 32.928 0.069 ;
    END
  END q[27]
  PIN q[280]
    DIRECTION OUTPUT ;
    USE SIGNAL ;
    PORT
      LAYER M7 ;
        RECT  59.968 0 60 0.069 ;
    END
  END q[280]
  PIN q[281]
    DIRECTION OUTPUT ;
    USE SIGNAL ;
    PORT
      LAYER M7 ;
        RECT  58.816 0 58.848 0.069 ;
    END
  END q[281]
  PIN q[282]
    DIRECTION OUTPUT ;
    USE SIGNAL ;
    PORT
      LAYER M7 ;
        RECT  56.64 0 56.672 0.069 ;
    END
  END q[282]
  PIN q[283]
    DIRECTION OUTPUT ;
    USE SIGNAL ;
    PORT
      LAYER M5 ;
        RECT  54.816 0 54.84 0.084 ;
    END
  END q[283]
  PIN q[284]
    DIRECTION OUTPUT ;
    USE SIGNAL ;
    PORT
      LAYER M5 ;
        RECT  63.936 0 63.96 0.084 ;
    END
  END q[284]
  PIN q[285]
    DIRECTION OUTPUT ;
    USE SIGNAL ;
    PORT
      LAYER M7 ;
        RECT  57.664 0 57.696 0.069 ;
    END
  END q[285]
  PIN q[286]
    DIRECTION OUTPUT ;
    USE SIGNAL ;
    PORT
      LAYER M7 ;
        RECT  59.008 0 59.04 0.069 ;
    END
  END q[286]
  PIN q[287]
    DIRECTION OUTPUT ;
    USE SIGNAL ;
    PORT
      LAYER M5 ;
        RECT  62.16 0 62.184 0.084 ;
    END
  END q[287]
  PIN q[288]
    DIRECTION OUTPUT ;
    USE SIGNAL ;
    PORT
      LAYER M5 ;
        RECT  61.392 0 61.416 0.084 ;
    END
  END q[288]
  PIN q[289]
    DIRECTION OUTPUT ;
    USE SIGNAL ;
    PORT
      LAYER M5 ;
        RECT  63.216 0 63.24 0.084 ;
    END
  END q[289]
  PIN q[28]
    DIRECTION OUTPUT ;
    USE SIGNAL ;
    PORT
      LAYER M7 ;
        RECT  18.816 0 18.848 0.069 ;
    END
  END q[28]
  PIN q[290]
    DIRECTION OUTPUT ;
    USE SIGNAL ;
    PORT
      LAYER M5 ;
        RECT  63.024 0 63.048 0.084 ;
    END
  END q[290]
  PIN q[291]
    DIRECTION OUTPUT ;
    USE SIGNAL ;
    PORT
      LAYER M7 ;
        RECT  65.856 0 65.888 0.069 ;
    END
  END q[291]
  PIN q[292]
    DIRECTION OUTPUT ;
    USE SIGNAL ;
    PORT
      LAYER M7 ;
        RECT  65.664 0 65.696 0.069 ;
    END
  END q[292]
  PIN q[293]
    DIRECTION OUTPUT ;
    USE SIGNAL ;
    PORT
      LAYER M7 ;
        RECT  66.496 0 66.528 0.069 ;
    END
  END q[293]
  PIN q[294]
    DIRECTION OUTPUT ;
    USE SIGNAL ;
    PORT
      LAYER M5 ;
        RECT  69.12 0 69.144 0.084 ;
    END
  END q[294]
  PIN q[295]
    DIRECTION OUTPUT ;
    USE SIGNAL ;
    PORT
      LAYER M5 ;
        RECT  68.832 0 68.856 0.084 ;
    END
  END q[295]
  PIN q[296]
    DIRECTION OUTPUT ;
    USE SIGNAL ;
    PORT
      LAYER M7 ;
        RECT  66.752 0 66.784 0.069 ;
    END
  END q[296]
  PIN q[297]
    DIRECTION OUTPUT ;
    USE SIGNAL ;
    PORT
      LAYER M5 ;
        RECT  68.544 0 68.568 0.084 ;
    END
  END q[297]
  PIN q[298]
    DIRECTION OUTPUT ;
    USE SIGNAL ;
    PORT
      LAYER M5 ;
        RECT  68.592 0 68.616 0.084 ;
    END
  END q[298]
  PIN q[299]
    DIRECTION OUTPUT ;
    USE SIGNAL ;
    PORT
      LAYER M5 ;
        RECT  68.4 0 68.424 0.084 ;
    END
  END q[299]
  PIN q[29]
    DIRECTION OUTPUT ;
    USE SIGNAL ;
    PORT
      LAYER M7 ;
        RECT  20.096 0 20.128 0.069 ;
    END
  END q[29]
  PIN q[2]
    DIRECTION OUTPUT ;
    USE SIGNAL ;
    PORT
      LAYER M5 ;
        RECT  38.256 0 38.28 0.084 ;
    END
  END q[2]
  PIN q[300]
    DIRECTION OUTPUT ;
    USE SIGNAL ;
    PORT
      LAYER M5 ;
        RECT  68.352 0 68.376 0.084 ;
    END
  END q[300]
  PIN q[301]
    DIRECTION OUTPUT ;
    USE SIGNAL ;
    PORT
      LAYER M5 ;
        RECT  68.88 0 68.904 0.084 ;
    END
  END q[301]
  PIN q[302]
    DIRECTION OUTPUT ;
    USE SIGNAL ;
    PORT
      LAYER M5 ;
        RECT  69.072 0 69.096 0.084 ;
    END
  END q[302]
  PIN q[303]
    DIRECTION OUTPUT ;
    USE SIGNAL ;
    PORT
      LAYER M5 ;
        RECT  68.256 0 68.28 0.084 ;
    END
  END q[303]
  PIN q[304]
    DIRECTION OUTPUT ;
    USE SIGNAL ;
    PORT
      LAYER M5 ;
        RECT  68.208 0 68.232 0.084 ;
    END
  END q[304]
  PIN q[305]
    DIRECTION OUTPUT ;
    USE SIGNAL ;
    PORT
      LAYER M5 ;
        RECT  68.688 0 68.712 0.084 ;
    END
  END q[305]
  PIN q[306]
    DIRECTION OUTPUT ;
    USE SIGNAL ;
    PORT
      LAYER M5 ;
        RECT  68.16 0 68.184 0.084 ;
    END
  END q[306]
  PIN q[307]
    DIRECTION OUTPUT ;
    USE SIGNAL ;
    PORT
      LAYER M5 ;
        RECT  68.928 0 68.952 0.084 ;
    END
  END q[307]
  PIN q[308]
    DIRECTION OUTPUT ;
    USE SIGNAL ;
    PORT
      LAYER M5 ;
        RECT  68.64 0 68.664 0.084 ;
    END
  END q[308]
  PIN q[309]
    DIRECTION OUTPUT ;
    USE SIGNAL ;
    PORT
      LAYER M5 ;
        RECT  68.736 0 68.76 0.084 ;
    END
  END q[309]
  PIN q[30]
    DIRECTION OUTPUT ;
    USE SIGNAL ;
    PORT
      LAYER M7 ;
        RECT  21.952 0 21.984 0.069 ;
    END
  END q[30]
  PIN q[310]
    DIRECTION OUTPUT ;
    USE SIGNAL ;
    PORT
      LAYER M5 ;
        RECT  69.024 0 69.048 0.084 ;
    END
  END q[310]
  PIN q[311]
    DIRECTION OUTPUT ;
    USE SIGNAL ;
    PORT
      LAYER M5 ;
        RECT  68.112 0 68.136 0.084 ;
    END
  END q[311]
  PIN q[312]
    DIRECTION OUTPUT ;
    USE SIGNAL ;
    PORT
      LAYER M5 ;
        RECT  68.304 0 68.328 0.084 ;
    END
  END q[312]
  PIN q[313]
    DIRECTION OUTPUT ;
    USE SIGNAL ;
    PORT
      LAYER M5 ;
        RECT  68.784 0 68.808 0.084 ;
    END
  END q[313]
  PIN q[314]
    DIRECTION OUTPUT ;
    USE SIGNAL ;
    PORT
      LAYER M5 ;
        RECT  68.448 0 68.472 0.084 ;
    END
  END q[314]
  PIN q[315]
    DIRECTION OUTPUT ;
    USE SIGNAL ;
    PORT
      LAYER M5 ;
        RECT  68.064 0 68.088 0.084 ;
    END
  END q[315]
  PIN q[316]
    DIRECTION OUTPUT ;
    USE SIGNAL ;
    PORT
      LAYER M5 ;
        RECT  68.016 0 68.04 0.084 ;
    END
  END q[316]
  PIN q[317]
    DIRECTION OUTPUT ;
    USE SIGNAL ;
    PORT
      LAYER M5 ;
        RECT  68.976 0 69 0.084 ;
    END
  END q[317]
  PIN q[318]
    DIRECTION OUTPUT ;
    USE SIGNAL ;
    PORT
      LAYER M5 ;
        RECT  68.496 0 68.52 0.084 ;
    END
  END q[318]
  PIN q[319]
    DIRECTION OUTPUT ;
    USE SIGNAL ;
    PORT
      LAYER M7 ;
        RECT  65.6 0 65.632 0.069 ;
    END
  END q[319]
  PIN q[31]
    DIRECTION OUTPUT ;
    USE SIGNAL ;
    PORT
      LAYER M7 ;
        RECT  17.536 0 17.568 0.069 ;
    END
  END q[31]
  PIN q[32]
    DIRECTION OUTPUT ;
    USE SIGNAL ;
    PORT
      LAYER M5 ;
        RECT  38.112 0 38.136 0.084 ;
    END
  END q[32]
  PIN q[33]
    DIRECTION OUTPUT ;
    USE SIGNAL ;
    PORT
      LAYER M5 ;
        RECT  38.208 0 38.232 0.084 ;
    END
  END q[33]
  PIN q[34]
    DIRECTION OUTPUT ;
    USE SIGNAL ;
    PORT
      LAYER M5 ;
        RECT  38.304 0 38.328 0.084 ;
    END
  END q[34]
  PIN q[35]
    DIRECTION OUTPUT ;
    USE SIGNAL ;
    PORT
      LAYER M5 ;
        RECT  33.936 0 33.96 0.084 ;
    END
  END q[35]
  PIN q[36]
    DIRECTION OUTPUT ;
    USE SIGNAL ;
    PORT
      LAYER M5 ;
        RECT  36.288 0 36.312 0.084 ;
    END
  END q[36]
  PIN q[37]
    DIRECTION OUTPUT ;
    USE SIGNAL ;
    PORT
      LAYER M7 ;
        RECT  18.944 0 18.976 0.069 ;
    END
  END q[37]
  PIN q[38]
    DIRECTION OUTPUT ;
    USE SIGNAL ;
    PORT
      LAYER M7 ;
        RECT  8.64 0 8.672 0.069 ;
    END
  END q[38]
  PIN q[39]
    DIRECTION OUTPUT ;
    USE SIGNAL ;
    PORT
      LAYER M5 ;
        RECT  12.912 0 12.936 0.084 ;
    END
  END q[39]
  PIN q[3]
    DIRECTION OUTPUT ;
    USE SIGNAL ;
    PORT
      LAYER M5 ;
        RECT  38.16 0 38.184 0.084 ;
    END
  END q[3]
  PIN q[40]
    DIRECTION OUTPUT ;
    USE SIGNAL ;
    PORT
      LAYER M5 ;
        RECT  36 0 36.024 0.084 ;
    END
  END q[40]
  PIN q[41]
    DIRECTION OUTPUT ;
    USE SIGNAL ;
    PORT
      LAYER M7 ;
        RECT  6.72 0 6.752 0.069 ;
    END
  END q[41]
  PIN q[42]
    DIRECTION OUTPUT ;
    USE SIGNAL ;
    PORT
      LAYER M5 ;
        RECT  37.536 0 37.56 0.084 ;
    END
  END q[42]
  PIN q[43]
    DIRECTION OUTPUT ;
    USE SIGNAL ;
    PORT
      LAYER M5 ;
        RECT  15.6 0 15.624 0.084 ;
    END
  END q[43]
  PIN q[44]
    DIRECTION OUTPUT ;
    USE SIGNAL ;
    PORT
      LAYER M7 ;
        RECT  8.448 0 8.48 0.069 ;
    END
  END q[44]
  PIN q[45]
    DIRECTION OUTPUT ;
    USE SIGNAL ;
    PORT
      LAYER M5 ;
        RECT  33.552 0 33.576 0.084 ;
    END
  END q[45]
  PIN q[46]
    DIRECTION OUTPUT ;
    USE SIGNAL ;
    PORT
      LAYER M7 ;
        RECT  32.96 0 32.992 0.069 ;
    END
  END q[46]
  PIN q[47]
    DIRECTION OUTPUT ;
    USE SIGNAL ;
    PORT
      LAYER M7 ;
        RECT  32.128 0 32.16 0.069 ;
    END
  END q[47]
  PIN q[48]
    DIRECTION OUTPUT ;
    USE SIGNAL ;
    PORT
      LAYER M5 ;
        RECT  17.136 0 17.16 0.084 ;
    END
  END q[48]
  PIN q[49]
    DIRECTION OUTPUT ;
    USE SIGNAL ;
    PORT
      LAYER M5 ;
        RECT  36.432 0 36.456 0.084 ;
    END
  END q[49]
  PIN q[4]
    DIRECTION OUTPUT ;
    USE SIGNAL ;
    PORT
      LAYER M5 ;
        RECT  37.44 0 37.464 0.084 ;
    END
  END q[4]
  PIN q[50]
    DIRECTION OUTPUT ;
    USE SIGNAL ;
    PORT
      LAYER M5 ;
        RECT  37.152 0 37.176 0.084 ;
    END
  END q[50]
  PIN q[51]
    DIRECTION OUTPUT ;
    USE SIGNAL ;
    PORT
      LAYER M5 ;
        RECT  38.592 0 38.616 0.084 ;
    END
  END q[51]
  PIN q[52]
    DIRECTION OUTPUT ;
    USE SIGNAL ;
    PORT
      LAYER M5 ;
        RECT  38.64 0 38.664 0.084 ;
    END
  END q[52]
  PIN q[53]
    DIRECTION OUTPUT ;
    USE SIGNAL ;
    PORT
      LAYER M5 ;
        RECT  38.88 0 38.904 0.084 ;
    END
  END q[53]
  PIN q[54]
    DIRECTION OUTPUT ;
    USE SIGNAL ;
    PORT
      LAYER M5 ;
        RECT  37.68 0 37.704 0.084 ;
    END
  END q[54]
  PIN q[55]
    DIRECTION OUTPUT ;
    USE SIGNAL ;
    PORT
      LAYER M5 ;
        RECT  37.008 0 37.032 0.084 ;
    END
  END q[55]
  PIN q[56]
    DIRECTION OUTPUT ;
    USE SIGNAL ;
    PORT
      LAYER M5 ;
        RECT  37.92 0 37.944 0.084 ;
    END
  END q[56]
  PIN q[57]
    DIRECTION OUTPUT ;
    USE SIGNAL ;
    PORT
      LAYER M5 ;
        RECT  38.016 0 38.04 0.084 ;
    END
  END q[57]
  PIN q[58]
    DIRECTION OUTPUT ;
    USE SIGNAL ;
    PORT
      LAYER M5 ;
        RECT  39.072 0 39.096 0.084 ;
    END
  END q[58]
  PIN q[59]
    DIRECTION OUTPUT ;
    USE SIGNAL ;
    PORT
      LAYER M5 ;
        RECT  36.144 0 36.168 0.084 ;
    END
  END q[59]
  PIN q[5]
    DIRECTION OUTPUT ;
    USE SIGNAL ;
    PORT
      LAYER M5 ;
        RECT  35.568 0 35.592 0.084 ;
    END
  END q[5]
  PIN q[60]
    DIRECTION OUTPUT ;
    USE SIGNAL ;
    PORT
      LAYER M5 ;
        RECT  39.36 0 39.384 0.084 ;
    END
  END q[60]
  PIN q[61]
    DIRECTION OUTPUT ;
    USE SIGNAL ;
    PORT
      LAYER M5 ;
        RECT  40.368 0 40.392 0.084 ;
    END
  END q[61]
  PIN q[62]
    DIRECTION OUTPUT ;
    USE SIGNAL ;
    PORT
      LAYER M5 ;
        RECT  39.408 0 39.432 0.084 ;
    END
  END q[62]
  PIN q[63]
    DIRECTION OUTPUT ;
    USE SIGNAL ;
    PORT
      LAYER M5 ;
        RECT  40.032 0 40.056 0.084 ;
    END
  END q[63]
  PIN q[64]
    DIRECTION OUTPUT ;
    USE SIGNAL ;
    PORT
      LAYER M7 ;
        RECT  20.16 0 20.192 0.069 ;
    END
  END q[64]
  PIN q[65]
    DIRECTION OUTPUT ;
    USE SIGNAL ;
    PORT
      LAYER M5 ;
        RECT  28.704 0 28.728 0.084 ;
    END
  END q[65]
  PIN q[66]
    DIRECTION OUTPUT ;
    USE SIGNAL ;
    PORT
      LAYER M5 ;
        RECT  16.896 0 16.92 0.084 ;
    END
  END q[66]
  PIN q[67]
    DIRECTION OUTPUT ;
    USE SIGNAL ;
    PORT
      LAYER M5 ;
        RECT  28.176 0 28.2 0.084 ;
    END
  END q[67]
  PIN q[68]
    DIRECTION OUTPUT ;
    USE SIGNAL ;
    PORT
      LAYER M7 ;
        RECT  8.576 0 8.608 0.069 ;
    END
  END q[68]
  PIN q[69]
    DIRECTION OUTPUT ;
    USE SIGNAL ;
    PORT
      LAYER M7 ;
        RECT  11.008 0 11.04 0.069 ;
    END
  END q[69]
  PIN q[6]
    DIRECTION OUTPUT ;
    USE SIGNAL ;
    PORT
      LAYER M5 ;
        RECT  36.96 0 36.984 0.084 ;
    END
  END q[6]
  PIN q[70]
    DIRECTION OUTPUT ;
    USE SIGNAL ;
    PORT
      LAYER M5 ;
        RECT  11.52 0 11.544 0.084 ;
    END
  END q[70]
  PIN q[71]
    DIRECTION OUTPUT ;
    USE SIGNAL ;
    PORT
      LAYER M7 ;
        RECT  8.32 0 8.352 0.069 ;
    END
  END q[71]
  PIN q[72]
    DIRECTION OUTPUT ;
    USE SIGNAL ;
    PORT
      LAYER M7 ;
        RECT  9.792 0 9.824 0.069 ;
    END
  END q[72]
  PIN q[73]
    DIRECTION OUTPUT ;
    USE SIGNAL ;
    PORT
      LAYER M7 ;
        RECT  9.344 0 9.376 0.069 ;
    END
  END q[73]
  PIN q[74]
    DIRECTION OUTPUT ;
    USE SIGNAL ;
    PORT
      LAYER M7 ;
        RECT  21.376 0 21.408 0.069 ;
    END
  END q[74]
  PIN q[75]
    DIRECTION OUTPUT ;
    USE SIGNAL ;
    PORT
      LAYER M5 ;
        RECT  15.984 0 16.008 0.084 ;
    END
  END q[75]
  PIN q[76]
    DIRECTION OUTPUT ;
    USE SIGNAL ;
    PORT
      LAYER M5 ;
        RECT  14.304 0 14.328 0.084 ;
    END
  END q[76]
  PIN q[77]
    DIRECTION OUTPUT ;
    USE SIGNAL ;
    PORT
      LAYER M5 ;
        RECT  6.288 0 6.312 0.084 ;
    END
  END q[77]
  PIN q[78]
    DIRECTION OUTPUT ;
    USE SIGNAL ;
    PORT
      LAYER M5 ;
        RECT  25.632 0 25.656 0.084 ;
    END
  END q[78]
  PIN q[79]
    DIRECTION OUTPUT ;
    USE SIGNAL ;
    PORT
      LAYER M5 ;
        RECT  26.64 0 26.664 0.084 ;
    END
  END q[79]
  PIN q[7]
    DIRECTION OUTPUT ;
    USE SIGNAL ;
    PORT
      LAYER M5 ;
        RECT  40.464 0 40.488 0.084 ;
    END
  END q[7]
  PIN q[80]
    DIRECTION OUTPUT ;
    USE SIGNAL ;
    PORT
      LAYER M5 ;
        RECT  5.904 0 5.928 0.084 ;
    END
  END q[80]
  PIN q[81]
    DIRECTION OUTPUT ;
    USE SIGNAL ;
    PORT
      LAYER M7 ;
        RECT  6.656 0 6.688 0.069 ;
    END
  END q[81]
  PIN q[82]
    DIRECTION OUTPUT ;
    USE SIGNAL ;
    PORT
      LAYER M5 ;
        RECT  2.928 0 2.952 0.084 ;
    END
  END q[82]
  PIN q[83]
    DIRECTION OUTPUT ;
    USE SIGNAL ;
    PORT
      LAYER M5 ;
        RECT  1.92 0 1.944 0.084 ;
    END
  END q[83]
  PIN q[84]
    DIRECTION OUTPUT ;
    USE SIGNAL ;
    PORT
      LAYER M5 ;
        RECT  4.176 0 4.2 0.084 ;
    END
  END q[84]
  PIN q[85]
    DIRECTION OUTPUT ;
    USE SIGNAL ;
    PORT
      LAYER M7 ;
        RECT  6.336 0 6.368 0.069 ;
    END
  END q[85]
  PIN q[86]
    DIRECTION OUTPUT ;
    USE SIGNAL ;
    PORT
      LAYER M5 ;
        RECT  5.184 0 5.208 0.084 ;
    END
  END q[86]
  PIN q[87]
    DIRECTION OUTPUT ;
    USE SIGNAL ;
    PORT
      LAYER M5 ;
        RECT  3.888 0 3.912 0.084 ;
    END
  END q[87]
  PIN q[88]
    DIRECTION OUTPUT ;
    USE SIGNAL ;
    PORT
      LAYER M5 ;
        RECT  2.784 0 2.808 0.084 ;
    END
  END q[88]
  PIN q[89]
    DIRECTION OUTPUT ;
    USE SIGNAL ;
    PORT
      LAYER M5 ;
        RECT  3.264 0 3.288 0.084 ;
    END
  END q[89]
  PIN q[8]
    DIRECTION OUTPUT ;
    USE SIGNAL ;
    PORT
      LAYER M5 ;
        RECT  26.064 0 26.088 0.084 ;
    END
  END q[8]
  PIN q[90]
    DIRECTION OUTPUT ;
    USE SIGNAL ;
    PORT
      LAYER M5 ;
        RECT  4.416 0 4.44 0.084 ;
    END
  END q[90]
  PIN q[91]
    DIRECTION OUTPUT ;
    USE SIGNAL ;
    PORT
      LAYER M5 ;
        RECT  3.408 0 3.432 0.084 ;
    END
  END q[91]
  PIN q[92]
    DIRECTION OUTPUT ;
    USE SIGNAL ;
    PORT
      LAYER M5 ;
        RECT  5.136 0 5.16 0.084 ;
    END
  END q[92]
  PIN q[93]
    DIRECTION OUTPUT ;
    USE SIGNAL ;
    PORT
      LAYER M5 ;
        RECT  5.424 0 5.448 0.084 ;
    END
  END q[93]
  PIN q[94]
    DIRECTION OUTPUT ;
    USE SIGNAL ;
    PORT
      LAYER M5 ;
        RECT  3.36 0 3.384 0.084 ;
    END
  END q[94]
  PIN q[95]
    DIRECTION OUTPUT ;
    USE SIGNAL ;
    PORT
      LAYER M5 ;
        RECT  4.032 0 4.056 0.084 ;
    END
  END q[95]
  PIN q[96]
    DIRECTION OUTPUT ;
    USE SIGNAL ;
    PORT
      LAYER M5 ;
        RECT  6.192 0 6.216 0.084 ;
    END
  END q[96]
  PIN q[97]
    DIRECTION OUTPUT ;
    USE SIGNAL ;
    PORT
      LAYER M7 ;
        RECT  6.464 0 6.496 0.069 ;
    END
  END q[97]
  PIN q[98]
    DIRECTION OUTPUT ;
    USE SIGNAL ;
    PORT
      LAYER M5 ;
        RECT  2.832 0 2.856 0.084 ;
    END
  END q[98]
  PIN q[99]
    DIRECTION OUTPUT ;
    USE SIGNAL ;
    PORT
      LAYER M5 ;
        RECT  5.472 0 5.496 0.084 ;
    END
  END q[99]
  PIN q[9]
    DIRECTION OUTPUT ;
    USE SIGNAL ;
    PORT
      LAYER M7 ;
        RECT  7.168 0 7.2 0.069 ;
    END
  END q[9]
  PIN rst_e
    DIRECTION INPUT ;
    USE SIGNAL ;
    PORT
      LAYER M5 ;
        RECT  21.84 0 21.864 0.084 ;
    END
  END rst_e
  PIN rst_p
    DIRECTION INPUT ;
    USE SIGNAL ;
    PORT
      LAYER M5 ;
        RECT  29.808 0 29.832 0.084 ;
    END
  END rst_p
  PIN v_bad
    DIRECTION OUTPUT ;
    USE SIGNAL ;
    PORT
      LAYER M5 ;
        RECT  38.496 0 38.52 0.084 ;
    END
  END v_bad
  PIN v_cbad
    DIRECTION OUTPUT ;
    USE SIGNAL ;
    PORT
      LAYER M5 ;
        RECT  34.416 0 34.44 0.084 ;
    END
  END v_cbad
  PIN v_ce
    DIRECTION OUTPUT ;
    USE SIGNAL ;
    PORT
      LAYER M5 ;
        RECT  35.712 0 35.736 0.084 ;
    END
  END v_ce
  PIN v_clean
    DIRECTION OUTPUT ;
    USE SIGNAL ;
    PORT
      LAYER M5 ;
        RECT  37.728 0 37.752 0.084 ;
    END
  END v_clean
  PIN v_same
    DIRECTION OUTPUT ;
    USE SIGNAL ;
    PORT
      LAYER M5 ;
        RECT  35.76 0 35.784 0.084 ;
    END
  END v_same
  PIN v_ue
    DIRECTION OUTPUT ;
    USE SIGNAL ;
    PORT
      LAYER M5 ;
        RECT  37.344 0 37.368 0.084 ;
    END
  END v_ue
  PIN VDD
    DIRECTION INOUT ;
    USE POWER ;
    PORT
      LAYER M6 ;
        RECT  1.08 72.033 68.904 72.321 ;
        RECT  1.08 66.633 68.904 66.921 ;
        RECT  1.08 61.233 68.904 61.521 ;
        RECT  1.08 55.833 68.904 56.121 ;
        RECT  1.08 50.433 68.904 50.721 ;
        RECT  1.08 45.033 68.904 45.321 ;
        RECT  1.08 39.633 68.904 39.921 ;
        RECT  1.08 34.233 68.904 34.521 ;
        RECT  1.08 28.833 68.904 29.121 ;
        RECT  1.08 23.433 68.904 23.721 ;
        RECT  1.08 18.033 68.904 18.321 ;
        RECT  1.08 12.633 68.904 12.921 ;
        RECT  1.08 7.233 68.904 7.521 ;
        RECT  1.08 1.833 68.904 2.121 ;
    END
  END VDD
  PIN VSS
    DIRECTION INOUT ;
    USE GROUND ;
    PORT
      LAYER M6 ;
        RECT  1.08 71.649 68.904 71.937 ;
        RECT  1.08 66.249 68.904 66.537 ;
        RECT  1.08 60.849 68.904 61.137 ;
        RECT  1.08 55.449 68.904 55.737 ;
        RECT  1.08 50.049 68.904 50.337 ;
        RECT  1.08 44.649 68.904 44.937 ;
        RECT  1.08 39.249 68.904 39.537 ;
        RECT  1.08 33.849 68.904 34.137 ;
        RECT  1.08 28.449 68.904 28.737 ;
        RECT  1.08 23.049 68.904 23.337 ;
        RECT  1.08 17.649 68.904 17.937 ;
        RECT  1.08 12.249 68.904 12.537 ;
        RECT  1.08 6.849 68.904 7.137 ;
        RECT  1.08 1.449 68.904 1.737 ;
    END
  END VSS
  OBS
    LAYER RVTN ;
     RECT  1.08 0 69.251 76 ;
    LAYER RVTP ;
     RECT  1.08 0 69.251 76 ;
    LAYER M1 ;
     RECT  1.08 0 69.251 76 ;
    LAYER M2 ;
     RECT  1.08 0 69.251 76 ;
    LAYER M3 ;
     RECT  1.08 0 69.251 76 ;
    LAYER M4 ;
     RECT  1.08 0 69.251 76 ;
    LAYER M5 ;
     RECT  1.08 0 69.251 76 ;
    LAYER M6 ;
     RECT  1.08 0 69.251 76 ;
    LAYER M7 ;
     RECT  1.08 0 69.251 76 ;
  END
END ot_hbm_w2_stn_slice5
END LIBRARY
